VERSION 5.8 ;
BUSBITCHARS "[]" ;
DIVIDERCHAR "/" ;
UNITS
    DATABASE MICRONS 1000 ;
END UNITS

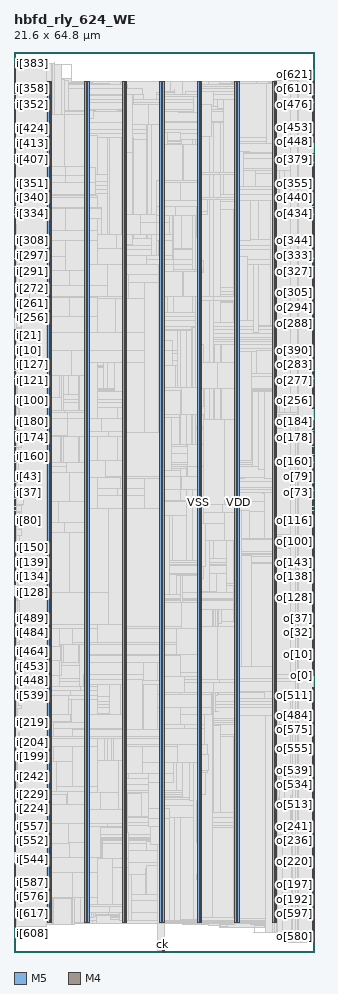
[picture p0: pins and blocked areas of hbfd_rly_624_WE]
MACRO hbfd_rly_624_WE
  FOREIGN hbfd_rly_624_WE 0 0 ;
  CLASS BLOCK ;
  SIZE 21.6 BY 64.8 ;
  PIN ck
    DIRECTION INPUT ;
    USE SIGNAL ;
    PORT
      LAYER M5 ;
        RECT  10.704 0 10.728 0.084 ;
    END
  END ck
  PIN i[0]
    DIRECTION INPUT ;
    USE SIGNAL ;
    PORT
      LAYER M4 ;
        RECT  0 41.808 0.084 41.832 ;
    END
  END i[0]
  PIN i[100]
    DIRECTION INPUT ;
    USE SIGNAL ;
    PORT
      LAYER M4 ;
        RECT  0 39.12 0.084 39.144 ;
    END
  END i[100]
  PIN i[101]
    DIRECTION INPUT ;
    USE SIGNAL ;
    PORT
      LAYER M4 ;
        RECT  0 39.216 0.084 39.24 ;
    END
  END i[101]
  PIN i[102]
    DIRECTION INPUT ;
    USE SIGNAL ;
    PORT
      LAYER M4 ;
        RECT  0 39.312 0.084 39.336 ;
    END
  END i[102]
  PIN i[103]
    DIRECTION INPUT ;
    USE SIGNAL ;
    PORT
      LAYER M4 ;
        RECT  0 39.408 0.084 39.432 ;
    END
  END i[103]
  PIN i[104]
    DIRECTION INPUT ;
    USE SIGNAL ;
    PORT
      LAYER M4 ;
        RECT  0 39.504 0.084 39.528 ;
    END
  END i[104]
  PIN i[105]
    DIRECTION INPUT ;
    USE SIGNAL ;
    PORT
      LAYER M4 ;
        RECT  0 39.6 0.084 39.624 ;
    END
  END i[105]
  PIN i[106]
    DIRECTION INPUT ;
    USE SIGNAL ;
    PORT
      LAYER M4 ;
        RECT  0 39.696 0.084 39.72 ;
    END
  END i[106]
  PIN i[107]
    DIRECTION INPUT ;
    USE SIGNAL ;
    PORT
      LAYER M4 ;
        RECT  0 39.792 0.084 39.816 ;
    END
  END i[107]
  PIN i[108]
    DIRECTION INPUT ;
    USE SIGNAL ;
    PORT
      LAYER M4 ;
        RECT  0 39.888 0.084 39.912 ;
    END
  END i[108]
  PIN i[109]
    DIRECTION INPUT ;
    USE SIGNAL ;
    PORT
      LAYER M4 ;
        RECT  0 39.984 0.084 40.008 ;
    END
  END i[109]
  PIN i[10]
    DIRECTION INPUT ;
    USE SIGNAL ;
    PORT
      LAYER M4 ;
        RECT  0 42.768 0.084 42.792 ;
    END
  END i[10]
  PIN i[110]
    DIRECTION INPUT ;
    USE SIGNAL ;
    PORT
      LAYER M4 ;
        RECT  0 40.08 0.084 40.104 ;
    END
  END i[110]
  PIN i[111]
    DIRECTION INPUT ;
    USE SIGNAL ;
    PORT
      LAYER M4 ;
        RECT  0 40.176 0.084 40.2 ;
    END
  END i[111]
  PIN i[112]
    DIRECTION INPUT ;
    USE SIGNAL ;
    PORT
      LAYER M4 ;
        RECT  0 40.272 0.084 40.296 ;
    END
  END i[112]
  PIN i[113]
    DIRECTION INPUT ;
    USE SIGNAL ;
    PORT
      LAYER M4 ;
        RECT  0 40.368 0.084 40.392 ;
    END
  END i[113]
  PIN i[114]
    DIRECTION INPUT ;
    USE SIGNAL ;
    PORT
      LAYER M4 ;
        RECT  0 40.464 0.084 40.488 ;
    END
  END i[114]
  PIN i[115]
    DIRECTION INPUT ;
    USE SIGNAL ;
    PORT
      LAYER M4 ;
        RECT  0 40.56 0.084 40.584 ;
    END
  END i[115]
  PIN i[116]
    DIRECTION INPUT ;
    USE SIGNAL ;
    PORT
      LAYER M4 ;
        RECT  0 40.656 0.084 40.68 ;
    END
  END i[116]
  PIN i[117]
    DIRECTION INPUT ;
    USE SIGNAL ;
    PORT
      LAYER M4 ;
        RECT  0 40.752 0.084 40.776 ;
    END
  END i[117]
  PIN i[118]
    DIRECTION INPUT ;
    USE SIGNAL ;
    PORT
      LAYER M4 ;
        RECT  0 40.848 0.084 40.872 ;
    END
  END i[118]
  PIN i[119]
    DIRECTION INPUT ;
    USE SIGNAL ;
    PORT
      LAYER M4 ;
        RECT  0 40.944 0.084 40.968 ;
    END
  END i[119]
  PIN i[11]
    DIRECTION INPUT ;
    USE SIGNAL ;
    PORT
      LAYER M4 ;
        RECT  0 42.864 0.084 42.888 ;
    END
  END i[11]
  PIN i[120]
    DIRECTION INPUT ;
    USE SIGNAL ;
    PORT
      LAYER M4 ;
        RECT  0 41.04 0.084 41.064 ;
    END
  END i[120]
  PIN i[121]
    DIRECTION INPUT ;
    USE SIGNAL ;
    PORT
      LAYER M4 ;
        RECT  0 41.136 0.084 41.16 ;
    END
  END i[121]
  PIN i[122]
    DIRECTION INPUT ;
    USE SIGNAL ;
    PORT
      LAYER M4 ;
        RECT  0 41.232 0.084 41.256 ;
    END
  END i[122]
  PIN i[123]
    DIRECTION INPUT ;
    USE SIGNAL ;
    PORT
      LAYER M4 ;
        RECT  0 41.328 0.084 41.352 ;
    END
  END i[123]
  PIN i[124]
    DIRECTION INPUT ;
    USE SIGNAL ;
    PORT
      LAYER M4 ;
        RECT  0 41.424 0.084 41.448 ;
    END
  END i[124]
  PIN i[125]
    DIRECTION INPUT ;
    USE SIGNAL ;
    PORT
      LAYER M4 ;
        RECT  0 41.52 0.084 41.544 ;
    END
  END i[125]
  PIN i[126]
    DIRECTION INPUT ;
    USE SIGNAL ;
    PORT
      LAYER M4 ;
        RECT  0 41.616 0.084 41.64 ;
    END
  END i[126]
  PIN i[127]
    DIRECTION INPUT ;
    USE SIGNAL ;
    PORT
      LAYER M4 ;
        RECT  0 41.712 0.084 41.736 ;
    END
  END i[127]
  PIN i[128]
    DIRECTION INPUT ;
    USE SIGNAL ;
    PORT
      LAYER M4 ;
        RECT  0 26.448 0.084 26.472 ;
    END
  END i[128]
  PIN i[129]
    DIRECTION INPUT ;
    USE SIGNAL ;
    PORT
      LAYER M4 ;
        RECT  0 26.544 0.084 26.568 ;
    END
  END i[129]
  PIN i[12]
    DIRECTION INPUT ;
    USE SIGNAL ;
    PORT
      LAYER M4 ;
        RECT  0 42.96 0.084 42.984 ;
    END
  END i[12]
  PIN i[130]
    DIRECTION INPUT ;
    USE SIGNAL ;
    PORT
      LAYER M4 ;
        RECT  0 26.64 0.084 26.664 ;
    END
  END i[130]
  PIN i[131]
    DIRECTION INPUT ;
    USE SIGNAL ;
    PORT
      LAYER M4 ;
        RECT  0 26.736 0.084 26.76 ;
    END
  END i[131]
  PIN i[132]
    DIRECTION INPUT ;
    USE SIGNAL ;
    PORT
      LAYER M4 ;
        RECT  0 26.832 0.084 26.856 ;
    END
  END i[132]
  PIN i[133]
    DIRECTION INPUT ;
    USE SIGNAL ;
    PORT
      LAYER M4 ;
        RECT  0 26.928 0.084 26.952 ;
    END
  END i[133]
  PIN i[134]
    DIRECTION INPUT ;
    USE SIGNAL ;
    PORT
      LAYER M4 ;
        RECT  0 27.024 0.084 27.048 ;
    END
  END i[134]
  PIN i[135]
    DIRECTION INPUT ;
    USE SIGNAL ;
    PORT
      LAYER M4 ;
        RECT  0 27.12 0.084 27.144 ;
    END
  END i[135]
  PIN i[136]
    DIRECTION INPUT ;
    USE SIGNAL ;
    PORT
      LAYER M4 ;
        RECT  0 27.216 0.084 27.24 ;
    END
  END i[136]
  PIN i[137]
    DIRECTION INPUT ;
    USE SIGNAL ;
    PORT
      LAYER M4 ;
        RECT  0 27.312 0.084 27.336 ;
    END
  END i[137]
  PIN i[138]
    DIRECTION INPUT ;
    USE SIGNAL ;
    PORT
      LAYER M4 ;
        RECT  0 27.408 0.084 27.432 ;
    END
  END i[138]
  PIN i[139]
    DIRECTION INPUT ;
    USE SIGNAL ;
    PORT
      LAYER M4 ;
        RECT  0 27.504 0.084 27.528 ;
    END
  END i[139]
  PIN i[13]
    DIRECTION INPUT ;
    USE SIGNAL ;
    PORT
      LAYER M4 ;
        RECT  0 43.056 0.084 43.08 ;
    END
  END i[13]
  PIN i[140]
    DIRECTION INPUT ;
    USE SIGNAL ;
    PORT
      LAYER M4 ;
        RECT  0 27.6 0.084 27.624 ;
    END
  END i[140]
  PIN i[141]
    DIRECTION INPUT ;
    USE SIGNAL ;
    PORT
      LAYER M4 ;
        RECT  0 27.696 0.084 27.72 ;
    END
  END i[141]
  PIN i[142]
    DIRECTION INPUT ;
    USE SIGNAL ;
    PORT
      LAYER M4 ;
        RECT  0 27.792 0.084 27.816 ;
    END
  END i[142]
  PIN i[143]
    DIRECTION INPUT ;
    USE SIGNAL ;
    PORT
      LAYER M4 ;
        RECT  0 27.888 0.084 27.912 ;
    END
  END i[143]
  PIN i[144]
    DIRECTION INPUT ;
    USE SIGNAL ;
    PORT
      LAYER M4 ;
        RECT  0 27.984 0.084 28.008 ;
    END
  END i[144]
  PIN i[145]
    DIRECTION INPUT ;
    USE SIGNAL ;
    PORT
      LAYER M4 ;
        RECT  0 28.08 0.084 28.104 ;
    END
  END i[145]
  PIN i[146]
    DIRECTION INPUT ;
    USE SIGNAL ;
    PORT
      LAYER M4 ;
        RECT  0 28.176 0.084 28.2 ;
    END
  END i[146]
  PIN i[147]
    DIRECTION INPUT ;
    USE SIGNAL ;
    PORT
      LAYER M4 ;
        RECT  0 28.272 0.084 28.296 ;
    END
  END i[147]
  PIN i[148]
    DIRECTION INPUT ;
    USE SIGNAL ;
    PORT
      LAYER M4 ;
        RECT  0 28.368 0.084 28.392 ;
    END
  END i[148]
  PIN i[149]
    DIRECTION INPUT ;
    USE SIGNAL ;
    PORT
      LAYER M4 ;
        RECT  0 28.464 0.084 28.488 ;
    END
  END i[149]
  PIN i[14]
    DIRECTION INPUT ;
    USE SIGNAL ;
    PORT
      LAYER M4 ;
        RECT  0 43.152 0.084 43.176 ;
    END
  END i[14]
  PIN i[150]
    DIRECTION INPUT ;
    USE SIGNAL ;
    PORT
      LAYER M4 ;
        RECT  0 28.56 0.084 28.584 ;
    END
  END i[150]
  PIN i[151]
    DIRECTION INPUT ;
    USE SIGNAL ;
    PORT
      LAYER M4 ;
        RECT  0 28.656 0.084 28.68 ;
    END
  END i[151]
  PIN i[152]
    DIRECTION INPUT ;
    USE SIGNAL ;
    PORT
      LAYER M4 ;
        RECT  0 28.752 0.084 28.776 ;
    END
  END i[152]
  PIN i[153]
    DIRECTION INPUT ;
    USE SIGNAL ;
    PORT
      LAYER M4 ;
        RECT  0 28.848 0.084 28.872 ;
    END
  END i[153]
  PIN i[154]
    DIRECTION INPUT ;
    USE SIGNAL ;
    PORT
      LAYER M4 ;
        RECT  0 28.944 0.084 28.968 ;
    END
  END i[154]
  PIN i[155]
    DIRECTION INPUT ;
    USE SIGNAL ;
    PORT
      LAYER M4 ;
        RECT  0 29.04 0.084 29.064 ;
    END
  END i[155]
  PIN i[156]
    DIRECTION INPUT ;
    USE SIGNAL ;
    PORT
      LAYER M4 ;
        RECT  0 29.136 0.084 29.16 ;
    END
  END i[156]
  PIN i[157]
    DIRECTION INPUT ;
    USE SIGNAL ;
    PORT
      LAYER M4 ;
        RECT  0 29.232 0.084 29.256 ;
    END
  END i[157]
  PIN i[158]
    DIRECTION INPUT ;
    USE SIGNAL ;
    PORT
      LAYER M4 ;
        RECT  0 29.328 0.084 29.352 ;
    END
  END i[158]
  PIN i[159]
    DIRECTION INPUT ;
    USE SIGNAL ;
    PORT
      LAYER M4 ;
        RECT  0 29.424 0.084 29.448 ;
    END
  END i[159]
  PIN i[15]
    DIRECTION INPUT ;
    USE SIGNAL ;
    PORT
      LAYER M4 ;
        RECT  0 43.248 0.084 43.272 ;
    END
  END i[15]
  PIN i[160]
    DIRECTION INPUT ;
    USE SIGNAL ;
    PORT
      LAYER M4 ;
        RECT  0 35.664 0.084 35.688 ;
    END
  END i[160]
  PIN i[161]
    DIRECTION INPUT ;
    USE SIGNAL ;
    PORT
      LAYER M4 ;
        RECT  0 35.76 0.084 35.784 ;
    END
  END i[161]
  PIN i[162]
    DIRECTION INPUT ;
    USE SIGNAL ;
    PORT
      LAYER M4 ;
        RECT  0 35.856 0.084 35.88 ;
    END
  END i[162]
  PIN i[163]
    DIRECTION INPUT ;
    USE SIGNAL ;
    PORT
      LAYER M4 ;
        RECT  0 35.952 0.084 35.976 ;
    END
  END i[163]
  PIN i[164]
    DIRECTION INPUT ;
    USE SIGNAL ;
    PORT
      LAYER M4 ;
        RECT  0 36.048 0.084 36.072 ;
    END
  END i[164]
  PIN i[165]
    DIRECTION INPUT ;
    USE SIGNAL ;
    PORT
      LAYER M4 ;
        RECT  0 36.144 0.084 36.168 ;
    END
  END i[165]
  PIN i[166]
    DIRECTION INPUT ;
    USE SIGNAL ;
    PORT
      LAYER M4 ;
        RECT  0 36.24 0.084 36.264 ;
    END
  END i[166]
  PIN i[167]
    DIRECTION INPUT ;
    USE SIGNAL ;
    PORT
      LAYER M4 ;
        RECT  0 36.336 0.084 36.36 ;
    END
  END i[167]
  PIN i[168]
    DIRECTION INPUT ;
    USE SIGNAL ;
    PORT
      LAYER M4 ;
        RECT  0 36.432 0.084 36.456 ;
    END
  END i[168]
  PIN i[169]
    DIRECTION INPUT ;
    USE SIGNAL ;
    PORT
      LAYER M4 ;
        RECT  0 36.528 0.084 36.552 ;
    END
  END i[169]
  PIN i[16]
    DIRECTION INPUT ;
    USE SIGNAL ;
    PORT
      LAYER M4 ;
        RECT  0 43.344 0.084 43.368 ;
    END
  END i[16]
  PIN i[170]
    DIRECTION INPUT ;
    USE SIGNAL ;
    PORT
      LAYER M4 ;
        RECT  0 36.624 0.084 36.648 ;
    END
  END i[170]
  PIN i[171]
    DIRECTION INPUT ;
    USE SIGNAL ;
    PORT
      LAYER M4 ;
        RECT  0 36.72 0.084 36.744 ;
    END
  END i[171]
  PIN i[172]
    DIRECTION INPUT ;
    USE SIGNAL ;
    PORT
      LAYER M4 ;
        RECT  0 36.816 0.084 36.84 ;
    END
  END i[172]
  PIN i[173]
    DIRECTION INPUT ;
    USE SIGNAL ;
    PORT
      LAYER M4 ;
        RECT  0 36.912 0.084 36.936 ;
    END
  END i[173]
  PIN i[174]
    DIRECTION INPUT ;
    USE SIGNAL ;
    PORT
      LAYER M4 ;
        RECT  0 37.008 0.084 37.032 ;
    END
  END i[174]
  PIN i[175]
    DIRECTION INPUT ;
    USE SIGNAL ;
    PORT
      LAYER M4 ;
        RECT  0 37.104 0.084 37.128 ;
    END
  END i[175]
  PIN i[176]
    DIRECTION INPUT ;
    USE SIGNAL ;
    PORT
      LAYER M4 ;
        RECT  0 37.2 0.084 37.224 ;
    END
  END i[176]
  PIN i[177]
    DIRECTION INPUT ;
    USE SIGNAL ;
    PORT
      LAYER M4 ;
        RECT  0 37.296 0.084 37.32 ;
    END
  END i[177]
  PIN i[178]
    DIRECTION INPUT ;
    USE SIGNAL ;
    PORT
      LAYER M4 ;
        RECT  0 37.392 0.084 37.416 ;
    END
  END i[178]
  PIN i[179]
    DIRECTION INPUT ;
    USE SIGNAL ;
    PORT
      LAYER M4 ;
        RECT  0 37.488 0.084 37.512 ;
    END
  END i[179]
  PIN i[17]
    DIRECTION INPUT ;
    USE SIGNAL ;
    PORT
      LAYER M4 ;
        RECT  0 43.44 0.084 43.464 ;
    END
  END i[17]
  PIN i[180]
    DIRECTION INPUT ;
    USE SIGNAL ;
    PORT
      LAYER M4 ;
        RECT  0 37.584 0.084 37.608 ;
    END
  END i[180]
  PIN i[181]
    DIRECTION INPUT ;
    USE SIGNAL ;
    PORT
      LAYER M4 ;
        RECT  0 37.68 0.084 37.704 ;
    END
  END i[181]
  PIN i[182]
    DIRECTION INPUT ;
    USE SIGNAL ;
    PORT
      LAYER M4 ;
        RECT  0 37.776 0.084 37.8 ;
    END
  END i[182]
  PIN i[183]
    DIRECTION INPUT ;
    USE SIGNAL ;
    PORT
      LAYER M4 ;
        RECT  0 37.872 0.084 37.896 ;
    END
  END i[183]
  PIN i[184]
    DIRECTION INPUT ;
    USE SIGNAL ;
    PORT
      LAYER M4 ;
        RECT  0 37.968 0.084 37.992 ;
    END
  END i[184]
  PIN i[185]
    DIRECTION INPUT ;
    USE SIGNAL ;
    PORT
      LAYER M4 ;
        RECT  0 38.064 0.084 38.088 ;
    END
  END i[185]
  PIN i[186]
    DIRECTION INPUT ;
    USE SIGNAL ;
    PORT
      LAYER M4 ;
        RECT  0 38.16 0.084 38.184 ;
    END
  END i[186]
  PIN i[187]
    DIRECTION INPUT ;
    USE SIGNAL ;
    PORT
      LAYER M4 ;
        RECT  0 38.256 0.084 38.28 ;
    END
  END i[187]
  PIN i[188]
    DIRECTION INPUT ;
    USE SIGNAL ;
    PORT
      LAYER M4 ;
        RECT  0 38.352 0.084 38.376 ;
    END
  END i[188]
  PIN i[189]
    DIRECTION INPUT ;
    USE SIGNAL ;
    PORT
      LAYER M4 ;
        RECT  0 38.448 0.084 38.472 ;
    END
  END i[189]
  PIN i[18]
    DIRECTION INPUT ;
    USE SIGNAL ;
    PORT
      LAYER M4 ;
        RECT  0 43.536 0.084 43.56 ;
    END
  END i[18]
  PIN i[190]
    DIRECTION INPUT ;
    USE SIGNAL ;
    PORT
      LAYER M4 ;
        RECT  0 38.544 0.084 38.568 ;
    END
  END i[190]
  PIN i[191]
    DIRECTION INPUT ;
    USE SIGNAL ;
    PORT
      LAYER M4 ;
        RECT  0 38.64 0.084 38.664 ;
    END
  END i[191]
  PIN i[192]
    DIRECTION INPUT ;
    USE SIGNAL ;
    PORT
      LAYER M4 ;
        RECT  0 13.392 0.084 13.416 ;
    END
  END i[192]
  PIN i[193]
    DIRECTION INPUT ;
    USE SIGNAL ;
    PORT
      LAYER M4 ;
        RECT  0 13.488 0.084 13.512 ;
    END
  END i[193]
  PIN i[194]
    DIRECTION INPUT ;
    USE SIGNAL ;
    PORT
      LAYER M4 ;
        RECT  0 13.584 0.084 13.608 ;
    END
  END i[194]
  PIN i[195]
    DIRECTION INPUT ;
    USE SIGNAL ;
    PORT
      LAYER M4 ;
        RECT  0 13.68 0.084 13.704 ;
    END
  END i[195]
  PIN i[196]
    DIRECTION INPUT ;
    USE SIGNAL ;
    PORT
      LAYER M4 ;
        RECT  0 13.776 0.084 13.8 ;
    END
  END i[196]
  PIN i[197]
    DIRECTION INPUT ;
    USE SIGNAL ;
    PORT
      LAYER M4 ;
        RECT  0 13.872 0.084 13.896 ;
    END
  END i[197]
  PIN i[198]
    DIRECTION INPUT ;
    USE SIGNAL ;
    PORT
      LAYER M4 ;
        RECT  0 13.968 0.084 13.992 ;
    END
  END i[198]
  PIN i[199]
    DIRECTION INPUT ;
    USE SIGNAL ;
    PORT
      LAYER M4 ;
        RECT  0 14.064 0.084 14.088 ;
    END
  END i[199]
  PIN i[19]
    DIRECTION INPUT ;
    USE SIGNAL ;
    PORT
      LAYER M4 ;
        RECT  0 43.632 0.084 43.656 ;
    END
  END i[19]
  PIN i[1]
    DIRECTION INPUT ;
    USE SIGNAL ;
    PORT
      LAYER M4 ;
        RECT  0 41.904 0.084 41.928 ;
    END
  END i[1]
  PIN i[200]
    DIRECTION INPUT ;
    USE SIGNAL ;
    PORT
      LAYER M4 ;
        RECT  0 14.16 0.084 14.184 ;
    END
  END i[200]
  PIN i[201]
    DIRECTION INPUT ;
    USE SIGNAL ;
    PORT
      LAYER M4 ;
        RECT  0 14.256 0.084 14.28 ;
    END
  END i[201]
  PIN i[202]
    DIRECTION INPUT ;
    USE SIGNAL ;
    PORT
      LAYER M4 ;
        RECT  0 14.352 0.084 14.376 ;
    END
  END i[202]
  PIN i[203]
    DIRECTION INPUT ;
    USE SIGNAL ;
    PORT
      LAYER M4 ;
        RECT  0 14.448 0.084 14.472 ;
    END
  END i[203]
  PIN i[204]
    DIRECTION INPUT ;
    USE SIGNAL ;
    PORT
      LAYER M4 ;
        RECT  0 14.544 0.084 14.568 ;
    END
  END i[204]
  PIN i[205]
    DIRECTION INPUT ;
    USE SIGNAL ;
    PORT
      LAYER M4 ;
        RECT  0 14.64 0.084 14.664 ;
    END
  END i[205]
  PIN i[206]
    DIRECTION INPUT ;
    USE SIGNAL ;
    PORT
      LAYER M4 ;
        RECT  0 14.736 0.084 14.76 ;
    END
  END i[206]
  PIN i[207]
    DIRECTION INPUT ;
    USE SIGNAL ;
    PORT
      LAYER M4 ;
        RECT  0 14.832 0.084 14.856 ;
    END
  END i[207]
  PIN i[208]
    DIRECTION INPUT ;
    USE SIGNAL ;
    PORT
      LAYER M4 ;
        RECT  0 14.928 0.084 14.952 ;
    END
  END i[208]
  PIN i[209]
    DIRECTION INPUT ;
    USE SIGNAL ;
    PORT
      LAYER M4 ;
        RECT  0 15.024 0.084 15.048 ;
    END
  END i[209]
  PIN i[20]
    DIRECTION INPUT ;
    USE SIGNAL ;
    PORT
      LAYER M4 ;
        RECT  0 43.728 0.084 43.752 ;
    END
  END i[20]
  PIN i[210]
    DIRECTION INPUT ;
    USE SIGNAL ;
    PORT
      LAYER M4 ;
        RECT  0 15.12 0.084 15.144 ;
    END
  END i[210]
  PIN i[211]
    DIRECTION INPUT ;
    USE SIGNAL ;
    PORT
      LAYER M4 ;
        RECT  0 15.216 0.084 15.24 ;
    END
  END i[211]
  PIN i[212]
    DIRECTION INPUT ;
    USE SIGNAL ;
    PORT
      LAYER M4 ;
        RECT  0 15.312 0.084 15.336 ;
    END
  END i[212]
  PIN i[213]
    DIRECTION INPUT ;
    USE SIGNAL ;
    PORT
      LAYER M4 ;
        RECT  0 15.408 0.084 15.432 ;
    END
  END i[213]
  PIN i[214]
    DIRECTION INPUT ;
    USE SIGNAL ;
    PORT
      LAYER M4 ;
        RECT  0 15.504 0.084 15.528 ;
    END
  END i[214]
  PIN i[215]
    DIRECTION INPUT ;
    USE SIGNAL ;
    PORT
      LAYER M4 ;
        RECT  0 15.6 0.084 15.624 ;
    END
  END i[215]
  PIN i[216]
    DIRECTION INPUT ;
    USE SIGNAL ;
    PORT
      LAYER M4 ;
        RECT  0 15.696 0.084 15.72 ;
    END
  END i[216]
  PIN i[217]
    DIRECTION INPUT ;
    USE SIGNAL ;
    PORT
      LAYER M4 ;
        RECT  0 15.792 0.084 15.816 ;
    END
  END i[217]
  PIN i[218]
    DIRECTION INPUT ;
    USE SIGNAL ;
    PORT
      LAYER M4 ;
        RECT  0 15.888 0.084 15.912 ;
    END
  END i[218]
  PIN i[219]
    DIRECTION INPUT ;
    USE SIGNAL ;
    PORT
      LAYER M4 ;
        RECT  0 15.984 0.084 16.008 ;
    END
  END i[219]
  PIN i[21]
    DIRECTION INPUT ;
    USE SIGNAL ;
    PORT
      LAYER M4 ;
        RECT  0 43.824 0.084 43.848 ;
    END
  END i[21]
  PIN i[220]
    DIRECTION INPUT ;
    USE SIGNAL ;
    PORT
      LAYER M4 ;
        RECT  0 16.08 0.084 16.104 ;
    END
  END i[220]
  PIN i[221]
    DIRECTION INPUT ;
    USE SIGNAL ;
    PORT
      LAYER M4 ;
        RECT  0 16.176 0.084 16.2 ;
    END
  END i[221]
  PIN i[222]
    DIRECTION INPUT ;
    USE SIGNAL ;
    PORT
      LAYER M4 ;
        RECT  0 16.272 0.084 16.296 ;
    END
  END i[222]
  PIN i[223]
    DIRECTION INPUT ;
    USE SIGNAL ;
    PORT
      LAYER M4 ;
        RECT  0 16.368 0.084 16.392 ;
    END
  END i[223]
  PIN i[224]
    DIRECTION INPUT ;
    USE SIGNAL ;
    PORT
      LAYER M4 ;
        RECT  0 10.32 0.084 10.344 ;
    END
  END i[224]
  PIN i[225]
    DIRECTION INPUT ;
    USE SIGNAL ;
    PORT
      LAYER M4 ;
        RECT  0 10.416 0.084 10.44 ;
    END
  END i[225]
  PIN i[226]
    DIRECTION INPUT ;
    USE SIGNAL ;
    PORT
      LAYER M4 ;
        RECT  0 10.512 0.084 10.536 ;
    END
  END i[226]
  PIN i[227]
    DIRECTION INPUT ;
    USE SIGNAL ;
    PORT
      LAYER M4 ;
        RECT  0 10.608 0.084 10.632 ;
    END
  END i[227]
  PIN i[228]
    DIRECTION INPUT ;
    USE SIGNAL ;
    PORT
      LAYER M4 ;
        RECT  0 10.704 0.084 10.728 ;
    END
  END i[228]
  PIN i[229]
    DIRECTION INPUT ;
    USE SIGNAL ;
    PORT
      LAYER M4 ;
        RECT  0 10.8 0.084 10.824 ;
    END
  END i[229]
  PIN i[22]
    DIRECTION INPUT ;
    USE SIGNAL ;
    PORT
      LAYER M4 ;
        RECT  0 43.92 0.084 43.944 ;
    END
  END i[22]
  PIN i[230]
    DIRECTION INPUT ;
    USE SIGNAL ;
    PORT
      LAYER M4 ;
        RECT  0 10.896 0.084 10.92 ;
    END
  END i[230]
  PIN i[231]
    DIRECTION INPUT ;
    USE SIGNAL ;
    PORT
      LAYER M4 ;
        RECT  0 10.992 0.084 11.016 ;
    END
  END i[231]
  PIN i[232]
    DIRECTION INPUT ;
    USE SIGNAL ;
    PORT
      LAYER M4 ;
        RECT  0 11.088 0.084 11.112 ;
    END
  END i[232]
  PIN i[233]
    DIRECTION INPUT ;
    USE SIGNAL ;
    PORT
      LAYER M4 ;
        RECT  0 11.184 0.084 11.208 ;
    END
  END i[233]
  PIN i[234]
    DIRECTION INPUT ;
    USE SIGNAL ;
    PORT
      LAYER M4 ;
        RECT  0 11.28 0.084 11.304 ;
    END
  END i[234]
  PIN i[235]
    DIRECTION INPUT ;
    USE SIGNAL ;
    PORT
      LAYER M4 ;
        RECT  0 11.376 0.084 11.4 ;
    END
  END i[235]
  PIN i[236]
    DIRECTION INPUT ;
    USE SIGNAL ;
    PORT
      LAYER M4 ;
        RECT  0 11.472 0.084 11.496 ;
    END
  END i[236]
  PIN i[237]
    DIRECTION INPUT ;
    USE SIGNAL ;
    PORT
      LAYER M4 ;
        RECT  0 11.568 0.084 11.592 ;
    END
  END i[237]
  PIN i[238]
    DIRECTION INPUT ;
    USE SIGNAL ;
    PORT
      LAYER M4 ;
        RECT  0 11.664 0.084 11.688 ;
    END
  END i[238]
  PIN i[239]
    DIRECTION INPUT ;
    USE SIGNAL ;
    PORT
      LAYER M4 ;
        RECT  0 11.76 0.084 11.784 ;
    END
  END i[239]
  PIN i[23]
    DIRECTION INPUT ;
    USE SIGNAL ;
    PORT
      LAYER M4 ;
        RECT  0 44.016 0.084 44.04 ;
    END
  END i[23]
  PIN i[240]
    DIRECTION INPUT ;
    USE SIGNAL ;
    PORT
      LAYER M4 ;
        RECT  0 11.856 0.084 11.88 ;
    END
  END i[240]
  PIN i[241]
    DIRECTION INPUT ;
    USE SIGNAL ;
    PORT
      LAYER M4 ;
        RECT  0 11.952 0.084 11.976 ;
    END
  END i[241]
  PIN i[242]
    DIRECTION INPUT ;
    USE SIGNAL ;
    PORT
      LAYER M4 ;
        RECT  0 12.048 0.084 12.072 ;
    END
  END i[242]
  PIN i[243]
    DIRECTION INPUT ;
    USE SIGNAL ;
    PORT
      LAYER M4 ;
        RECT  0 12.144 0.084 12.168 ;
    END
  END i[243]
  PIN i[244]
    DIRECTION INPUT ;
    USE SIGNAL ;
    PORT
      LAYER M4 ;
        RECT  0 12.24 0.084 12.264 ;
    END
  END i[244]
  PIN i[245]
    DIRECTION INPUT ;
    USE SIGNAL ;
    PORT
      LAYER M4 ;
        RECT  0 12.336 0.084 12.36 ;
    END
  END i[245]
  PIN i[246]
    DIRECTION INPUT ;
    USE SIGNAL ;
    PORT
      LAYER M4 ;
        RECT  0 12.432 0.084 12.456 ;
    END
  END i[246]
  PIN i[247]
    DIRECTION INPUT ;
    USE SIGNAL ;
    PORT
      LAYER M4 ;
        RECT  0 12.528 0.084 12.552 ;
    END
  END i[247]
  PIN i[248]
    DIRECTION INPUT ;
    USE SIGNAL ;
    PORT
      LAYER M4 ;
        RECT  0 12.624 0.084 12.648 ;
    END
  END i[248]
  PIN i[249]
    DIRECTION INPUT ;
    USE SIGNAL ;
    PORT
      LAYER M4 ;
        RECT  0 12.72 0.084 12.744 ;
    END
  END i[249]
  PIN i[24]
    DIRECTION INPUT ;
    USE SIGNAL ;
    PORT
      LAYER M4 ;
        RECT  0 44.112 0.084 44.136 ;
    END
  END i[24]
  PIN i[250]
    DIRECTION INPUT ;
    USE SIGNAL ;
    PORT
      LAYER M4 ;
        RECT  0 12.816 0.084 12.84 ;
    END
  END i[250]
  PIN i[251]
    DIRECTION INPUT ;
    USE SIGNAL ;
    PORT
      LAYER M4 ;
        RECT  0 12.912 0.084 12.936 ;
    END
  END i[251]
  PIN i[252]
    DIRECTION INPUT ;
    USE SIGNAL ;
    PORT
      LAYER M4 ;
        RECT  0 13.008 0.084 13.032 ;
    END
  END i[252]
  PIN i[253]
    DIRECTION INPUT ;
    USE SIGNAL ;
    PORT
      LAYER M4 ;
        RECT  0 13.104 0.084 13.128 ;
    END
  END i[253]
  PIN i[254]
    DIRECTION INPUT ;
    USE SIGNAL ;
    PORT
      LAYER M4 ;
        RECT  0 13.2 0.084 13.224 ;
    END
  END i[254]
  PIN i[255]
    DIRECTION INPUT ;
    USE SIGNAL ;
    PORT
      LAYER M4 ;
        RECT  0 13.296 0.084 13.32 ;
    END
  END i[255]
  PIN i[256]
    DIRECTION INPUT ;
    USE SIGNAL ;
    PORT
      LAYER M4 ;
        RECT  0 45.648 0.084 45.672 ;
    END
  END i[256]
  PIN i[257]
    DIRECTION INPUT ;
    USE SIGNAL ;
    PORT
      LAYER M4 ;
        RECT  0 45.744 0.084 45.768 ;
    END
  END i[257]
  PIN i[258]
    DIRECTION INPUT ;
    USE SIGNAL ;
    PORT
      LAYER M4 ;
        RECT  0 45.84 0.084 45.864 ;
    END
  END i[258]
  PIN i[259]
    DIRECTION INPUT ;
    USE SIGNAL ;
    PORT
      LAYER M4 ;
        RECT  0 45.936 0.084 45.96 ;
    END
  END i[259]
  PIN i[25]
    DIRECTION INPUT ;
    USE SIGNAL ;
    PORT
      LAYER M4 ;
        RECT  0 44.208 0.084 44.232 ;
    END
  END i[25]
  PIN i[260]
    DIRECTION INPUT ;
    USE SIGNAL ;
    PORT
      LAYER M4 ;
        RECT  0 46.032 0.084 46.056 ;
    END
  END i[260]
  PIN i[261]
    DIRECTION INPUT ;
    USE SIGNAL ;
    PORT
      LAYER M4 ;
        RECT  0 46.128 0.084 46.152 ;
    END
  END i[261]
  PIN i[262]
    DIRECTION INPUT ;
    USE SIGNAL ;
    PORT
      LAYER M4 ;
        RECT  0 46.224 0.084 46.248 ;
    END
  END i[262]
  PIN i[263]
    DIRECTION INPUT ;
    USE SIGNAL ;
    PORT
      LAYER M4 ;
        RECT  0 46.32 0.084 46.344 ;
    END
  END i[263]
  PIN i[264]
    DIRECTION INPUT ;
    USE SIGNAL ;
    PORT
      LAYER M4 ;
        RECT  0 46.416 0.084 46.44 ;
    END
  END i[264]
  PIN i[265]
    DIRECTION INPUT ;
    USE SIGNAL ;
    PORT
      LAYER M4 ;
        RECT  0 46.512 0.084 46.536 ;
    END
  END i[265]
  PIN i[266]
    DIRECTION INPUT ;
    USE SIGNAL ;
    PORT
      LAYER M4 ;
        RECT  0 46.608 0.084 46.632 ;
    END
  END i[266]
  PIN i[267]
    DIRECTION INPUT ;
    USE SIGNAL ;
    PORT
      LAYER M4 ;
        RECT  0 46.704 0.084 46.728 ;
    END
  END i[267]
  PIN i[268]
    DIRECTION INPUT ;
    USE SIGNAL ;
    PORT
      LAYER M4 ;
        RECT  0 46.8 0.084 46.824 ;
    END
  END i[268]
  PIN i[269]
    DIRECTION INPUT ;
    USE SIGNAL ;
    PORT
      LAYER M4 ;
        RECT  0 46.896 0.084 46.92 ;
    END
  END i[269]
  PIN i[26]
    DIRECTION INPUT ;
    USE SIGNAL ;
    PORT
      LAYER M4 ;
        RECT  0 44.304 0.084 44.328 ;
    END
  END i[26]
  PIN i[270]
    DIRECTION INPUT ;
    USE SIGNAL ;
    PORT
      LAYER M4 ;
        RECT  0 46.992 0.084 47.016 ;
    END
  END i[270]
  PIN i[271]
    DIRECTION INPUT ;
    USE SIGNAL ;
    PORT
      LAYER M4 ;
        RECT  0 47.088 0.084 47.112 ;
    END
  END i[271]
  PIN i[272]
    DIRECTION INPUT ;
    USE SIGNAL ;
    PORT
      LAYER M4 ;
        RECT  0 47.184 0.084 47.208 ;
    END
  END i[272]
  PIN i[273]
    DIRECTION INPUT ;
    USE SIGNAL ;
    PORT
      LAYER M4 ;
        RECT  0 47.28 0.084 47.304 ;
    END
  END i[273]
  PIN i[274]
    DIRECTION INPUT ;
    USE SIGNAL ;
    PORT
      LAYER M4 ;
        RECT  0 47.376 0.084 47.4 ;
    END
  END i[274]
  PIN i[275]
    DIRECTION INPUT ;
    USE SIGNAL ;
    PORT
      LAYER M4 ;
        RECT  0 47.472 0.084 47.496 ;
    END
  END i[275]
  PIN i[276]
    DIRECTION INPUT ;
    USE SIGNAL ;
    PORT
      LAYER M4 ;
        RECT  0 47.568 0.084 47.592 ;
    END
  END i[276]
  PIN i[277]
    DIRECTION INPUT ;
    USE SIGNAL ;
    PORT
      LAYER M4 ;
        RECT  0 47.664 0.084 47.688 ;
    END
  END i[277]
  PIN i[278]
    DIRECTION INPUT ;
    USE SIGNAL ;
    PORT
      LAYER M4 ;
        RECT  0 47.76 0.084 47.784 ;
    END
  END i[278]
  PIN i[279]
    DIRECTION INPUT ;
    USE SIGNAL ;
    PORT
      LAYER M4 ;
        RECT  0 47.856 0.084 47.88 ;
    END
  END i[279]
  PIN i[27]
    DIRECTION INPUT ;
    USE SIGNAL ;
    PORT
      LAYER M4 ;
        RECT  0 44.4 0.084 44.424 ;
    END
  END i[27]
  PIN i[280]
    DIRECTION INPUT ;
    USE SIGNAL ;
    PORT
      LAYER M4 ;
        RECT  0 47.952 0.084 47.976 ;
    END
  END i[280]
  PIN i[281]
    DIRECTION INPUT ;
    USE SIGNAL ;
    PORT
      LAYER M4 ;
        RECT  0 48.048 0.084 48.072 ;
    END
  END i[281]
  PIN i[282]
    DIRECTION INPUT ;
    USE SIGNAL ;
    PORT
      LAYER M4 ;
        RECT  0 48.144 0.084 48.168 ;
    END
  END i[282]
  PIN i[283]
    DIRECTION INPUT ;
    USE SIGNAL ;
    PORT
      LAYER M4 ;
        RECT  0 48.24 0.084 48.264 ;
    END
  END i[283]
  PIN i[284]
    DIRECTION INPUT ;
    USE SIGNAL ;
    PORT
      LAYER M4 ;
        RECT  0 48.336 0.084 48.36 ;
    END
  END i[284]
  PIN i[285]
    DIRECTION INPUT ;
    USE SIGNAL ;
    PORT
      LAYER M4 ;
        RECT  0 48.432 0.084 48.456 ;
    END
  END i[285]
  PIN i[286]
    DIRECTION INPUT ;
    USE SIGNAL ;
    PORT
      LAYER M4 ;
        RECT  0 48.528 0.084 48.552 ;
    END
  END i[286]
  PIN i[287]
    DIRECTION INPUT ;
    USE SIGNAL ;
    PORT
      LAYER M4 ;
        RECT  0 48.624 0.084 48.648 ;
    END
  END i[287]
  PIN i[288]
    DIRECTION INPUT ;
    USE SIGNAL ;
    PORT
      LAYER M4 ;
        RECT  0 48.72 0.084 48.744 ;
    END
  END i[288]
  PIN i[289]
    DIRECTION INPUT ;
    USE SIGNAL ;
    PORT
      LAYER M4 ;
        RECT  0 48.816 0.084 48.84 ;
    END
  END i[289]
  PIN i[28]
    DIRECTION INPUT ;
    USE SIGNAL ;
    PORT
      LAYER M4 ;
        RECT  0 44.496 0.084 44.52 ;
    END
  END i[28]
  PIN i[290]
    DIRECTION INPUT ;
    USE SIGNAL ;
    PORT
      LAYER M4 ;
        RECT  0 48.912 0.084 48.936 ;
    END
  END i[290]
  PIN i[291]
    DIRECTION INPUT ;
    USE SIGNAL ;
    PORT
      LAYER M4 ;
        RECT  0 49.008 0.084 49.032 ;
    END
  END i[291]
  PIN i[292]
    DIRECTION INPUT ;
    USE SIGNAL ;
    PORT
      LAYER M4 ;
        RECT  0 49.104 0.084 49.128 ;
    END
  END i[292]
  PIN i[293]
    DIRECTION INPUT ;
    USE SIGNAL ;
    PORT
      LAYER M4 ;
        RECT  0 49.2 0.084 49.224 ;
    END
  END i[293]
  PIN i[294]
    DIRECTION INPUT ;
    USE SIGNAL ;
    PORT
      LAYER M4 ;
        RECT  0 49.296 0.084 49.32 ;
    END
  END i[294]
  PIN i[295]
    DIRECTION INPUT ;
    USE SIGNAL ;
    PORT
      LAYER M4 ;
        RECT  0 49.392 0.084 49.416 ;
    END
  END i[295]
  PIN i[296]
    DIRECTION INPUT ;
    USE SIGNAL ;
    PORT
      LAYER M4 ;
        RECT  0 49.488 0.084 49.512 ;
    END
  END i[296]
  PIN i[297]
    DIRECTION INPUT ;
    USE SIGNAL ;
    PORT
      LAYER M4 ;
        RECT  0 49.584 0.084 49.608 ;
    END
  END i[297]
  PIN i[298]
    DIRECTION INPUT ;
    USE SIGNAL ;
    PORT
      LAYER M4 ;
        RECT  0 49.68 0.084 49.704 ;
    END
  END i[298]
  PIN i[299]
    DIRECTION INPUT ;
    USE SIGNAL ;
    PORT
      LAYER M4 ;
        RECT  0 49.776 0.084 49.8 ;
    END
  END i[299]
  PIN i[29]
    DIRECTION INPUT ;
    USE SIGNAL ;
    PORT
      LAYER M4 ;
        RECT  0 44.592 0.084 44.616 ;
    END
  END i[29]
  PIN i[2]
    DIRECTION INPUT ;
    USE SIGNAL ;
    PORT
      LAYER M4 ;
        RECT  0 42 0.084 42.024 ;
    END
  END i[2]
  PIN i[300]
    DIRECTION INPUT ;
    USE SIGNAL ;
    PORT
      LAYER M4 ;
        RECT  0 49.872 0.084 49.896 ;
    END
  END i[300]
  PIN i[301]
    DIRECTION INPUT ;
    USE SIGNAL ;
    PORT
      LAYER M4 ;
        RECT  0 49.968 0.084 49.992 ;
    END
  END i[301]
  PIN i[302]
    DIRECTION INPUT ;
    USE SIGNAL ;
    PORT
      LAYER M4 ;
        RECT  0 50.064 0.084 50.088 ;
    END
  END i[302]
  PIN i[303]
    DIRECTION INPUT ;
    USE SIGNAL ;
    PORT
      LAYER M4 ;
        RECT  0 50.16 0.084 50.184 ;
    END
  END i[303]
  PIN i[304]
    DIRECTION INPUT ;
    USE SIGNAL ;
    PORT
      LAYER M4 ;
        RECT  0 50.256 0.084 50.28 ;
    END
  END i[304]
  PIN i[305]
    DIRECTION INPUT ;
    USE SIGNAL ;
    PORT
      LAYER M4 ;
        RECT  0 50.352 0.084 50.376 ;
    END
  END i[305]
  PIN i[306]
    DIRECTION INPUT ;
    USE SIGNAL ;
    PORT
      LAYER M4 ;
        RECT  0 50.448 0.084 50.472 ;
    END
  END i[306]
  PIN i[307]
    DIRECTION INPUT ;
    USE SIGNAL ;
    PORT
      LAYER M4 ;
        RECT  0 50.544 0.084 50.568 ;
    END
  END i[307]
  PIN i[308]
    DIRECTION INPUT ;
    USE SIGNAL ;
    PORT
      LAYER M4 ;
        RECT  0 50.64 0.084 50.664 ;
    END
  END i[308]
  PIN i[309]
    DIRECTION INPUT ;
    USE SIGNAL ;
    PORT
      LAYER M4 ;
        RECT  0 50.736 0.084 50.76 ;
    END
  END i[309]
  PIN i[30]
    DIRECTION INPUT ;
    USE SIGNAL ;
    PORT
      LAYER M4 ;
        RECT  0 44.688 0.084 44.712 ;
    END
  END i[30]
  PIN i[310]
    DIRECTION INPUT ;
    USE SIGNAL ;
    PORT
      LAYER M4 ;
        RECT  0 50.832 0.084 50.856 ;
    END
  END i[310]
  PIN i[311]
    DIRECTION INPUT ;
    USE SIGNAL ;
    PORT
      LAYER M4 ;
        RECT  0 50.928 0.084 50.952 ;
    END
  END i[311]
  PIN i[312]
    DIRECTION INPUT ;
    USE SIGNAL ;
    PORT
      LAYER M4 ;
        RECT  0 51.024 0.084 51.048 ;
    END
  END i[312]
  PIN i[313]
    DIRECTION INPUT ;
    USE SIGNAL ;
    PORT
      LAYER M4 ;
        RECT  0 51.12 0.084 51.144 ;
    END
  END i[313]
  PIN i[314]
    DIRECTION INPUT ;
    USE SIGNAL ;
    PORT
      LAYER M4 ;
        RECT  0 51.216 0.084 51.24 ;
    END
  END i[314]
  PIN i[315]
    DIRECTION INPUT ;
    USE SIGNAL ;
    PORT
      LAYER M4 ;
        RECT  0 51.312 0.084 51.336 ;
    END
  END i[315]
  PIN i[316]
    DIRECTION INPUT ;
    USE SIGNAL ;
    PORT
      LAYER M4 ;
        RECT  0 51.408 0.084 51.432 ;
    END
  END i[316]
  PIN i[317]
    DIRECTION INPUT ;
    USE SIGNAL ;
    PORT
      LAYER M4 ;
        RECT  0 51.504 0.084 51.528 ;
    END
  END i[317]
  PIN i[318]
    DIRECTION INPUT ;
    USE SIGNAL ;
    PORT
      LAYER M4 ;
        RECT  0 51.6 0.084 51.624 ;
    END
  END i[318]
  PIN i[319]
    DIRECTION INPUT ;
    USE SIGNAL ;
    PORT
      LAYER M4 ;
        RECT  0 51.696 0.084 51.72 ;
    END
  END i[319]
  PIN i[31]
    DIRECTION INPUT ;
    USE SIGNAL ;
    PORT
      LAYER M4 ;
        RECT  0 44.784 0.084 44.808 ;
    END
  END i[31]
  PIN i[320]
    DIRECTION INPUT ;
    USE SIGNAL ;
    PORT
      LAYER M4 ;
        RECT  0 51.792 0.084 51.816 ;
    END
  END i[320]
  PIN i[321]
    DIRECTION INPUT ;
    USE SIGNAL ;
    PORT
      LAYER M4 ;
        RECT  0 51.888 0.084 51.912 ;
    END
  END i[321]
  PIN i[322]
    DIRECTION INPUT ;
    USE SIGNAL ;
    PORT
      LAYER M4 ;
        RECT  0 51.984 0.084 52.008 ;
    END
  END i[322]
  PIN i[323]
    DIRECTION INPUT ;
    USE SIGNAL ;
    PORT
      LAYER M4 ;
        RECT  0 52.08 0.084 52.104 ;
    END
  END i[323]
  PIN i[324]
    DIRECTION INPUT ;
    USE SIGNAL ;
    PORT
      LAYER M4 ;
        RECT  0 52.176 0.084 52.2 ;
    END
  END i[324]
  PIN i[325]
    DIRECTION INPUT ;
    USE SIGNAL ;
    PORT
      LAYER M4 ;
        RECT  0 52.272 0.084 52.296 ;
    END
  END i[325]
  PIN i[326]
    DIRECTION INPUT ;
    USE SIGNAL ;
    PORT
      LAYER M4 ;
        RECT  0 52.368 0.084 52.392 ;
    END
  END i[326]
  PIN i[327]
    DIRECTION INPUT ;
    USE SIGNAL ;
    PORT
      LAYER M4 ;
        RECT  0 52.464 0.084 52.488 ;
    END
  END i[327]
  PIN i[328]
    DIRECTION INPUT ;
    USE SIGNAL ;
    PORT
      LAYER M4 ;
        RECT  0 52.56 0.084 52.584 ;
    END
  END i[328]
  PIN i[329]
    DIRECTION INPUT ;
    USE SIGNAL ;
    PORT
      LAYER M4 ;
        RECT  0 52.656 0.084 52.68 ;
    END
  END i[329]
  PIN i[32]
    DIRECTION INPUT ;
    USE SIGNAL ;
    PORT
      LAYER M4 ;
        RECT  0 32.592 0.084 32.616 ;
    END
  END i[32]
  PIN i[330]
    DIRECTION INPUT ;
    USE SIGNAL ;
    PORT
      LAYER M4 ;
        RECT  0 52.752 0.084 52.776 ;
    END
  END i[330]
  PIN i[331]
    DIRECTION INPUT ;
    USE SIGNAL ;
    PORT
      LAYER M4 ;
        RECT  0 52.848 0.084 52.872 ;
    END
  END i[331]
  PIN i[332]
    DIRECTION INPUT ;
    USE SIGNAL ;
    PORT
      LAYER M4 ;
        RECT  0 52.944 0.084 52.968 ;
    END
  END i[332]
  PIN i[333]
    DIRECTION INPUT ;
    USE SIGNAL ;
    PORT
      LAYER M4 ;
        RECT  0 53.04 0.084 53.064 ;
    END
  END i[333]
  PIN i[334]
    DIRECTION INPUT ;
    USE SIGNAL ;
    PORT
      LAYER M4 ;
        RECT  0 53.136 0.084 53.16 ;
    END
  END i[334]
  PIN i[335]
    DIRECTION INPUT ;
    USE SIGNAL ;
    PORT
      LAYER M4 ;
        RECT  0 53.232 0.084 53.256 ;
    END
  END i[335]
  PIN i[336]
    DIRECTION INPUT ;
    USE SIGNAL ;
    PORT
      LAYER M4 ;
        RECT  0 53.328 0.084 53.352 ;
    END
  END i[336]
  PIN i[337]
    DIRECTION INPUT ;
    USE SIGNAL ;
    PORT
      LAYER M4 ;
        RECT  0 53.424 0.084 53.448 ;
    END
  END i[337]
  PIN i[338]
    DIRECTION INPUT ;
    USE SIGNAL ;
    PORT
      LAYER M4 ;
        RECT  0 53.52 0.084 53.544 ;
    END
  END i[338]
  PIN i[339]
    DIRECTION INPUT ;
    USE SIGNAL ;
    PORT
      LAYER M4 ;
        RECT  0 53.616 0.084 53.64 ;
    END
  END i[339]
  PIN i[33]
    DIRECTION INPUT ;
    USE SIGNAL ;
    PORT
      LAYER M4 ;
        RECT  0 32.688 0.084 32.712 ;
    END
  END i[33]
  PIN i[340]
    DIRECTION INPUT ;
    USE SIGNAL ;
    PORT
      LAYER M4 ;
        RECT  0 53.712 0.084 53.736 ;
    END
  END i[340]
  PIN i[341]
    DIRECTION INPUT ;
    USE SIGNAL ;
    PORT
      LAYER M4 ;
        RECT  0 53.808 0.084 53.832 ;
    END
  END i[341]
  PIN i[342]
    DIRECTION INPUT ;
    USE SIGNAL ;
    PORT
      LAYER M4 ;
        RECT  0 53.904 0.084 53.928 ;
    END
  END i[342]
  PIN i[343]
    DIRECTION INPUT ;
    USE SIGNAL ;
    PORT
      LAYER M4 ;
        RECT  0 54 0.084 54.024 ;
    END
  END i[343]
  PIN i[344]
    DIRECTION INPUT ;
    USE SIGNAL ;
    PORT
      LAYER M4 ;
        RECT  0 54.096 0.084 54.12 ;
    END
  END i[344]
  PIN i[345]
    DIRECTION INPUT ;
    USE SIGNAL ;
    PORT
      LAYER M4 ;
        RECT  0 54.192 0.084 54.216 ;
    END
  END i[345]
  PIN i[346]
    DIRECTION INPUT ;
    USE SIGNAL ;
    PORT
      LAYER M4 ;
        RECT  0 54.288 0.084 54.312 ;
    END
  END i[346]
  PIN i[347]
    DIRECTION INPUT ;
    USE SIGNAL ;
    PORT
      LAYER M4 ;
        RECT  0 54.384 0.084 54.408 ;
    END
  END i[347]
  PIN i[348]
    DIRECTION INPUT ;
    USE SIGNAL ;
    PORT
      LAYER M4 ;
        RECT  0 54.48 0.084 54.504 ;
    END
  END i[348]
  PIN i[349]
    DIRECTION INPUT ;
    USE SIGNAL ;
    PORT
      LAYER M4 ;
        RECT  0 54.576 0.084 54.6 ;
    END
  END i[349]
  PIN i[34]
    DIRECTION INPUT ;
    USE SIGNAL ;
    PORT
      LAYER M4 ;
        RECT  0 32.784 0.084 32.808 ;
    END
  END i[34]
  PIN i[350]
    DIRECTION INPUT ;
    USE SIGNAL ;
    PORT
      LAYER M4 ;
        RECT  0 54.672 0.084 54.696 ;
    END
  END i[350]
  PIN i[351]
    DIRECTION INPUT ;
    USE SIGNAL ;
    PORT
      LAYER M4 ;
        RECT  0 54.768 0.084 54.792 ;
    END
  END i[351]
  PIN i[352]
    DIRECTION INPUT ;
    USE SIGNAL ;
    PORT
      LAYER M4 ;
        RECT  0 61.008 0.084 61.032 ;
    END
  END i[352]
  PIN i[353]
    DIRECTION INPUT ;
    USE SIGNAL ;
    PORT
      LAYER M4 ;
        RECT  0 61.104 0.084 61.128 ;
    END
  END i[353]
  PIN i[354]
    DIRECTION INPUT ;
    USE SIGNAL ;
    PORT
      LAYER M4 ;
        RECT  0 61.2 0.084 61.224 ;
    END
  END i[354]
  PIN i[355]
    DIRECTION INPUT ;
    USE SIGNAL ;
    PORT
      LAYER M4 ;
        RECT  0 61.296 0.084 61.32 ;
    END
  END i[355]
  PIN i[356]
    DIRECTION INPUT ;
    USE SIGNAL ;
    PORT
      LAYER M4 ;
        RECT  0 61.392 0.084 61.416 ;
    END
  END i[356]
  PIN i[357]
    DIRECTION INPUT ;
    USE SIGNAL ;
    PORT
      LAYER M4 ;
        RECT  0 61.488 0.084 61.512 ;
    END
  END i[357]
  PIN i[358]
    DIRECTION INPUT ;
    USE SIGNAL ;
    PORT
      LAYER M4 ;
        RECT  0 61.584 0.084 61.608 ;
    END
  END i[358]
  PIN i[359]
    DIRECTION INPUT ;
    USE SIGNAL ;
    PORT
      LAYER M4 ;
        RECT  0 61.68 0.084 61.704 ;
    END
  END i[359]
  PIN i[35]
    DIRECTION INPUT ;
    USE SIGNAL ;
    PORT
      LAYER M4 ;
        RECT  0 32.88 0.084 32.904 ;
    END
  END i[35]
  PIN i[360]
    DIRECTION INPUT ;
    USE SIGNAL ;
    PORT
      LAYER M4 ;
        RECT  0 61.776 0.084 61.8 ;
    END
  END i[360]
  PIN i[361]
    DIRECTION INPUT ;
    USE SIGNAL ;
    PORT
      LAYER M4 ;
        RECT  0 61.872 0.084 61.896 ;
    END
  END i[361]
  PIN i[362]
    DIRECTION INPUT ;
    USE SIGNAL ;
    PORT
      LAYER M4 ;
        RECT  0 61.968 0.084 61.992 ;
    END
  END i[362]
  PIN i[363]
    DIRECTION INPUT ;
    USE SIGNAL ;
    PORT
      LAYER M4 ;
        RECT  0 62.064 0.084 62.088 ;
    END
  END i[363]
  PIN i[364]
    DIRECTION INPUT ;
    USE SIGNAL ;
    PORT
      LAYER M4 ;
        RECT  0 62.16 0.084 62.184 ;
    END
  END i[364]
  PIN i[365]
    DIRECTION INPUT ;
    USE SIGNAL ;
    PORT
      LAYER M4 ;
        RECT  0 62.256 0.084 62.28 ;
    END
  END i[365]
  PIN i[366]
    DIRECTION INPUT ;
    USE SIGNAL ;
    PORT
      LAYER M4 ;
        RECT  0 62.352 0.084 62.376 ;
    END
  END i[366]
  PIN i[367]
    DIRECTION INPUT ;
    USE SIGNAL ;
    PORT
      LAYER M4 ;
        RECT  0 62.448 0.084 62.472 ;
    END
  END i[367]
  PIN i[368]
    DIRECTION INPUT ;
    USE SIGNAL ;
    PORT
      LAYER M4 ;
        RECT  0 62.544 0.084 62.568 ;
    END
  END i[368]
  PIN i[369]
    DIRECTION INPUT ;
    USE SIGNAL ;
    PORT
      LAYER M4 ;
        RECT  0 62.64 0.084 62.664 ;
    END
  END i[369]
  PIN i[36]
    DIRECTION INPUT ;
    USE SIGNAL ;
    PORT
      LAYER M4 ;
        RECT  0 32.976 0.084 33 ;
    END
  END i[36]
  PIN i[370]
    DIRECTION INPUT ;
    USE SIGNAL ;
    PORT
      LAYER M4 ;
        RECT  0 62.736 0.084 62.76 ;
    END
  END i[370]
  PIN i[371]
    DIRECTION INPUT ;
    USE SIGNAL ;
    PORT
      LAYER M4 ;
        RECT  0 62.832 0.084 62.856 ;
    END
  END i[371]
  PIN i[372]
    DIRECTION INPUT ;
    USE SIGNAL ;
    PORT
      LAYER M4 ;
        RECT  0 62.928 0.084 62.952 ;
    END
  END i[372]
  PIN i[373]
    DIRECTION INPUT ;
    USE SIGNAL ;
    PORT
      LAYER M4 ;
        RECT  0 63.024 0.084 63.048 ;
    END
  END i[373]
  PIN i[374]
    DIRECTION INPUT ;
    USE SIGNAL ;
    PORT
      LAYER M4 ;
        RECT  0 63.12 0.084 63.144 ;
    END
  END i[374]
  PIN i[375]
    DIRECTION INPUT ;
    USE SIGNAL ;
    PORT
      LAYER M4 ;
        RECT  0 63.216 0.084 63.24 ;
    END
  END i[375]
  PIN i[376]
    DIRECTION INPUT ;
    USE SIGNAL ;
    PORT
      LAYER M4 ;
        RECT  0 63.312 0.084 63.336 ;
    END
  END i[376]
  PIN i[377]
    DIRECTION INPUT ;
    USE SIGNAL ;
    PORT
      LAYER M4 ;
        RECT  0 63.408 0.084 63.432 ;
    END
  END i[377]
  PIN i[378]
    DIRECTION INPUT ;
    USE SIGNAL ;
    PORT
      LAYER M4 ;
        RECT  0 63.504 0.084 63.528 ;
    END
  END i[378]
  PIN i[379]
    DIRECTION INPUT ;
    USE SIGNAL ;
    PORT
      LAYER M4 ;
        RECT  0 63.6 0.084 63.624 ;
    END
  END i[379]
  PIN i[37]
    DIRECTION INPUT ;
    USE SIGNAL ;
    PORT
      LAYER M4 ;
        RECT  0 33.072 0.084 33.096 ;
    END
  END i[37]
  PIN i[380]
    DIRECTION INPUT ;
    USE SIGNAL ;
    PORT
      LAYER M4 ;
        RECT  0 63.696 0.084 63.72 ;
    END
  END i[380]
  PIN i[381]
    DIRECTION INPUT ;
    USE SIGNAL ;
    PORT
      LAYER M4 ;
        RECT  0 63.792 0.084 63.816 ;
    END
  END i[381]
  PIN i[382]
    DIRECTION INPUT ;
    USE SIGNAL ;
    PORT
      LAYER M4 ;
        RECT  0 63.888 0.084 63.912 ;
    END
  END i[382]
  PIN i[383]
    DIRECTION INPUT ;
    USE SIGNAL ;
    PORT
      LAYER M4 ;
        RECT  0 63.984 0.084 64.008 ;
    END
  END i[383]
  PIN i[384]
    DIRECTION INPUT ;
    USE SIGNAL ;
    PORT
      LAYER M4 ;
        RECT  0 54.864 0.084 54.888 ;
    END
  END i[384]
  PIN i[385]
    DIRECTION INPUT ;
    USE SIGNAL ;
    PORT
      LAYER M4 ;
        RECT  0 54.96 0.084 54.984 ;
    END
  END i[385]
  PIN i[386]
    DIRECTION INPUT ;
    USE SIGNAL ;
    PORT
      LAYER M4 ;
        RECT  0 55.056 0.084 55.08 ;
    END
  END i[386]
  PIN i[387]
    DIRECTION INPUT ;
    USE SIGNAL ;
    PORT
      LAYER M4 ;
        RECT  0 55.152 0.084 55.176 ;
    END
  END i[387]
  PIN i[388]
    DIRECTION INPUT ;
    USE SIGNAL ;
    PORT
      LAYER M4 ;
        RECT  0 55.248 0.084 55.272 ;
    END
  END i[388]
  PIN i[389]
    DIRECTION INPUT ;
    USE SIGNAL ;
    PORT
      LAYER M4 ;
        RECT  0 55.344 0.084 55.368 ;
    END
  END i[389]
  PIN i[38]
    DIRECTION INPUT ;
    USE SIGNAL ;
    PORT
      LAYER M4 ;
        RECT  0 33.168 0.084 33.192 ;
    END
  END i[38]
  PIN i[390]
    DIRECTION INPUT ;
    USE SIGNAL ;
    PORT
      LAYER M4 ;
        RECT  0 55.44 0.084 55.464 ;
    END
  END i[390]
  PIN i[391]
    DIRECTION INPUT ;
    USE SIGNAL ;
    PORT
      LAYER M4 ;
        RECT  0 55.536 0.084 55.56 ;
    END
  END i[391]
  PIN i[392]
    DIRECTION INPUT ;
    USE SIGNAL ;
    PORT
      LAYER M4 ;
        RECT  0 55.632 0.084 55.656 ;
    END
  END i[392]
  PIN i[393]
    DIRECTION INPUT ;
    USE SIGNAL ;
    PORT
      LAYER M4 ;
        RECT  0 55.728 0.084 55.752 ;
    END
  END i[393]
  PIN i[394]
    DIRECTION INPUT ;
    USE SIGNAL ;
    PORT
      LAYER M4 ;
        RECT  0 55.824 0.084 55.848 ;
    END
  END i[394]
  PIN i[395]
    DIRECTION INPUT ;
    USE SIGNAL ;
    PORT
      LAYER M4 ;
        RECT  0 55.92 0.084 55.944 ;
    END
  END i[395]
  PIN i[396]
    DIRECTION INPUT ;
    USE SIGNAL ;
    PORT
      LAYER M4 ;
        RECT  0 56.016 0.084 56.04 ;
    END
  END i[396]
  PIN i[397]
    DIRECTION INPUT ;
    USE SIGNAL ;
    PORT
      LAYER M4 ;
        RECT  0 56.112 0.084 56.136 ;
    END
  END i[397]
  PIN i[398]
    DIRECTION INPUT ;
    USE SIGNAL ;
    PORT
      LAYER M4 ;
        RECT  0 56.208 0.084 56.232 ;
    END
  END i[398]
  PIN i[399]
    DIRECTION INPUT ;
    USE SIGNAL ;
    PORT
      LAYER M4 ;
        RECT  0 56.304 0.084 56.328 ;
    END
  END i[399]
  PIN i[39]
    DIRECTION INPUT ;
    USE SIGNAL ;
    PORT
      LAYER M4 ;
        RECT  0 33.264 0.084 33.288 ;
    END
  END i[39]
  PIN i[3]
    DIRECTION INPUT ;
    USE SIGNAL ;
    PORT
      LAYER M4 ;
        RECT  0 42.096 0.084 42.12 ;
    END
  END i[3]
  PIN i[400]
    DIRECTION INPUT ;
    USE SIGNAL ;
    PORT
      LAYER M4 ;
        RECT  0 56.4 0.084 56.424 ;
    END
  END i[400]
  PIN i[401]
    DIRECTION INPUT ;
    USE SIGNAL ;
    PORT
      LAYER M4 ;
        RECT  0 56.496 0.084 56.52 ;
    END
  END i[401]
  PIN i[402]
    DIRECTION INPUT ;
    USE SIGNAL ;
    PORT
      LAYER M4 ;
        RECT  0 56.592 0.084 56.616 ;
    END
  END i[402]
  PIN i[403]
    DIRECTION INPUT ;
    USE SIGNAL ;
    PORT
      LAYER M4 ;
        RECT  0 56.688 0.084 56.712 ;
    END
  END i[403]
  PIN i[404]
    DIRECTION INPUT ;
    USE SIGNAL ;
    PORT
      LAYER M4 ;
        RECT  0 56.784 0.084 56.808 ;
    END
  END i[404]
  PIN i[405]
    DIRECTION INPUT ;
    USE SIGNAL ;
    PORT
      LAYER M4 ;
        RECT  0 56.88 0.084 56.904 ;
    END
  END i[405]
  PIN i[406]
    DIRECTION INPUT ;
    USE SIGNAL ;
    PORT
      LAYER M4 ;
        RECT  0 56.976 0.084 57 ;
    END
  END i[406]
  PIN i[407]
    DIRECTION INPUT ;
    USE SIGNAL ;
    PORT
      LAYER M4 ;
        RECT  0 57.072 0.084 57.096 ;
    END
  END i[407]
  PIN i[408]
    DIRECTION INPUT ;
    USE SIGNAL ;
    PORT
      LAYER M4 ;
        RECT  0 57.168 0.084 57.192 ;
    END
  END i[408]
  PIN i[409]
    DIRECTION INPUT ;
    USE SIGNAL ;
    PORT
      LAYER M4 ;
        RECT  0 57.264 0.084 57.288 ;
    END
  END i[409]
  PIN i[40]
    DIRECTION INPUT ;
    USE SIGNAL ;
    PORT
      LAYER M4 ;
        RECT  0 33.36 0.084 33.384 ;
    END
  END i[40]
  PIN i[410]
    DIRECTION INPUT ;
    USE SIGNAL ;
    PORT
      LAYER M4 ;
        RECT  0 57.36 0.084 57.384 ;
    END
  END i[410]
  PIN i[411]
    DIRECTION INPUT ;
    USE SIGNAL ;
    PORT
      LAYER M4 ;
        RECT  0 57.456 0.084 57.48 ;
    END
  END i[411]
  PIN i[412]
    DIRECTION INPUT ;
    USE SIGNAL ;
    PORT
      LAYER M4 ;
        RECT  0 57.552 0.084 57.576 ;
    END
  END i[412]
  PIN i[413]
    DIRECTION INPUT ;
    USE SIGNAL ;
    PORT
      LAYER M4 ;
        RECT  0 57.648 0.084 57.672 ;
    END
  END i[413]
  PIN i[414]
    DIRECTION INPUT ;
    USE SIGNAL ;
    PORT
      LAYER M4 ;
        RECT  0 57.744 0.084 57.768 ;
    END
  END i[414]
  PIN i[415]
    DIRECTION INPUT ;
    USE SIGNAL ;
    PORT
      LAYER M4 ;
        RECT  0 57.84 0.084 57.864 ;
    END
  END i[415]
  PIN i[416]
    DIRECTION INPUT ;
    USE SIGNAL ;
    PORT
      LAYER M4 ;
        RECT  0 57.936 0.084 57.96 ;
    END
  END i[416]
  PIN i[417]
    DIRECTION INPUT ;
    USE SIGNAL ;
    PORT
      LAYER M4 ;
        RECT  0 58.032 0.084 58.056 ;
    END
  END i[417]
  PIN i[418]
    DIRECTION INPUT ;
    USE SIGNAL ;
    PORT
      LAYER M4 ;
        RECT  0 58.128 0.084 58.152 ;
    END
  END i[418]
  PIN i[419]
    DIRECTION INPUT ;
    USE SIGNAL ;
    PORT
      LAYER M4 ;
        RECT  0 58.224 0.084 58.248 ;
    END
  END i[419]
  PIN i[41]
    DIRECTION INPUT ;
    USE SIGNAL ;
    PORT
      LAYER M4 ;
        RECT  0 33.456 0.084 33.48 ;
    END
  END i[41]
  PIN i[420]
    DIRECTION INPUT ;
    USE SIGNAL ;
    PORT
      LAYER M4 ;
        RECT  0 58.32 0.084 58.344 ;
    END
  END i[420]
  PIN i[421]
    DIRECTION INPUT ;
    USE SIGNAL ;
    PORT
      LAYER M4 ;
        RECT  0 58.416 0.084 58.44 ;
    END
  END i[421]
  PIN i[422]
    DIRECTION INPUT ;
    USE SIGNAL ;
    PORT
      LAYER M4 ;
        RECT  0 58.512 0.084 58.536 ;
    END
  END i[422]
  PIN i[423]
    DIRECTION INPUT ;
    USE SIGNAL ;
    PORT
      LAYER M4 ;
        RECT  0 58.608 0.084 58.632 ;
    END
  END i[423]
  PIN i[424]
    DIRECTION INPUT ;
    USE SIGNAL ;
    PORT
      LAYER M4 ;
        RECT  0 58.704 0.084 58.728 ;
    END
  END i[424]
  PIN i[425]
    DIRECTION INPUT ;
    USE SIGNAL ;
    PORT
      LAYER M4 ;
        RECT  0 58.8 0.084 58.824 ;
    END
  END i[425]
  PIN i[426]
    DIRECTION INPUT ;
    USE SIGNAL ;
    PORT
      LAYER M4 ;
        RECT  0 58.896 0.084 58.92 ;
    END
  END i[426]
  PIN i[427]
    DIRECTION INPUT ;
    USE SIGNAL ;
    PORT
      LAYER M4 ;
        RECT  0 58.992 0.084 59.016 ;
    END
  END i[427]
  PIN i[428]
    DIRECTION INPUT ;
    USE SIGNAL ;
    PORT
      LAYER M4 ;
        RECT  0 59.088 0.084 59.112 ;
    END
  END i[428]
  PIN i[429]
    DIRECTION INPUT ;
    USE SIGNAL ;
    PORT
      LAYER M4 ;
        RECT  0 59.184 0.084 59.208 ;
    END
  END i[429]
  PIN i[42]
    DIRECTION INPUT ;
    USE SIGNAL ;
    PORT
      LAYER M4 ;
        RECT  0 33.552 0.084 33.576 ;
    END
  END i[42]
  PIN i[430]
    DIRECTION INPUT ;
    USE SIGNAL ;
    PORT
      LAYER M4 ;
        RECT  0 59.28 0.084 59.304 ;
    END
  END i[430]
  PIN i[431]
    DIRECTION INPUT ;
    USE SIGNAL ;
    PORT
      LAYER M4 ;
        RECT  0 59.376 0.084 59.4 ;
    END
  END i[431]
  PIN i[432]
    DIRECTION INPUT ;
    USE SIGNAL ;
    PORT
      LAYER M4 ;
        RECT  0 59.472 0.084 59.496 ;
    END
  END i[432]
  PIN i[433]
    DIRECTION INPUT ;
    USE SIGNAL ;
    PORT
      LAYER M4 ;
        RECT  0 59.568 0.084 59.592 ;
    END
  END i[433]
  PIN i[434]
    DIRECTION INPUT ;
    USE SIGNAL ;
    PORT
      LAYER M4 ;
        RECT  0 59.664 0.084 59.688 ;
    END
  END i[434]
  PIN i[435]
    DIRECTION INPUT ;
    USE SIGNAL ;
    PORT
      LAYER M4 ;
        RECT  0 59.76 0.084 59.784 ;
    END
  END i[435]
  PIN i[436]
    DIRECTION INPUT ;
    USE SIGNAL ;
    PORT
      LAYER M4 ;
        RECT  0 59.856 0.084 59.88 ;
    END
  END i[436]
  PIN i[437]
    DIRECTION INPUT ;
    USE SIGNAL ;
    PORT
      LAYER M4 ;
        RECT  0 59.952 0.084 59.976 ;
    END
  END i[437]
  PIN i[438]
    DIRECTION INPUT ;
    USE SIGNAL ;
    PORT
      LAYER M4 ;
        RECT  0 60.048 0.084 60.072 ;
    END
  END i[438]
  PIN i[439]
    DIRECTION INPUT ;
    USE SIGNAL ;
    PORT
      LAYER M4 ;
        RECT  0 60.144 0.084 60.168 ;
    END
  END i[439]
  PIN i[43]
    DIRECTION INPUT ;
    USE SIGNAL ;
    PORT
      LAYER M4 ;
        RECT  0 33.648 0.084 33.672 ;
    END
  END i[43]
  PIN i[440]
    DIRECTION INPUT ;
    USE SIGNAL ;
    PORT
      LAYER M4 ;
        RECT  0 60.24 0.084 60.264 ;
    END
  END i[440]
  PIN i[441]
    DIRECTION INPUT ;
    USE SIGNAL ;
    PORT
      LAYER M4 ;
        RECT  0 60.336 0.084 60.36 ;
    END
  END i[441]
  PIN i[442]
    DIRECTION INPUT ;
    USE SIGNAL ;
    PORT
      LAYER M4 ;
        RECT  0 60.432 0.084 60.456 ;
    END
  END i[442]
  PIN i[443]
    DIRECTION INPUT ;
    USE SIGNAL ;
    PORT
      LAYER M4 ;
        RECT  0 60.528 0.084 60.552 ;
    END
  END i[443]
  PIN i[444]
    DIRECTION INPUT ;
    USE SIGNAL ;
    PORT
      LAYER M4 ;
        RECT  0 60.624 0.084 60.648 ;
    END
  END i[444]
  PIN i[445]
    DIRECTION INPUT ;
    USE SIGNAL ;
    PORT
      LAYER M4 ;
        RECT  0 60.72 0.084 60.744 ;
    END
  END i[445]
  PIN i[446]
    DIRECTION INPUT ;
    USE SIGNAL ;
    PORT
      LAYER M4 ;
        RECT  0 60.816 0.084 60.84 ;
    END
  END i[446]
  PIN i[447]
    DIRECTION INPUT ;
    USE SIGNAL ;
    PORT
      LAYER M4 ;
        RECT  0 60.912 0.084 60.936 ;
    END
  END i[447]
  PIN i[448]
    DIRECTION INPUT ;
    USE SIGNAL ;
    PORT
      LAYER M4 ;
        RECT  0 19.536 0.084 19.56 ;
    END
  END i[448]
  PIN i[449]
    DIRECTION INPUT ;
    USE SIGNAL ;
    PORT
      LAYER M4 ;
        RECT  0 19.632 0.084 19.656 ;
    END
  END i[449]
  PIN i[44]
    DIRECTION INPUT ;
    USE SIGNAL ;
    PORT
      LAYER M4 ;
        RECT  0 33.744 0.084 33.768 ;
    END
  END i[44]
  PIN i[450]
    DIRECTION INPUT ;
    USE SIGNAL ;
    PORT
      LAYER M4 ;
        RECT  0 19.728 0.084 19.752 ;
    END
  END i[450]
  PIN i[451]
    DIRECTION INPUT ;
    USE SIGNAL ;
    PORT
      LAYER M4 ;
        RECT  0 19.824 0.084 19.848 ;
    END
  END i[451]
  PIN i[452]
    DIRECTION INPUT ;
    USE SIGNAL ;
    PORT
      LAYER M4 ;
        RECT  0 19.92 0.084 19.944 ;
    END
  END i[452]
  PIN i[453]
    DIRECTION INPUT ;
    USE SIGNAL ;
    PORT
      LAYER M4 ;
        RECT  0 20.016 0.084 20.04 ;
    END
  END i[453]
  PIN i[454]
    DIRECTION INPUT ;
    USE SIGNAL ;
    PORT
      LAYER M4 ;
        RECT  0 20.112 0.084 20.136 ;
    END
  END i[454]
  PIN i[455]
    DIRECTION INPUT ;
    USE SIGNAL ;
    PORT
      LAYER M4 ;
        RECT  0 20.208 0.084 20.232 ;
    END
  END i[455]
  PIN i[456]
    DIRECTION INPUT ;
    USE SIGNAL ;
    PORT
      LAYER M4 ;
        RECT  0 20.304 0.084 20.328 ;
    END
  END i[456]
  PIN i[457]
    DIRECTION INPUT ;
    USE SIGNAL ;
    PORT
      LAYER M4 ;
        RECT  0 20.4 0.084 20.424 ;
    END
  END i[457]
  PIN i[458]
    DIRECTION INPUT ;
    USE SIGNAL ;
    PORT
      LAYER M4 ;
        RECT  0 20.496 0.084 20.52 ;
    END
  END i[458]
  PIN i[459]
    DIRECTION INPUT ;
    USE SIGNAL ;
    PORT
      LAYER M4 ;
        RECT  0 20.592 0.084 20.616 ;
    END
  END i[459]
  PIN i[45]
    DIRECTION INPUT ;
    USE SIGNAL ;
    PORT
      LAYER M4 ;
        RECT  0 33.84 0.084 33.864 ;
    END
  END i[45]
  PIN i[460]
    DIRECTION INPUT ;
    USE SIGNAL ;
    PORT
      LAYER M4 ;
        RECT  0 20.688 0.084 20.712 ;
    END
  END i[460]
  PIN i[461]
    DIRECTION INPUT ;
    USE SIGNAL ;
    PORT
      LAYER M4 ;
        RECT  0 20.784 0.084 20.808 ;
    END
  END i[461]
  PIN i[462]
    DIRECTION INPUT ;
    USE SIGNAL ;
    PORT
      LAYER M4 ;
        RECT  0 20.88 0.084 20.904 ;
    END
  END i[462]
  PIN i[463]
    DIRECTION INPUT ;
    USE SIGNAL ;
    PORT
      LAYER M4 ;
        RECT  0 20.976 0.084 21 ;
    END
  END i[463]
  PIN i[464]
    DIRECTION INPUT ;
    USE SIGNAL ;
    PORT
      LAYER M4 ;
        RECT  0 21.072 0.084 21.096 ;
    END
  END i[464]
  PIN i[465]
    DIRECTION INPUT ;
    USE SIGNAL ;
    PORT
      LAYER M4 ;
        RECT  0 21.168 0.084 21.192 ;
    END
  END i[465]
  PIN i[466]
    DIRECTION INPUT ;
    USE SIGNAL ;
    PORT
      LAYER M4 ;
        RECT  0 21.264 0.084 21.288 ;
    END
  END i[466]
  PIN i[467]
    DIRECTION INPUT ;
    USE SIGNAL ;
    PORT
      LAYER M4 ;
        RECT  0 21.36 0.084 21.384 ;
    END
  END i[467]
  PIN i[468]
    DIRECTION INPUT ;
    USE SIGNAL ;
    PORT
      LAYER M4 ;
        RECT  0 21.456 0.084 21.48 ;
    END
  END i[468]
  PIN i[469]
    DIRECTION INPUT ;
    USE SIGNAL ;
    PORT
      LAYER M4 ;
        RECT  0 21.552 0.084 21.576 ;
    END
  END i[469]
  PIN i[46]
    DIRECTION INPUT ;
    USE SIGNAL ;
    PORT
      LAYER M4 ;
        RECT  0 33.936 0.084 33.96 ;
    END
  END i[46]
  PIN i[470]
    DIRECTION INPUT ;
    USE SIGNAL ;
    PORT
      LAYER M4 ;
        RECT  0 21.648 0.084 21.672 ;
    END
  END i[470]
  PIN i[471]
    DIRECTION INPUT ;
    USE SIGNAL ;
    PORT
      LAYER M4 ;
        RECT  0 21.744 0.084 21.768 ;
    END
  END i[471]
  PIN i[472]
    DIRECTION INPUT ;
    USE SIGNAL ;
    PORT
      LAYER M4 ;
        RECT  0 21.84 0.084 21.864 ;
    END
  END i[472]
  PIN i[473]
    DIRECTION INPUT ;
    USE SIGNAL ;
    PORT
      LAYER M4 ;
        RECT  0 21.936 0.084 21.96 ;
    END
  END i[473]
  PIN i[474]
    DIRECTION INPUT ;
    USE SIGNAL ;
    PORT
      LAYER M4 ;
        RECT  0 22.032 0.084 22.056 ;
    END
  END i[474]
  PIN i[475]
    DIRECTION INPUT ;
    USE SIGNAL ;
    PORT
      LAYER M4 ;
        RECT  0 22.128 0.084 22.152 ;
    END
  END i[475]
  PIN i[476]
    DIRECTION INPUT ;
    USE SIGNAL ;
    PORT
      LAYER M4 ;
        RECT  0 22.224 0.084 22.248 ;
    END
  END i[476]
  PIN i[477]
    DIRECTION INPUT ;
    USE SIGNAL ;
    PORT
      LAYER M4 ;
        RECT  0 22.32 0.084 22.344 ;
    END
  END i[477]
  PIN i[478]
    DIRECTION INPUT ;
    USE SIGNAL ;
    PORT
      LAYER M4 ;
        RECT  0 22.416 0.084 22.44 ;
    END
  END i[478]
  PIN i[479]
    DIRECTION INPUT ;
    USE SIGNAL ;
    PORT
      LAYER M4 ;
        RECT  0 22.512 0.084 22.536 ;
    END
  END i[479]
  PIN i[47]
    DIRECTION INPUT ;
    USE SIGNAL ;
    PORT
      LAYER M4 ;
        RECT  0 34.032 0.084 34.056 ;
    END
  END i[47]
  PIN i[480]
    DIRECTION INPUT ;
    USE SIGNAL ;
    PORT
      LAYER M4 ;
        RECT  0 22.608 0.084 22.632 ;
    END
  END i[480]
  PIN i[481]
    DIRECTION INPUT ;
    USE SIGNAL ;
    PORT
      LAYER M4 ;
        RECT  0 22.704 0.084 22.728 ;
    END
  END i[481]
  PIN i[482]
    DIRECTION INPUT ;
    USE SIGNAL ;
    PORT
      LAYER M4 ;
        RECT  0 22.8 0.084 22.824 ;
    END
  END i[482]
  PIN i[483]
    DIRECTION INPUT ;
    USE SIGNAL ;
    PORT
      LAYER M4 ;
        RECT  0 22.896 0.084 22.92 ;
    END
  END i[483]
  PIN i[484]
    DIRECTION INPUT ;
    USE SIGNAL ;
    PORT
      LAYER M4 ;
        RECT  0 22.992 0.084 23.016 ;
    END
  END i[484]
  PIN i[485]
    DIRECTION INPUT ;
    USE SIGNAL ;
    PORT
      LAYER M4 ;
        RECT  0 23.088 0.084 23.112 ;
    END
  END i[485]
  PIN i[486]
    DIRECTION INPUT ;
    USE SIGNAL ;
    PORT
      LAYER M4 ;
        RECT  0 23.184 0.084 23.208 ;
    END
  END i[486]
  PIN i[487]
    DIRECTION INPUT ;
    USE SIGNAL ;
    PORT
      LAYER M4 ;
        RECT  0 23.28 0.084 23.304 ;
    END
  END i[487]
  PIN i[488]
    DIRECTION INPUT ;
    USE SIGNAL ;
    PORT
      LAYER M4 ;
        RECT  0 23.376 0.084 23.4 ;
    END
  END i[488]
  PIN i[489]
    DIRECTION INPUT ;
    USE SIGNAL ;
    PORT
      LAYER M4 ;
        RECT  0 23.472 0.084 23.496 ;
    END
  END i[489]
  PIN i[48]
    DIRECTION INPUT ;
    USE SIGNAL ;
    PORT
      LAYER M4 ;
        RECT  0 34.128 0.084 34.152 ;
    END
  END i[48]
  PIN i[490]
    DIRECTION INPUT ;
    USE SIGNAL ;
    PORT
      LAYER M4 ;
        RECT  0 23.568 0.084 23.592 ;
    END
  END i[490]
  PIN i[491]
    DIRECTION INPUT ;
    USE SIGNAL ;
    PORT
      LAYER M4 ;
        RECT  0 23.664 0.084 23.688 ;
    END
  END i[491]
  PIN i[492]
    DIRECTION INPUT ;
    USE SIGNAL ;
    PORT
      LAYER M4 ;
        RECT  0 23.76 0.084 23.784 ;
    END
  END i[492]
  PIN i[493]
    DIRECTION INPUT ;
    USE SIGNAL ;
    PORT
      LAYER M4 ;
        RECT  0 23.856 0.084 23.88 ;
    END
  END i[493]
  PIN i[494]
    DIRECTION INPUT ;
    USE SIGNAL ;
    PORT
      LAYER M4 ;
        RECT  0 23.952 0.084 23.976 ;
    END
  END i[494]
  PIN i[495]
    DIRECTION INPUT ;
    USE SIGNAL ;
    PORT
      LAYER M4 ;
        RECT  0 24.048 0.084 24.072 ;
    END
  END i[495]
  PIN i[496]
    DIRECTION INPUT ;
    USE SIGNAL ;
    PORT
      LAYER M4 ;
        RECT  0 24.144 0.084 24.168 ;
    END
  END i[496]
  PIN i[497]
    DIRECTION INPUT ;
    USE SIGNAL ;
    PORT
      LAYER M4 ;
        RECT  0 24.24 0.084 24.264 ;
    END
  END i[497]
  PIN i[498]
    DIRECTION INPUT ;
    USE SIGNAL ;
    PORT
      LAYER M4 ;
        RECT  0 24.336 0.084 24.36 ;
    END
  END i[498]
  PIN i[499]
    DIRECTION INPUT ;
    USE SIGNAL ;
    PORT
      LAYER M4 ;
        RECT  0 24.432 0.084 24.456 ;
    END
  END i[499]
  PIN i[49]
    DIRECTION INPUT ;
    USE SIGNAL ;
    PORT
      LAYER M4 ;
        RECT  0 34.224 0.084 34.248 ;
    END
  END i[49]
  PIN i[4]
    DIRECTION INPUT ;
    USE SIGNAL ;
    PORT
      LAYER M4 ;
        RECT  0 42.192 0.084 42.216 ;
    END
  END i[4]
  PIN i[500]
    DIRECTION INPUT ;
    USE SIGNAL ;
    PORT
      LAYER M4 ;
        RECT  0 24.528 0.084 24.552 ;
    END
  END i[500]
  PIN i[501]
    DIRECTION INPUT ;
    USE SIGNAL ;
    PORT
      LAYER M4 ;
        RECT  0 24.624 0.084 24.648 ;
    END
  END i[501]
  PIN i[502]
    DIRECTION INPUT ;
    USE SIGNAL ;
    PORT
      LAYER M4 ;
        RECT  0 24.72 0.084 24.744 ;
    END
  END i[502]
  PIN i[503]
    DIRECTION INPUT ;
    USE SIGNAL ;
    PORT
      LAYER M4 ;
        RECT  0 24.816 0.084 24.84 ;
    END
  END i[503]
  PIN i[504]
    DIRECTION INPUT ;
    USE SIGNAL ;
    PORT
      LAYER M4 ;
        RECT  0 24.912 0.084 24.936 ;
    END
  END i[504]
  PIN i[505]
    DIRECTION INPUT ;
    USE SIGNAL ;
    PORT
      LAYER M4 ;
        RECT  0 25.008 0.084 25.032 ;
    END
  END i[505]
  PIN i[506]
    DIRECTION INPUT ;
    USE SIGNAL ;
    PORT
      LAYER M4 ;
        RECT  0 25.104 0.084 25.128 ;
    END
  END i[506]
  PIN i[507]
    DIRECTION INPUT ;
    USE SIGNAL ;
    PORT
      LAYER M4 ;
        RECT  0 25.2 0.084 25.224 ;
    END
  END i[507]
  PIN i[508]
    DIRECTION INPUT ;
    USE SIGNAL ;
    PORT
      LAYER M4 ;
        RECT  0 25.296 0.084 25.32 ;
    END
  END i[508]
  PIN i[509]
    DIRECTION INPUT ;
    USE SIGNAL ;
    PORT
      LAYER M4 ;
        RECT  0 25.392 0.084 25.416 ;
    END
  END i[509]
  PIN i[50]
    DIRECTION INPUT ;
    USE SIGNAL ;
    PORT
      LAYER M4 ;
        RECT  0 34.32 0.084 34.344 ;
    END
  END i[50]
  PIN i[510]
    DIRECTION INPUT ;
    USE SIGNAL ;
    PORT
      LAYER M4 ;
        RECT  0 25.488 0.084 25.512 ;
    END
  END i[510]
  PIN i[511]
    DIRECTION INPUT ;
    USE SIGNAL ;
    PORT
      LAYER M4 ;
        RECT  0 25.584 0.084 25.608 ;
    END
  END i[511]
  PIN i[512]
    DIRECTION INPUT ;
    USE SIGNAL ;
    PORT
      LAYER M4 ;
        RECT  0 16.464 0.084 16.488 ;
    END
  END i[512]
  PIN i[513]
    DIRECTION INPUT ;
    USE SIGNAL ;
    PORT
      LAYER M4 ;
        RECT  0 16.56 0.084 16.584 ;
    END
  END i[513]
  PIN i[514]
    DIRECTION INPUT ;
    USE SIGNAL ;
    PORT
      LAYER M4 ;
        RECT  0 16.656 0.084 16.68 ;
    END
  END i[514]
  PIN i[515]
    DIRECTION INPUT ;
    USE SIGNAL ;
    PORT
      LAYER M4 ;
        RECT  0 16.752 0.084 16.776 ;
    END
  END i[515]
  PIN i[516]
    DIRECTION INPUT ;
    USE SIGNAL ;
    PORT
      LAYER M4 ;
        RECT  0 16.848 0.084 16.872 ;
    END
  END i[516]
  PIN i[517]
    DIRECTION INPUT ;
    USE SIGNAL ;
    PORT
      LAYER M4 ;
        RECT  0 16.944 0.084 16.968 ;
    END
  END i[517]
  PIN i[518]
    DIRECTION INPUT ;
    USE SIGNAL ;
    PORT
      LAYER M4 ;
        RECT  0 17.04 0.084 17.064 ;
    END
  END i[518]
  PIN i[519]
    DIRECTION INPUT ;
    USE SIGNAL ;
    PORT
      LAYER M4 ;
        RECT  0 17.136 0.084 17.16 ;
    END
  END i[519]
  PIN i[51]
    DIRECTION INPUT ;
    USE SIGNAL ;
    PORT
      LAYER M4 ;
        RECT  0 34.416 0.084 34.44 ;
    END
  END i[51]
  PIN i[520]
    DIRECTION INPUT ;
    USE SIGNAL ;
    PORT
      LAYER M4 ;
        RECT  0 17.232 0.084 17.256 ;
    END
  END i[520]
  PIN i[521]
    DIRECTION INPUT ;
    USE SIGNAL ;
    PORT
      LAYER M4 ;
        RECT  0 17.328 0.084 17.352 ;
    END
  END i[521]
  PIN i[522]
    DIRECTION INPUT ;
    USE SIGNAL ;
    PORT
      LAYER M4 ;
        RECT  0 17.424 0.084 17.448 ;
    END
  END i[522]
  PIN i[523]
    DIRECTION INPUT ;
    USE SIGNAL ;
    PORT
      LAYER M4 ;
        RECT  0 17.52 0.084 17.544 ;
    END
  END i[523]
  PIN i[524]
    DIRECTION INPUT ;
    USE SIGNAL ;
    PORT
      LAYER M4 ;
        RECT  0 17.616 0.084 17.64 ;
    END
  END i[524]
  PIN i[525]
    DIRECTION INPUT ;
    USE SIGNAL ;
    PORT
      LAYER M4 ;
        RECT  0 17.712 0.084 17.736 ;
    END
  END i[525]
  PIN i[526]
    DIRECTION INPUT ;
    USE SIGNAL ;
    PORT
      LAYER M4 ;
        RECT  0 17.808 0.084 17.832 ;
    END
  END i[526]
  PIN i[527]
    DIRECTION INPUT ;
    USE SIGNAL ;
    PORT
      LAYER M4 ;
        RECT  0 17.904 0.084 17.928 ;
    END
  END i[527]
  PIN i[528]
    DIRECTION INPUT ;
    USE SIGNAL ;
    PORT
      LAYER M4 ;
        RECT  0 18 0.084 18.024 ;
    END
  END i[528]
  PIN i[529]
    DIRECTION INPUT ;
    USE SIGNAL ;
    PORT
      LAYER M4 ;
        RECT  0 18.096 0.084 18.12 ;
    END
  END i[529]
  PIN i[52]
    DIRECTION INPUT ;
    USE SIGNAL ;
    PORT
      LAYER M4 ;
        RECT  0 34.512 0.084 34.536 ;
    END
  END i[52]
  PIN i[530]
    DIRECTION INPUT ;
    USE SIGNAL ;
    PORT
      LAYER M4 ;
        RECT  0 18.192 0.084 18.216 ;
    END
  END i[530]
  PIN i[531]
    DIRECTION INPUT ;
    USE SIGNAL ;
    PORT
      LAYER M4 ;
        RECT  0 18.288 0.084 18.312 ;
    END
  END i[531]
  PIN i[532]
    DIRECTION INPUT ;
    USE SIGNAL ;
    PORT
      LAYER M4 ;
        RECT  0 18.384 0.084 18.408 ;
    END
  END i[532]
  PIN i[533]
    DIRECTION INPUT ;
    USE SIGNAL ;
    PORT
      LAYER M4 ;
        RECT  0 18.48 0.084 18.504 ;
    END
  END i[533]
  PIN i[534]
    DIRECTION INPUT ;
    USE SIGNAL ;
    PORT
      LAYER M4 ;
        RECT  0 18.576 0.084 18.6 ;
    END
  END i[534]
  PIN i[535]
    DIRECTION INPUT ;
    USE SIGNAL ;
    PORT
      LAYER M4 ;
        RECT  0 18.672 0.084 18.696 ;
    END
  END i[535]
  PIN i[536]
    DIRECTION INPUT ;
    USE SIGNAL ;
    PORT
      LAYER M4 ;
        RECT  0 18.768 0.084 18.792 ;
    END
  END i[536]
  PIN i[537]
    DIRECTION INPUT ;
    USE SIGNAL ;
    PORT
      LAYER M4 ;
        RECT  0 18.864 0.084 18.888 ;
    END
  END i[537]
  PIN i[538]
    DIRECTION INPUT ;
    USE SIGNAL ;
    PORT
      LAYER M4 ;
        RECT  0 18.96 0.084 18.984 ;
    END
  END i[538]
  PIN i[539]
    DIRECTION INPUT ;
    USE SIGNAL ;
    PORT
      LAYER M4 ;
        RECT  0 19.056 0.084 19.08 ;
    END
  END i[539]
  PIN i[53]
    DIRECTION INPUT ;
    USE SIGNAL ;
    PORT
      LAYER M4 ;
        RECT  0 34.608 0.084 34.632 ;
    END
  END i[53]
  PIN i[540]
    DIRECTION INPUT ;
    USE SIGNAL ;
    PORT
      LAYER M4 ;
        RECT  0 19.152 0.084 19.176 ;
    END
  END i[540]
  PIN i[541]
    DIRECTION INPUT ;
    USE SIGNAL ;
    PORT
      LAYER M4 ;
        RECT  0 19.248 0.084 19.272 ;
    END
  END i[541]
  PIN i[542]
    DIRECTION INPUT ;
    USE SIGNAL ;
    PORT
      LAYER M4 ;
        RECT  0 19.344 0.084 19.368 ;
    END
  END i[542]
  PIN i[543]
    DIRECTION INPUT ;
    USE SIGNAL ;
    PORT
      LAYER M4 ;
        RECT  0 19.44 0.084 19.464 ;
    END
  END i[543]
  PIN i[544]
    DIRECTION INPUT ;
    USE SIGNAL ;
    PORT
      LAYER M4 ;
        RECT  0 7.248 0.084 7.272 ;
    END
  END i[544]
  PIN i[545]
    DIRECTION INPUT ;
    USE SIGNAL ;
    PORT
      LAYER M4 ;
        RECT  0 7.344 0.084 7.368 ;
    END
  END i[545]
  PIN i[546]
    DIRECTION INPUT ;
    USE SIGNAL ;
    PORT
      LAYER M4 ;
        RECT  0 7.44 0.084 7.464 ;
    END
  END i[546]
  PIN i[547]
    DIRECTION INPUT ;
    USE SIGNAL ;
    PORT
      LAYER M4 ;
        RECT  0 7.536 0.084 7.56 ;
    END
  END i[547]
  PIN i[548]
    DIRECTION INPUT ;
    USE SIGNAL ;
    PORT
      LAYER M4 ;
        RECT  0 7.632 0.084 7.656 ;
    END
  END i[548]
  PIN i[549]
    DIRECTION INPUT ;
    USE SIGNAL ;
    PORT
      LAYER M4 ;
        RECT  0 7.728 0.084 7.752 ;
    END
  END i[549]
  PIN i[54]
    DIRECTION INPUT ;
    USE SIGNAL ;
    PORT
      LAYER M4 ;
        RECT  0 34.704 0.084 34.728 ;
    END
  END i[54]
  PIN i[550]
    DIRECTION INPUT ;
    USE SIGNAL ;
    PORT
      LAYER M4 ;
        RECT  0 7.824 0.084 7.848 ;
    END
  END i[550]
  PIN i[551]
    DIRECTION INPUT ;
    USE SIGNAL ;
    PORT
      LAYER M4 ;
        RECT  0 7.92 0.084 7.944 ;
    END
  END i[551]
  PIN i[552]
    DIRECTION INPUT ;
    USE SIGNAL ;
    PORT
      LAYER M4 ;
        RECT  0 8.016 0.084 8.04 ;
    END
  END i[552]
  PIN i[553]
    DIRECTION INPUT ;
    USE SIGNAL ;
    PORT
      LAYER M4 ;
        RECT  0 8.112 0.084 8.136 ;
    END
  END i[553]
  PIN i[554]
    DIRECTION INPUT ;
    USE SIGNAL ;
    PORT
      LAYER M4 ;
        RECT  0 8.208 0.084 8.232 ;
    END
  END i[554]
  PIN i[555]
    DIRECTION INPUT ;
    USE SIGNAL ;
    PORT
      LAYER M4 ;
        RECT  0 8.304 0.084 8.328 ;
    END
  END i[555]
  PIN i[556]
    DIRECTION INPUT ;
    USE SIGNAL ;
    PORT
      LAYER M4 ;
        RECT  0 8.4 0.084 8.424 ;
    END
  END i[556]
  PIN i[557]
    DIRECTION INPUT ;
    USE SIGNAL ;
    PORT
      LAYER M4 ;
        RECT  0 8.496 0.084 8.52 ;
    END
  END i[557]
  PIN i[558]
    DIRECTION INPUT ;
    USE SIGNAL ;
    PORT
      LAYER M4 ;
        RECT  0 8.592 0.084 8.616 ;
    END
  END i[558]
  PIN i[559]
    DIRECTION INPUT ;
    USE SIGNAL ;
    PORT
      LAYER M4 ;
        RECT  0 8.688 0.084 8.712 ;
    END
  END i[559]
  PIN i[55]
    DIRECTION INPUT ;
    USE SIGNAL ;
    PORT
      LAYER M4 ;
        RECT  0 34.8 0.084 34.824 ;
    END
  END i[55]
  PIN i[560]
    DIRECTION INPUT ;
    USE SIGNAL ;
    PORT
      LAYER M4 ;
        RECT  0 8.784 0.084 8.808 ;
    END
  END i[560]
  PIN i[561]
    DIRECTION INPUT ;
    USE SIGNAL ;
    PORT
      LAYER M4 ;
        RECT  0 8.88 0.084 8.904 ;
    END
  END i[561]
  PIN i[562]
    DIRECTION INPUT ;
    USE SIGNAL ;
    PORT
      LAYER M4 ;
        RECT  0 8.976 0.084 9 ;
    END
  END i[562]
  PIN i[563]
    DIRECTION INPUT ;
    USE SIGNAL ;
    PORT
      LAYER M4 ;
        RECT  0 9.072 0.084 9.096 ;
    END
  END i[563]
  PIN i[564]
    DIRECTION INPUT ;
    USE SIGNAL ;
    PORT
      LAYER M4 ;
        RECT  0 9.168 0.084 9.192 ;
    END
  END i[564]
  PIN i[565]
    DIRECTION INPUT ;
    USE SIGNAL ;
    PORT
      LAYER M4 ;
        RECT  0 9.264 0.084 9.288 ;
    END
  END i[565]
  PIN i[566]
    DIRECTION INPUT ;
    USE SIGNAL ;
    PORT
      LAYER M4 ;
        RECT  0 9.36 0.084 9.384 ;
    END
  END i[566]
  PIN i[567]
    DIRECTION INPUT ;
    USE SIGNAL ;
    PORT
      LAYER M4 ;
        RECT  0 9.456 0.084 9.48 ;
    END
  END i[567]
  PIN i[568]
    DIRECTION INPUT ;
    USE SIGNAL ;
    PORT
      LAYER M4 ;
        RECT  0 9.552 0.084 9.576 ;
    END
  END i[568]
  PIN i[569]
    DIRECTION INPUT ;
    USE SIGNAL ;
    PORT
      LAYER M4 ;
        RECT  0 9.648 0.084 9.672 ;
    END
  END i[569]
  PIN i[56]
    DIRECTION INPUT ;
    USE SIGNAL ;
    PORT
      LAYER M4 ;
        RECT  0 34.896 0.084 34.92 ;
    END
  END i[56]
  PIN i[570]
    DIRECTION INPUT ;
    USE SIGNAL ;
    PORT
      LAYER M4 ;
        RECT  0 9.744 0.084 9.768 ;
    END
  END i[570]
  PIN i[571]
    DIRECTION INPUT ;
    USE SIGNAL ;
    PORT
      LAYER M4 ;
        RECT  0 9.84 0.084 9.864 ;
    END
  END i[571]
  PIN i[572]
    DIRECTION INPUT ;
    USE SIGNAL ;
    PORT
      LAYER M4 ;
        RECT  0 9.936 0.084 9.96 ;
    END
  END i[572]
  PIN i[573]
    DIRECTION INPUT ;
    USE SIGNAL ;
    PORT
      LAYER M4 ;
        RECT  0 10.032 0.084 10.056 ;
    END
  END i[573]
  PIN i[574]
    DIRECTION INPUT ;
    USE SIGNAL ;
    PORT
      LAYER M4 ;
        RECT  0 10.128 0.084 10.152 ;
    END
  END i[574]
  PIN i[575]
    DIRECTION INPUT ;
    USE SIGNAL ;
    PORT
      LAYER M4 ;
        RECT  0 10.224 0.084 10.248 ;
    END
  END i[575]
  PIN i[576]
    DIRECTION INPUT ;
    USE SIGNAL ;
    PORT
      LAYER M4 ;
        RECT  0 3.408 0.084 3.432 ;
    END
  END i[576]
  PIN i[577]
    DIRECTION INPUT ;
    USE SIGNAL ;
    PORT
      LAYER M4 ;
        RECT  0 3.504 0.084 3.528 ;
    END
  END i[577]
  PIN i[578]
    DIRECTION INPUT ;
    USE SIGNAL ;
    PORT
      LAYER M4 ;
        RECT  0 3.6 0.084 3.624 ;
    END
  END i[578]
  PIN i[579]
    DIRECTION INPUT ;
    USE SIGNAL ;
    PORT
      LAYER M4 ;
        RECT  0 3.696 0.084 3.72 ;
    END
  END i[579]
  PIN i[57]
    DIRECTION INPUT ;
    USE SIGNAL ;
    PORT
      LAYER M4 ;
        RECT  0 34.992 0.084 35.016 ;
    END
  END i[57]
  PIN i[580]
    DIRECTION INPUT ;
    USE SIGNAL ;
    PORT
      LAYER M4 ;
        RECT  0 3.792 0.084 3.816 ;
    END
  END i[580]
  PIN i[581]
    DIRECTION INPUT ;
    USE SIGNAL ;
    PORT
      LAYER M4 ;
        RECT  0 3.888 0.084 3.912 ;
    END
  END i[581]
  PIN i[582]
    DIRECTION INPUT ;
    USE SIGNAL ;
    PORT
      LAYER M4 ;
        RECT  0 3.984 0.084 4.008 ;
    END
  END i[582]
  PIN i[583]
    DIRECTION INPUT ;
    USE SIGNAL ;
    PORT
      LAYER M4 ;
        RECT  0 4.08 0.084 4.104 ;
    END
  END i[583]
  PIN i[584]
    DIRECTION INPUT ;
    USE SIGNAL ;
    PORT
      LAYER M4 ;
        RECT  0 4.176 0.084 4.2 ;
    END
  END i[584]
  PIN i[585]
    DIRECTION INPUT ;
    USE SIGNAL ;
    PORT
      LAYER M4 ;
        RECT  0 4.272 0.084 4.296 ;
    END
  END i[585]
  PIN i[586]
    DIRECTION INPUT ;
    USE SIGNAL ;
    PORT
      LAYER M4 ;
        RECT  0 4.368 0.084 4.392 ;
    END
  END i[586]
  PIN i[587]
    DIRECTION INPUT ;
    USE SIGNAL ;
    PORT
      LAYER M4 ;
        RECT  0 4.464 0.084 4.488 ;
    END
  END i[587]
  PIN i[588]
    DIRECTION INPUT ;
    USE SIGNAL ;
    PORT
      LAYER M4 ;
        RECT  0 4.56 0.084 4.584 ;
    END
  END i[588]
  PIN i[589]
    DIRECTION INPUT ;
    USE SIGNAL ;
    PORT
      LAYER M4 ;
        RECT  0 4.656 0.084 4.68 ;
    END
  END i[589]
  PIN i[58]
    DIRECTION INPUT ;
    USE SIGNAL ;
    PORT
      LAYER M4 ;
        RECT  0 35.088 0.084 35.112 ;
    END
  END i[58]
  PIN i[590]
    DIRECTION INPUT ;
    USE SIGNAL ;
    PORT
      LAYER M4 ;
        RECT  0 4.752 0.084 4.776 ;
    END
  END i[590]
  PIN i[591]
    DIRECTION INPUT ;
    USE SIGNAL ;
    PORT
      LAYER M4 ;
        RECT  0 4.848 0.084 4.872 ;
    END
  END i[591]
  PIN i[592]
    DIRECTION INPUT ;
    USE SIGNAL ;
    PORT
      LAYER M4 ;
        RECT  0 4.944 0.084 4.968 ;
    END
  END i[592]
  PIN i[593]
    DIRECTION INPUT ;
    USE SIGNAL ;
    PORT
      LAYER M4 ;
        RECT  0 5.04 0.084 5.064 ;
    END
  END i[593]
  PIN i[594]
    DIRECTION INPUT ;
    USE SIGNAL ;
    PORT
      LAYER M4 ;
        RECT  0 5.136 0.084 5.16 ;
    END
  END i[594]
  PIN i[595]
    DIRECTION INPUT ;
    USE SIGNAL ;
    PORT
      LAYER M4 ;
        RECT  0 5.232 0.084 5.256 ;
    END
  END i[595]
  PIN i[596]
    DIRECTION INPUT ;
    USE SIGNAL ;
    PORT
      LAYER M4 ;
        RECT  0 5.328 0.084 5.352 ;
    END
  END i[596]
  PIN i[597]
    DIRECTION INPUT ;
    USE SIGNAL ;
    PORT
      LAYER M4 ;
        RECT  0 5.424 0.084 5.448 ;
    END
  END i[597]
  PIN i[598]
    DIRECTION INPUT ;
    USE SIGNAL ;
    PORT
      LAYER M4 ;
        RECT  0 5.52 0.084 5.544 ;
    END
  END i[598]
  PIN i[599]
    DIRECTION INPUT ;
    USE SIGNAL ;
    PORT
      LAYER M4 ;
        RECT  0 5.616 0.084 5.64 ;
    END
  END i[599]
  PIN i[59]
    DIRECTION INPUT ;
    USE SIGNAL ;
    PORT
      LAYER M4 ;
        RECT  0 35.184 0.084 35.208 ;
    END
  END i[59]
  PIN i[5]
    DIRECTION INPUT ;
    USE SIGNAL ;
    PORT
      LAYER M4 ;
        RECT  0 42.288 0.084 42.312 ;
    END
  END i[5]
  PIN i[600]
    DIRECTION INPUT ;
    USE SIGNAL ;
    PORT
      LAYER M4 ;
        RECT  0 5.712 0.084 5.736 ;
    END
  END i[600]
  PIN i[601]
    DIRECTION INPUT ;
    USE SIGNAL ;
    PORT
      LAYER M4 ;
        RECT  0 5.808 0.084 5.832 ;
    END
  END i[601]
  PIN i[602]
    DIRECTION INPUT ;
    USE SIGNAL ;
    PORT
      LAYER M4 ;
        RECT  0 5.904 0.084 5.928 ;
    END
  END i[602]
  PIN i[603]
    DIRECTION INPUT ;
    USE SIGNAL ;
    PORT
      LAYER M4 ;
        RECT  0 6 0.084 6.024 ;
    END
  END i[603]
  PIN i[604]
    DIRECTION INPUT ;
    USE SIGNAL ;
    PORT
      LAYER M4 ;
        RECT  0 6.096 0.084 6.12 ;
    END
  END i[604]
  PIN i[605]
    DIRECTION INPUT ;
    USE SIGNAL ;
    PORT
      LAYER M4 ;
        RECT  0 6.192 0.084 6.216 ;
    END
  END i[605]
  PIN i[606]
    DIRECTION INPUT ;
    USE SIGNAL ;
    PORT
      LAYER M4 ;
        RECT  0 6.288 0.084 6.312 ;
    END
  END i[606]
  PIN i[607]
    DIRECTION INPUT ;
    USE SIGNAL ;
    PORT
      LAYER M4 ;
        RECT  0 6.384 0.084 6.408 ;
    END
  END i[607]
  PIN i[608]
    DIRECTION INPUT ;
    USE SIGNAL ;
    PORT
      LAYER M4 ;
        RECT  0 1.872 0.084 1.896 ;
    END
  END i[608]
  PIN i[609]
    DIRECTION INPUT ;
    USE SIGNAL ;
    PORT
      LAYER M4 ;
        RECT  0 1.968 0.084 1.992 ;
    END
  END i[609]
  PIN i[60]
    DIRECTION INPUT ;
    USE SIGNAL ;
    PORT
      LAYER M4 ;
        RECT  0 35.28 0.084 35.304 ;
    END
  END i[60]
  PIN i[610]
    DIRECTION INPUT ;
    USE SIGNAL ;
    PORT
      LAYER M4 ;
        RECT  0 2.064 0.084 2.088 ;
    END
  END i[610]
  PIN i[611]
    DIRECTION INPUT ;
    USE SIGNAL ;
    PORT
      LAYER M4 ;
        RECT  0 2.16 0.084 2.184 ;
    END
  END i[611]
  PIN i[612]
    DIRECTION INPUT ;
    USE SIGNAL ;
    PORT
      LAYER M4 ;
        RECT  0 2.256 0.084 2.28 ;
    END
  END i[612]
  PIN i[613]
    DIRECTION INPUT ;
    USE SIGNAL ;
    PORT
      LAYER M4 ;
        RECT  0 2.352 0.084 2.376 ;
    END
  END i[613]
  PIN i[614]
    DIRECTION INPUT ;
    USE SIGNAL ;
    PORT
      LAYER M4 ;
        RECT  0 2.448 0.084 2.472 ;
    END
  END i[614]
  PIN i[615]
    DIRECTION INPUT ;
    USE SIGNAL ;
    PORT
      LAYER M4 ;
        RECT  0 2.544 0.084 2.568 ;
    END
  END i[615]
  PIN i[616]
    DIRECTION INPUT ;
    USE SIGNAL ;
    PORT
      LAYER M4 ;
        RECT  0 2.64 0.084 2.664 ;
    END
  END i[616]
  PIN i[617]
    DIRECTION INPUT ;
    USE SIGNAL ;
    PORT
      LAYER M4 ;
        RECT  0 2.736 0.084 2.76 ;
    END
  END i[617]
  PIN i[618]
    DIRECTION INPUT ;
    USE SIGNAL ;
    PORT
      LAYER M4 ;
        RECT  0 2.832 0.084 2.856 ;
    END
  END i[618]
  PIN i[619]
    DIRECTION INPUT ;
    USE SIGNAL ;
    PORT
      LAYER M4 ;
        RECT  0 2.928 0.084 2.952 ;
    END
  END i[619]
  PIN i[61]
    DIRECTION INPUT ;
    USE SIGNAL ;
    PORT
      LAYER M4 ;
        RECT  0 35.376 0.084 35.4 ;
    END
  END i[61]
  PIN i[620]
    DIRECTION INPUT ;
    USE SIGNAL ;
    PORT
      LAYER M4 ;
        RECT  0 3.024 0.084 3.048 ;
    END
  END i[620]
  PIN i[621]
    DIRECTION INPUT ;
    USE SIGNAL ;
    PORT
      LAYER M4 ;
        RECT  0 3.12 0.084 3.144 ;
    END
  END i[621]
  PIN i[622]
    DIRECTION INPUT ;
    USE SIGNAL ;
    PORT
      LAYER M4 ;
        RECT  0 3.216 0.084 3.24 ;
    END
  END i[622]
  PIN i[623]
    DIRECTION INPUT ;
    USE SIGNAL ;
    PORT
      LAYER M4 ;
        RECT  0 3.312 0.084 3.336 ;
    END
  END i[623]
  PIN i[62]
    DIRECTION INPUT ;
    USE SIGNAL ;
    PORT
      LAYER M4 ;
        RECT  0 35.472 0.084 35.496 ;
    END
  END i[62]
  PIN i[63]
    DIRECTION INPUT ;
    USE SIGNAL ;
    PORT
      LAYER M4 ;
        RECT  0 35.568 0.084 35.592 ;
    END
  END i[63]
  PIN i[64]
    DIRECTION INPUT ;
    USE SIGNAL ;
    PORT
      LAYER M4 ;
        RECT  0 29.52 0.084 29.544 ;
    END
  END i[64]
  PIN i[65]
    DIRECTION INPUT ;
    USE SIGNAL ;
    PORT
      LAYER M4 ;
        RECT  0 29.616 0.084 29.64 ;
    END
  END i[65]
  PIN i[66]
    DIRECTION INPUT ;
    USE SIGNAL ;
    PORT
      LAYER M4 ;
        RECT  0 29.712 0.084 29.736 ;
    END
  END i[66]
  PIN i[67]
    DIRECTION INPUT ;
    USE SIGNAL ;
    PORT
      LAYER M4 ;
        RECT  0 29.808 0.084 29.832 ;
    END
  END i[67]
  PIN i[68]
    DIRECTION INPUT ;
    USE SIGNAL ;
    PORT
      LAYER M4 ;
        RECT  0 29.904 0.084 29.928 ;
    END
  END i[68]
  PIN i[69]
    DIRECTION INPUT ;
    USE SIGNAL ;
    PORT
      LAYER M4 ;
        RECT  0 30 0.084 30.024 ;
    END
  END i[69]
  PIN i[6]
    DIRECTION INPUT ;
    USE SIGNAL ;
    PORT
      LAYER M4 ;
        RECT  0 42.384 0.084 42.408 ;
    END
  END i[6]
  PIN i[70]
    DIRECTION INPUT ;
    USE SIGNAL ;
    PORT
      LAYER M4 ;
        RECT  0 30.096 0.084 30.12 ;
    END
  END i[70]
  PIN i[71]
    DIRECTION INPUT ;
    USE SIGNAL ;
    PORT
      LAYER M4 ;
        RECT  0 30.192 0.084 30.216 ;
    END
  END i[71]
  PIN i[72]
    DIRECTION INPUT ;
    USE SIGNAL ;
    PORT
      LAYER M4 ;
        RECT  0 30.288 0.084 30.312 ;
    END
  END i[72]
  PIN i[73]
    DIRECTION INPUT ;
    USE SIGNAL ;
    PORT
      LAYER M4 ;
        RECT  0 30.384 0.084 30.408 ;
    END
  END i[73]
  PIN i[74]
    DIRECTION INPUT ;
    USE SIGNAL ;
    PORT
      LAYER M4 ;
        RECT  0 30.48 0.084 30.504 ;
    END
  END i[74]
  PIN i[75]
    DIRECTION INPUT ;
    USE SIGNAL ;
    PORT
      LAYER M4 ;
        RECT  0 30.576 0.084 30.6 ;
    END
  END i[75]
  PIN i[76]
    DIRECTION INPUT ;
    USE SIGNAL ;
    PORT
      LAYER M4 ;
        RECT  0 30.672 0.084 30.696 ;
    END
  END i[76]
  PIN i[77]
    DIRECTION INPUT ;
    USE SIGNAL ;
    PORT
      LAYER M4 ;
        RECT  0 30.768 0.084 30.792 ;
    END
  END i[77]
  PIN i[78]
    DIRECTION INPUT ;
    USE SIGNAL ;
    PORT
      LAYER M4 ;
        RECT  0 30.864 0.084 30.888 ;
    END
  END i[78]
  PIN i[79]
    DIRECTION INPUT ;
    USE SIGNAL ;
    PORT
      LAYER M4 ;
        RECT  0 30.96 0.084 30.984 ;
    END
  END i[79]
  PIN i[7]
    DIRECTION INPUT ;
    USE SIGNAL ;
    PORT
      LAYER M4 ;
        RECT  0 42.48 0.084 42.504 ;
    END
  END i[7]
  PIN i[80]
    DIRECTION INPUT ;
    USE SIGNAL ;
    PORT
      LAYER M4 ;
        RECT  0 31.056 0.084 31.08 ;
    END
  END i[80]
  PIN i[81]
    DIRECTION INPUT ;
    USE SIGNAL ;
    PORT
      LAYER M4 ;
        RECT  0 31.152 0.084 31.176 ;
    END
  END i[81]
  PIN i[82]
    DIRECTION INPUT ;
    USE SIGNAL ;
    PORT
      LAYER M4 ;
        RECT  0 31.248 0.084 31.272 ;
    END
  END i[82]
  PIN i[83]
    DIRECTION INPUT ;
    USE SIGNAL ;
    PORT
      LAYER M4 ;
        RECT  0 31.344 0.084 31.368 ;
    END
  END i[83]
  PIN i[84]
    DIRECTION INPUT ;
    USE SIGNAL ;
    PORT
      LAYER M4 ;
        RECT  0 31.44 0.084 31.464 ;
    END
  END i[84]
  PIN i[85]
    DIRECTION INPUT ;
    USE SIGNAL ;
    PORT
      LAYER M4 ;
        RECT  0 31.536 0.084 31.56 ;
    END
  END i[85]
  PIN i[86]
    DIRECTION INPUT ;
    USE SIGNAL ;
    PORT
      LAYER M4 ;
        RECT  0 31.632 0.084 31.656 ;
    END
  END i[86]
  PIN i[87]
    DIRECTION INPUT ;
    USE SIGNAL ;
    PORT
      LAYER M4 ;
        RECT  0 31.728 0.084 31.752 ;
    END
  END i[87]
  PIN i[88]
    DIRECTION INPUT ;
    USE SIGNAL ;
    PORT
      LAYER M4 ;
        RECT  0 31.824 0.084 31.848 ;
    END
  END i[88]
  PIN i[89]
    DIRECTION INPUT ;
    USE SIGNAL ;
    PORT
      LAYER M4 ;
        RECT  0 31.92 0.084 31.944 ;
    END
  END i[89]
  PIN i[8]
    DIRECTION INPUT ;
    USE SIGNAL ;
    PORT
      LAYER M4 ;
        RECT  0 42.576 0.084 42.6 ;
    END
  END i[8]
  PIN i[90]
    DIRECTION INPUT ;
    USE SIGNAL ;
    PORT
      LAYER M4 ;
        RECT  0 32.016 0.084 32.04 ;
    END
  END i[90]
  PIN i[91]
    DIRECTION INPUT ;
    USE SIGNAL ;
    PORT
      LAYER M4 ;
        RECT  0 32.112 0.084 32.136 ;
    END
  END i[91]
  PIN i[92]
    DIRECTION INPUT ;
    USE SIGNAL ;
    PORT
      LAYER M4 ;
        RECT  0 32.208 0.084 32.232 ;
    END
  END i[92]
  PIN i[93]
    DIRECTION INPUT ;
    USE SIGNAL ;
    PORT
      LAYER M4 ;
        RECT  0 32.304 0.084 32.328 ;
    END
  END i[93]
  PIN i[94]
    DIRECTION INPUT ;
    USE SIGNAL ;
    PORT
      LAYER M4 ;
        RECT  0 32.4 0.084 32.424 ;
    END
  END i[94]
  PIN i[95]
    DIRECTION INPUT ;
    USE SIGNAL ;
    PORT
      LAYER M4 ;
        RECT  0 32.496 0.084 32.52 ;
    END
  END i[95]
  PIN i[96]
    DIRECTION INPUT ;
    USE SIGNAL ;
    PORT
      LAYER M4 ;
        RECT  0 38.736 0.084 38.76 ;
    END
  END i[96]
  PIN i[97]
    DIRECTION INPUT ;
    USE SIGNAL ;
    PORT
      LAYER M4 ;
        RECT  0 38.832 0.084 38.856 ;
    END
  END i[97]
  PIN i[98]
    DIRECTION INPUT ;
    USE SIGNAL ;
    PORT
      LAYER M4 ;
        RECT  0 38.928 0.084 38.952 ;
    END
  END i[98]
  PIN i[99]
    DIRECTION INPUT ;
    USE SIGNAL ;
    PORT
      LAYER M4 ;
        RECT  0 39.024 0.084 39.048 ;
    END
  END i[99]
  PIN i[9]
    DIRECTION INPUT ;
    USE SIGNAL ;
    PORT
      LAYER M4 ;
        RECT  0 42.672 0.084 42.696 ;
    END
  END i[9]
  PIN o[0]
    DIRECTION OUTPUT ;
    USE SIGNAL ;
    PORT
      LAYER M4 ;
        RECT  21.516 19.92 21.6 19.944 ;
    END
  END o[0]
  PIN o[100]
    DIRECTION OUTPUT ;
    USE SIGNAL ;
    PORT
      LAYER M4 ;
        RECT  21.516 29.52 21.6 29.544 ;
    END
  END o[100]
  PIN o[101]
    DIRECTION OUTPUT ;
    USE SIGNAL ;
    PORT
      LAYER M4 ;
        RECT  21.516 29.616 21.6 29.64 ;
    END
  END o[101]
  PIN o[102]
    DIRECTION OUTPUT ;
    USE SIGNAL ;
    PORT
      LAYER M4 ;
        RECT  21.516 29.712 21.6 29.736 ;
    END
  END o[102]
  PIN o[103]
    DIRECTION OUTPUT ;
    USE SIGNAL ;
    PORT
      LAYER M4 ;
        RECT  21.516 29.808 21.6 29.832 ;
    END
  END o[103]
  PIN o[104]
    DIRECTION OUTPUT ;
    USE SIGNAL ;
    PORT
      LAYER M4 ;
        RECT  21.516 29.904 21.6 29.928 ;
    END
  END o[104]
  PIN o[105]
    DIRECTION OUTPUT ;
    USE SIGNAL ;
    PORT
      LAYER M4 ;
        RECT  21.516 30 21.6 30.024 ;
    END
  END o[105]
  PIN o[106]
    DIRECTION OUTPUT ;
    USE SIGNAL ;
    PORT
      LAYER M4 ;
        RECT  21.516 30.096 21.6 30.12 ;
    END
  END o[106]
  PIN o[107]
    DIRECTION OUTPUT ;
    USE SIGNAL ;
    PORT
      LAYER M4 ;
        RECT  21.516 30.192 21.6 30.216 ;
    END
  END o[107]
  PIN o[108]
    DIRECTION OUTPUT ;
    USE SIGNAL ;
    PORT
      LAYER M4 ;
        RECT  21.516 30.288 21.6 30.312 ;
    END
  END o[108]
  PIN o[109]
    DIRECTION OUTPUT ;
    USE SIGNAL ;
    PORT
      LAYER M4 ;
        RECT  21.516 30.384 21.6 30.408 ;
    END
  END o[109]
  PIN o[10]
    DIRECTION OUTPUT ;
    USE SIGNAL ;
    PORT
      LAYER M4 ;
        RECT  21.516 20.88 21.6 20.904 ;
    END
  END o[10]
  PIN o[110]
    DIRECTION OUTPUT ;
    USE SIGNAL ;
    PORT
      LAYER M4 ;
        RECT  21.516 30.48 21.6 30.504 ;
    END
  END o[110]
  PIN o[111]
    DIRECTION OUTPUT ;
    USE SIGNAL ;
    PORT
      LAYER M4 ;
        RECT  21.516 30.576 21.6 30.6 ;
    END
  END o[111]
  PIN o[112]
    DIRECTION OUTPUT ;
    USE SIGNAL ;
    PORT
      LAYER M4 ;
        RECT  21.516 30.672 21.6 30.696 ;
    END
  END o[112]
  PIN o[113]
    DIRECTION OUTPUT ;
    USE SIGNAL ;
    PORT
      LAYER M4 ;
        RECT  21.516 30.768 21.6 30.792 ;
    END
  END o[113]
  PIN o[114]
    DIRECTION OUTPUT ;
    USE SIGNAL ;
    PORT
      LAYER M4 ;
        RECT  21.516 30.864 21.6 30.888 ;
    END
  END o[114]
  PIN o[115]
    DIRECTION OUTPUT ;
    USE SIGNAL ;
    PORT
      LAYER M4 ;
        RECT  21.516 30.96 21.6 30.984 ;
    END
  END o[115]
  PIN o[116]
    DIRECTION OUTPUT ;
    USE SIGNAL ;
    PORT
      LAYER M4 ;
        RECT  21.516 31.056 21.6 31.08 ;
    END
  END o[116]
  PIN o[117]
    DIRECTION OUTPUT ;
    USE SIGNAL ;
    PORT
      LAYER M4 ;
        RECT  21.516 31.152 21.6 31.176 ;
    END
  END o[117]
  PIN o[118]
    DIRECTION OUTPUT ;
    USE SIGNAL ;
    PORT
      LAYER M4 ;
        RECT  21.516 31.248 21.6 31.272 ;
    END
  END o[118]
  PIN o[119]
    DIRECTION OUTPUT ;
    USE SIGNAL ;
    PORT
      LAYER M4 ;
        RECT  21.516 31.344 21.6 31.368 ;
    END
  END o[119]
  PIN o[11]
    DIRECTION OUTPUT ;
    USE SIGNAL ;
    PORT
      LAYER M4 ;
        RECT  21.516 20.976 21.6 21 ;
    END
  END o[11]
  PIN o[120]
    DIRECTION OUTPUT ;
    USE SIGNAL ;
    PORT
      LAYER M4 ;
        RECT  21.516 31.44 21.6 31.464 ;
    END
  END o[120]
  PIN o[121]
    DIRECTION OUTPUT ;
    USE SIGNAL ;
    PORT
      LAYER M4 ;
        RECT  21.516 31.536 21.6 31.56 ;
    END
  END o[121]
  PIN o[122]
    DIRECTION OUTPUT ;
    USE SIGNAL ;
    PORT
      LAYER M4 ;
        RECT  21.516 31.632 21.6 31.656 ;
    END
  END o[122]
  PIN o[123]
    DIRECTION OUTPUT ;
    USE SIGNAL ;
    PORT
      LAYER M4 ;
        RECT  21.516 31.728 21.6 31.752 ;
    END
  END o[123]
  PIN o[124]
    DIRECTION OUTPUT ;
    USE SIGNAL ;
    PORT
      LAYER M4 ;
        RECT  21.516 31.824 21.6 31.848 ;
    END
  END o[124]
  PIN o[125]
    DIRECTION OUTPUT ;
    USE SIGNAL ;
    PORT
      LAYER M4 ;
        RECT  21.516 31.92 21.6 31.944 ;
    END
  END o[125]
  PIN o[126]
    DIRECTION OUTPUT ;
    USE SIGNAL ;
    PORT
      LAYER M4 ;
        RECT  21.516 32.016 21.6 32.04 ;
    END
  END o[126]
  PIN o[127]
    DIRECTION OUTPUT ;
    USE SIGNAL ;
    PORT
      LAYER M4 ;
        RECT  21.516 32.112 21.6 32.136 ;
    END
  END o[127]
  PIN o[128]
    DIRECTION OUTPUT ;
    USE SIGNAL ;
    PORT
      LAYER M4 ;
        RECT  21.516 26.064 21.6 26.088 ;
    END
  END o[128]
  PIN o[129]
    DIRECTION OUTPUT ;
    USE SIGNAL ;
    PORT
      LAYER M4 ;
        RECT  21.516 26.16 21.6 26.184 ;
    END
  END o[129]
  PIN o[12]
    DIRECTION OUTPUT ;
    USE SIGNAL ;
    PORT
      LAYER M4 ;
        RECT  21.516 21.072 21.6 21.096 ;
    END
  END o[12]
  PIN o[130]
    DIRECTION OUTPUT ;
    USE SIGNAL ;
    PORT
      LAYER M4 ;
        RECT  21.516 26.256 21.6 26.28 ;
    END
  END o[130]
  PIN o[131]
    DIRECTION OUTPUT ;
    USE SIGNAL ;
    PORT
      LAYER M4 ;
        RECT  21.516 26.352 21.6 26.376 ;
    END
  END o[131]
  PIN o[132]
    DIRECTION OUTPUT ;
    USE SIGNAL ;
    PORT
      LAYER M4 ;
        RECT  21.516 26.448 21.6 26.472 ;
    END
  END o[132]
  PIN o[133]
    DIRECTION OUTPUT ;
    USE SIGNAL ;
    PORT
      LAYER M4 ;
        RECT  21.516 26.544 21.6 26.568 ;
    END
  END o[133]
  PIN o[134]
    DIRECTION OUTPUT ;
    USE SIGNAL ;
    PORT
      LAYER M4 ;
        RECT  21.516 26.64 21.6 26.664 ;
    END
  END o[134]
  PIN o[135]
    DIRECTION OUTPUT ;
    USE SIGNAL ;
    PORT
      LAYER M4 ;
        RECT  21.516 26.736 21.6 26.76 ;
    END
  END o[135]
  PIN o[136]
    DIRECTION OUTPUT ;
    USE SIGNAL ;
    PORT
      LAYER M4 ;
        RECT  21.516 26.832 21.6 26.856 ;
    END
  END o[136]
  PIN o[137]
    DIRECTION OUTPUT ;
    USE SIGNAL ;
    PORT
      LAYER M4 ;
        RECT  21.516 26.928 21.6 26.952 ;
    END
  END o[137]
  PIN o[138]
    DIRECTION OUTPUT ;
    USE SIGNAL ;
    PORT
      LAYER M4 ;
        RECT  21.516 27.024 21.6 27.048 ;
    END
  END o[138]
  PIN o[139]
    DIRECTION OUTPUT ;
    USE SIGNAL ;
    PORT
      LAYER M4 ;
        RECT  21.516 27.12 21.6 27.144 ;
    END
  END o[139]
  PIN o[13]
    DIRECTION OUTPUT ;
    USE SIGNAL ;
    PORT
      LAYER M4 ;
        RECT  21.516 21.168 21.6 21.192 ;
    END
  END o[13]
  PIN o[140]
    DIRECTION OUTPUT ;
    USE SIGNAL ;
    PORT
      LAYER M4 ;
        RECT  21.516 27.216 21.6 27.24 ;
    END
  END o[140]
  PIN o[141]
    DIRECTION OUTPUT ;
    USE SIGNAL ;
    PORT
      LAYER M4 ;
        RECT  21.516 27.312 21.6 27.336 ;
    END
  END o[141]
  PIN o[142]
    DIRECTION OUTPUT ;
    USE SIGNAL ;
    PORT
      LAYER M4 ;
        RECT  21.516 27.408 21.6 27.432 ;
    END
  END o[142]
  PIN o[143]
    DIRECTION OUTPUT ;
    USE SIGNAL ;
    PORT
      LAYER M4 ;
        RECT  21.516 27.504 21.6 27.528 ;
    END
  END o[143]
  PIN o[144]
    DIRECTION OUTPUT ;
    USE SIGNAL ;
    PORT
      LAYER M4 ;
        RECT  21.516 27.6 21.6 27.624 ;
    END
  END o[144]
  PIN o[145]
    DIRECTION OUTPUT ;
    USE SIGNAL ;
    PORT
      LAYER M4 ;
        RECT  21.516 27.696 21.6 27.72 ;
    END
  END o[145]
  PIN o[146]
    DIRECTION OUTPUT ;
    USE SIGNAL ;
    PORT
      LAYER M4 ;
        RECT  21.516 27.792 21.6 27.816 ;
    END
  END o[146]
  PIN o[147]
    DIRECTION OUTPUT ;
    USE SIGNAL ;
    PORT
      LAYER M4 ;
        RECT  21.516 27.888 21.6 27.912 ;
    END
  END o[147]
  PIN o[148]
    DIRECTION OUTPUT ;
    USE SIGNAL ;
    PORT
      LAYER M4 ;
        RECT  21.516 27.984 21.6 28.008 ;
    END
  END o[148]
  PIN o[149]
    DIRECTION OUTPUT ;
    USE SIGNAL ;
    PORT
      LAYER M4 ;
        RECT  21.516 28.08 21.6 28.104 ;
    END
  END o[149]
  PIN o[14]
    DIRECTION OUTPUT ;
    USE SIGNAL ;
    PORT
      LAYER M4 ;
        RECT  21.516 21.264 21.6 21.288 ;
    END
  END o[14]
  PIN o[150]
    DIRECTION OUTPUT ;
    USE SIGNAL ;
    PORT
      LAYER M4 ;
        RECT  21.516 28.176 21.6 28.2 ;
    END
  END o[150]
  PIN o[151]
    DIRECTION OUTPUT ;
    USE SIGNAL ;
    PORT
      LAYER M4 ;
        RECT  21.516 28.272 21.6 28.296 ;
    END
  END o[151]
  PIN o[152]
    DIRECTION OUTPUT ;
    USE SIGNAL ;
    PORT
      LAYER M4 ;
        RECT  21.516 28.368 21.6 28.392 ;
    END
  END o[152]
  PIN o[153]
    DIRECTION OUTPUT ;
    USE SIGNAL ;
    PORT
      LAYER M4 ;
        RECT  21.516 28.464 21.6 28.488 ;
    END
  END o[153]
  PIN o[154]
    DIRECTION OUTPUT ;
    USE SIGNAL ;
    PORT
      LAYER M4 ;
        RECT  21.516 28.56 21.6 28.584 ;
    END
  END o[154]
  PIN o[155]
    DIRECTION OUTPUT ;
    USE SIGNAL ;
    PORT
      LAYER M4 ;
        RECT  21.516 28.656 21.6 28.68 ;
    END
  END o[155]
  PIN o[156]
    DIRECTION OUTPUT ;
    USE SIGNAL ;
    PORT
      LAYER M4 ;
        RECT  21.516 28.752 21.6 28.776 ;
    END
  END o[156]
  PIN o[157]
    DIRECTION OUTPUT ;
    USE SIGNAL ;
    PORT
      LAYER M4 ;
        RECT  21.516 28.848 21.6 28.872 ;
    END
  END o[157]
  PIN o[158]
    DIRECTION OUTPUT ;
    USE SIGNAL ;
    PORT
      LAYER M4 ;
        RECT  21.516 28.944 21.6 28.968 ;
    END
  END o[158]
  PIN o[159]
    DIRECTION OUTPUT ;
    USE SIGNAL ;
    PORT
      LAYER M4 ;
        RECT  21.516 29.04 21.6 29.064 ;
    END
  END o[159]
  PIN o[15]
    DIRECTION OUTPUT ;
    USE SIGNAL ;
    PORT
      LAYER M4 ;
        RECT  21.516 21.36 21.6 21.384 ;
    END
  END o[15]
  PIN o[160]
    DIRECTION OUTPUT ;
    USE SIGNAL ;
    PORT
      LAYER M4 ;
        RECT  21.516 35.28 21.6 35.304 ;
    END
  END o[160]
  PIN o[161]
    DIRECTION OUTPUT ;
    USE SIGNAL ;
    PORT
      LAYER M4 ;
        RECT  21.516 35.376 21.6 35.4 ;
    END
  END o[161]
  PIN o[162]
    DIRECTION OUTPUT ;
    USE SIGNAL ;
    PORT
      LAYER M4 ;
        RECT  21.516 35.472 21.6 35.496 ;
    END
  END o[162]
  PIN o[163]
    DIRECTION OUTPUT ;
    USE SIGNAL ;
    PORT
      LAYER M4 ;
        RECT  21.516 35.568 21.6 35.592 ;
    END
  END o[163]
  PIN o[164]
    DIRECTION OUTPUT ;
    USE SIGNAL ;
    PORT
      LAYER M4 ;
        RECT  21.516 35.664 21.6 35.688 ;
    END
  END o[164]
  PIN o[165]
    DIRECTION OUTPUT ;
    USE SIGNAL ;
    PORT
      LAYER M4 ;
        RECT  21.516 35.76 21.6 35.784 ;
    END
  END o[165]
  PIN o[166]
    DIRECTION OUTPUT ;
    USE SIGNAL ;
    PORT
      LAYER M4 ;
        RECT  21.516 35.856 21.6 35.88 ;
    END
  END o[166]
  PIN o[167]
    DIRECTION OUTPUT ;
    USE SIGNAL ;
    PORT
      LAYER M4 ;
        RECT  21.516 35.952 21.6 35.976 ;
    END
  END o[167]
  PIN o[168]
    DIRECTION OUTPUT ;
    USE SIGNAL ;
    PORT
      LAYER M4 ;
        RECT  21.516 36.048 21.6 36.072 ;
    END
  END o[168]
  PIN o[169]
    DIRECTION OUTPUT ;
    USE SIGNAL ;
    PORT
      LAYER M4 ;
        RECT  21.516 36.144 21.6 36.168 ;
    END
  END o[169]
  PIN o[16]
    DIRECTION OUTPUT ;
    USE SIGNAL ;
    PORT
      LAYER M4 ;
        RECT  21.516 21.456 21.6 21.48 ;
    END
  END o[16]
  PIN o[170]
    DIRECTION OUTPUT ;
    USE SIGNAL ;
    PORT
      LAYER M4 ;
        RECT  21.516 36.24 21.6 36.264 ;
    END
  END o[170]
  PIN o[171]
    DIRECTION OUTPUT ;
    USE SIGNAL ;
    PORT
      LAYER M4 ;
        RECT  21.516 36.336 21.6 36.36 ;
    END
  END o[171]
  PIN o[172]
    DIRECTION OUTPUT ;
    USE SIGNAL ;
    PORT
      LAYER M4 ;
        RECT  21.516 36.432 21.6 36.456 ;
    END
  END o[172]
  PIN o[173]
    DIRECTION OUTPUT ;
    USE SIGNAL ;
    PORT
      LAYER M4 ;
        RECT  21.516 36.528 21.6 36.552 ;
    END
  END o[173]
  PIN o[174]
    DIRECTION OUTPUT ;
    USE SIGNAL ;
    PORT
      LAYER M4 ;
        RECT  21.516 36.624 21.6 36.648 ;
    END
  END o[174]
  PIN o[175]
    DIRECTION OUTPUT ;
    USE SIGNAL ;
    PORT
      LAYER M4 ;
        RECT  21.516 36.72 21.6 36.744 ;
    END
  END o[175]
  PIN o[176]
    DIRECTION OUTPUT ;
    USE SIGNAL ;
    PORT
      LAYER M4 ;
        RECT  21.516 36.816 21.6 36.84 ;
    END
  END o[176]
  PIN o[177]
    DIRECTION OUTPUT ;
    USE SIGNAL ;
    PORT
      LAYER M4 ;
        RECT  21.516 36.912 21.6 36.936 ;
    END
  END o[177]
  PIN o[178]
    DIRECTION OUTPUT ;
    USE SIGNAL ;
    PORT
      LAYER M4 ;
        RECT  21.516 37.008 21.6 37.032 ;
    END
  END o[178]
  PIN o[179]
    DIRECTION OUTPUT ;
    USE SIGNAL ;
    PORT
      LAYER M4 ;
        RECT  21.516 37.104 21.6 37.128 ;
    END
  END o[179]
  PIN o[17]
    DIRECTION OUTPUT ;
    USE SIGNAL ;
    PORT
      LAYER M4 ;
        RECT  21.516 21.552 21.6 21.576 ;
    END
  END o[17]
  PIN o[180]
    DIRECTION OUTPUT ;
    USE SIGNAL ;
    PORT
      LAYER M4 ;
        RECT  21.516 37.2 21.6 37.224 ;
    END
  END o[180]
  PIN o[181]
    DIRECTION OUTPUT ;
    USE SIGNAL ;
    PORT
      LAYER M4 ;
        RECT  21.516 37.296 21.6 37.32 ;
    END
  END o[181]
  PIN o[182]
    DIRECTION OUTPUT ;
    USE SIGNAL ;
    PORT
      LAYER M4 ;
        RECT  21.516 37.392 21.6 37.416 ;
    END
  END o[182]
  PIN o[183]
    DIRECTION OUTPUT ;
    USE SIGNAL ;
    PORT
      LAYER M4 ;
        RECT  21.516 37.488 21.6 37.512 ;
    END
  END o[183]
  PIN o[184]
    DIRECTION OUTPUT ;
    USE SIGNAL ;
    PORT
      LAYER M4 ;
        RECT  21.516 37.584 21.6 37.608 ;
    END
  END o[184]
  PIN o[185]
    DIRECTION OUTPUT ;
    USE SIGNAL ;
    PORT
      LAYER M4 ;
        RECT  21.516 37.68 21.6 37.704 ;
    END
  END o[185]
  PIN o[186]
    DIRECTION OUTPUT ;
    USE SIGNAL ;
    PORT
      LAYER M4 ;
        RECT  21.516 37.776 21.6 37.8 ;
    END
  END o[186]
  PIN o[187]
    DIRECTION OUTPUT ;
    USE SIGNAL ;
    PORT
      LAYER M4 ;
        RECT  21.516 37.872 21.6 37.896 ;
    END
  END o[187]
  PIN o[188]
    DIRECTION OUTPUT ;
    USE SIGNAL ;
    PORT
      LAYER M4 ;
        RECT  21.516 37.968 21.6 37.992 ;
    END
  END o[188]
  PIN o[189]
    DIRECTION OUTPUT ;
    USE SIGNAL ;
    PORT
      LAYER M4 ;
        RECT  21.516 38.064 21.6 38.088 ;
    END
  END o[189]
  PIN o[18]
    DIRECTION OUTPUT ;
    USE SIGNAL ;
    PORT
      LAYER M4 ;
        RECT  21.516 21.648 21.6 21.672 ;
    END
  END o[18]
  PIN o[190]
    DIRECTION OUTPUT ;
    USE SIGNAL ;
    PORT
      LAYER M4 ;
        RECT  21.516 38.16 21.6 38.184 ;
    END
  END o[190]
  PIN o[191]
    DIRECTION OUTPUT ;
    USE SIGNAL ;
    PORT
      LAYER M4 ;
        RECT  21.516 38.256 21.6 38.28 ;
    END
  END o[191]
  PIN o[192]
    DIRECTION OUTPUT ;
    USE SIGNAL ;
    PORT
      LAYER M4 ;
        RECT  21.516 3.792 21.6 3.816 ;
    END
  END o[192]
  PIN o[193]
    DIRECTION OUTPUT ;
    USE SIGNAL ;
    PORT
      LAYER M4 ;
        RECT  21.516 3.888 21.6 3.912 ;
    END
  END o[193]
  PIN o[194]
    DIRECTION OUTPUT ;
    USE SIGNAL ;
    PORT
      LAYER M4 ;
        RECT  21.516 3.984 21.6 4.008 ;
    END
  END o[194]
  PIN o[195]
    DIRECTION OUTPUT ;
    USE SIGNAL ;
    PORT
      LAYER M4 ;
        RECT  21.516 4.08 21.6 4.104 ;
    END
  END o[195]
  PIN o[196]
    DIRECTION OUTPUT ;
    USE SIGNAL ;
    PORT
      LAYER M4 ;
        RECT  21.516 4.176 21.6 4.2 ;
    END
  END o[196]
  PIN o[197]
    DIRECTION OUTPUT ;
    USE SIGNAL ;
    PORT
      LAYER M4 ;
        RECT  21.516 4.272 21.6 4.296 ;
    END
  END o[197]
  PIN o[198]
    DIRECTION OUTPUT ;
    USE SIGNAL ;
    PORT
      LAYER M4 ;
        RECT  21.516 4.368 21.6 4.392 ;
    END
  END o[198]
  PIN o[199]
    DIRECTION OUTPUT ;
    USE SIGNAL ;
    PORT
      LAYER M4 ;
        RECT  21.516 4.464 21.6 4.488 ;
    END
  END o[199]
  PIN o[19]
    DIRECTION OUTPUT ;
    USE SIGNAL ;
    PORT
      LAYER M4 ;
        RECT  21.516 21.744 21.6 21.768 ;
    END
  END o[19]
  PIN o[1]
    DIRECTION OUTPUT ;
    USE SIGNAL ;
    PORT
      LAYER M4 ;
        RECT  21.516 20.016 21.6 20.04 ;
    END
  END o[1]
  PIN o[200]
    DIRECTION OUTPUT ;
    USE SIGNAL ;
    PORT
      LAYER M4 ;
        RECT  21.516 4.56 21.6 4.584 ;
    END
  END o[200]
  PIN o[201]
    DIRECTION OUTPUT ;
    USE SIGNAL ;
    PORT
      LAYER M4 ;
        RECT  21.516 4.656 21.6 4.68 ;
    END
  END o[201]
  PIN o[202]
    DIRECTION OUTPUT ;
    USE SIGNAL ;
    PORT
      LAYER M4 ;
        RECT  21.516 4.752 21.6 4.776 ;
    END
  END o[202]
  PIN o[203]
    DIRECTION OUTPUT ;
    USE SIGNAL ;
    PORT
      LAYER M4 ;
        RECT  21.516 4.848 21.6 4.872 ;
    END
  END o[203]
  PIN o[204]
    DIRECTION OUTPUT ;
    USE SIGNAL ;
    PORT
      LAYER M4 ;
        RECT  21.516 4.944 21.6 4.968 ;
    END
  END o[204]
  PIN o[205]
    DIRECTION OUTPUT ;
    USE SIGNAL ;
    PORT
      LAYER M4 ;
        RECT  21.516 5.04 21.6 5.064 ;
    END
  END o[205]
  PIN o[206]
    DIRECTION OUTPUT ;
    USE SIGNAL ;
    PORT
      LAYER M4 ;
        RECT  21.516 5.136 21.6 5.16 ;
    END
  END o[206]
  PIN o[207]
    DIRECTION OUTPUT ;
    USE SIGNAL ;
    PORT
      LAYER M4 ;
        RECT  21.516 5.232 21.6 5.256 ;
    END
  END o[207]
  PIN o[208]
    DIRECTION OUTPUT ;
    USE SIGNAL ;
    PORT
      LAYER M4 ;
        RECT  21.516 5.328 21.6 5.352 ;
    END
  END o[208]
  PIN o[209]
    DIRECTION OUTPUT ;
    USE SIGNAL ;
    PORT
      LAYER M4 ;
        RECT  21.516 5.424 21.6 5.448 ;
    END
  END o[209]
  PIN o[20]
    DIRECTION OUTPUT ;
    USE SIGNAL ;
    PORT
      LAYER M4 ;
        RECT  21.516 21.84 21.6 21.864 ;
    END
  END o[20]
  PIN o[210]
    DIRECTION OUTPUT ;
    USE SIGNAL ;
    PORT
      LAYER M4 ;
        RECT  21.516 5.52 21.6 5.544 ;
    END
  END o[210]
  PIN o[211]
    DIRECTION OUTPUT ;
    USE SIGNAL ;
    PORT
      LAYER M4 ;
        RECT  21.516 5.616 21.6 5.64 ;
    END
  END o[211]
  PIN o[212]
    DIRECTION OUTPUT ;
    USE SIGNAL ;
    PORT
      LAYER M4 ;
        RECT  21.516 5.712 21.6 5.736 ;
    END
  END o[212]
  PIN o[213]
    DIRECTION OUTPUT ;
    USE SIGNAL ;
    PORT
      LAYER M4 ;
        RECT  21.516 5.808 21.6 5.832 ;
    END
  END o[213]
  PIN o[214]
    DIRECTION OUTPUT ;
    USE SIGNAL ;
    PORT
      LAYER M4 ;
        RECT  21.516 5.904 21.6 5.928 ;
    END
  END o[214]
  PIN o[215]
    DIRECTION OUTPUT ;
    USE SIGNAL ;
    PORT
      LAYER M4 ;
        RECT  21.516 6 21.6 6.024 ;
    END
  END o[215]
  PIN o[216]
    DIRECTION OUTPUT ;
    USE SIGNAL ;
    PORT
      LAYER M4 ;
        RECT  21.516 6.096 21.6 6.12 ;
    END
  END o[216]
  PIN o[217]
    DIRECTION OUTPUT ;
    USE SIGNAL ;
    PORT
      LAYER M4 ;
        RECT  21.516 6.192 21.6 6.216 ;
    END
  END o[217]
  PIN o[218]
    DIRECTION OUTPUT ;
    USE SIGNAL ;
    PORT
      LAYER M4 ;
        RECT  21.516 6.288 21.6 6.312 ;
    END
  END o[218]
  PIN o[219]
    DIRECTION OUTPUT ;
    USE SIGNAL ;
    PORT
      LAYER M4 ;
        RECT  21.516 6.384 21.6 6.408 ;
    END
  END o[219]
  PIN o[21]
    DIRECTION OUTPUT ;
    USE SIGNAL ;
    PORT
      LAYER M4 ;
        RECT  21.516 21.936 21.6 21.96 ;
    END
  END o[21]
  PIN o[220]
    DIRECTION OUTPUT ;
    USE SIGNAL ;
    PORT
      LAYER M4 ;
        RECT  21.516 6.48 21.6 6.504 ;
    END
  END o[220]
  PIN o[221]
    DIRECTION OUTPUT ;
    USE SIGNAL ;
    PORT
      LAYER M4 ;
        RECT  21.516 6.576 21.6 6.6 ;
    END
  END o[221]
  PIN o[222]
    DIRECTION OUTPUT ;
    USE SIGNAL ;
    PORT
      LAYER M4 ;
        RECT  21.516 6.672 21.6 6.696 ;
    END
  END o[222]
  PIN o[223]
    DIRECTION OUTPUT ;
    USE SIGNAL ;
    PORT
      LAYER M4 ;
        RECT  21.516 6.768 21.6 6.792 ;
    END
  END o[223]
  PIN o[224]
    DIRECTION OUTPUT ;
    USE SIGNAL ;
    PORT
      LAYER M4 ;
        RECT  21.516 6.864 21.6 6.888 ;
    END
  END o[224]
  PIN o[225]
    DIRECTION OUTPUT ;
    USE SIGNAL ;
    PORT
      LAYER M4 ;
        RECT  21.516 6.96 21.6 6.984 ;
    END
  END o[225]
  PIN o[226]
    DIRECTION OUTPUT ;
    USE SIGNAL ;
    PORT
      LAYER M4 ;
        RECT  21.516 7.056 21.6 7.08 ;
    END
  END o[226]
  PIN o[227]
    DIRECTION OUTPUT ;
    USE SIGNAL ;
    PORT
      LAYER M4 ;
        RECT  21.516 7.152 21.6 7.176 ;
    END
  END o[227]
  PIN o[228]
    DIRECTION OUTPUT ;
    USE SIGNAL ;
    PORT
      LAYER M4 ;
        RECT  21.516 7.248 21.6 7.272 ;
    END
  END o[228]
  PIN o[229]
    DIRECTION OUTPUT ;
    USE SIGNAL ;
    PORT
      LAYER M4 ;
        RECT  21.516 7.344 21.6 7.368 ;
    END
  END o[229]
  PIN o[22]
    DIRECTION OUTPUT ;
    USE SIGNAL ;
    PORT
      LAYER M4 ;
        RECT  21.516 22.032 21.6 22.056 ;
    END
  END o[22]
  PIN o[230]
    DIRECTION OUTPUT ;
    USE SIGNAL ;
    PORT
      LAYER M4 ;
        RECT  21.516 7.44 21.6 7.464 ;
    END
  END o[230]
  PIN o[231]
    DIRECTION OUTPUT ;
    USE SIGNAL ;
    PORT
      LAYER M4 ;
        RECT  21.516 7.536 21.6 7.56 ;
    END
  END o[231]
  PIN o[232]
    DIRECTION OUTPUT ;
    USE SIGNAL ;
    PORT
      LAYER M4 ;
        RECT  21.516 7.632 21.6 7.656 ;
    END
  END o[232]
  PIN o[233]
    DIRECTION OUTPUT ;
    USE SIGNAL ;
    PORT
      LAYER M4 ;
        RECT  21.516 7.728 21.6 7.752 ;
    END
  END o[233]
  PIN o[234]
    DIRECTION OUTPUT ;
    USE SIGNAL ;
    PORT
      LAYER M4 ;
        RECT  21.516 7.824 21.6 7.848 ;
    END
  END o[234]
  PIN o[235]
    DIRECTION OUTPUT ;
    USE SIGNAL ;
    PORT
      LAYER M4 ;
        RECT  21.516 7.92 21.6 7.944 ;
    END
  END o[235]
  PIN o[236]
    DIRECTION OUTPUT ;
    USE SIGNAL ;
    PORT
      LAYER M4 ;
        RECT  21.516 8.016 21.6 8.04 ;
    END
  END o[236]
  PIN o[237]
    DIRECTION OUTPUT ;
    USE SIGNAL ;
    PORT
      LAYER M4 ;
        RECT  21.516 8.112 21.6 8.136 ;
    END
  END o[237]
  PIN o[238]
    DIRECTION OUTPUT ;
    USE SIGNAL ;
    PORT
      LAYER M4 ;
        RECT  21.516 8.208 21.6 8.232 ;
    END
  END o[238]
  PIN o[239]
    DIRECTION OUTPUT ;
    USE SIGNAL ;
    PORT
      LAYER M4 ;
        RECT  21.516 8.304 21.6 8.328 ;
    END
  END o[239]
  PIN o[23]
    DIRECTION OUTPUT ;
    USE SIGNAL ;
    PORT
      LAYER M4 ;
        RECT  21.516 22.128 21.6 22.152 ;
    END
  END o[23]
  PIN o[240]
    DIRECTION OUTPUT ;
    USE SIGNAL ;
    PORT
      LAYER M4 ;
        RECT  21.516 8.4 21.6 8.424 ;
    END
  END o[240]
  PIN o[241]
    DIRECTION OUTPUT ;
    USE SIGNAL ;
    PORT
      LAYER M4 ;
        RECT  21.516 8.496 21.6 8.52 ;
    END
  END o[241]
  PIN o[242]
    DIRECTION OUTPUT ;
    USE SIGNAL ;
    PORT
      LAYER M4 ;
        RECT  21.516 8.592 21.6 8.616 ;
    END
  END o[242]
  PIN o[243]
    DIRECTION OUTPUT ;
    USE SIGNAL ;
    PORT
      LAYER M4 ;
        RECT  21.516 8.688 21.6 8.712 ;
    END
  END o[243]
  PIN o[244]
    DIRECTION OUTPUT ;
    USE SIGNAL ;
    PORT
      LAYER M4 ;
        RECT  21.516 8.784 21.6 8.808 ;
    END
  END o[244]
  PIN o[245]
    DIRECTION OUTPUT ;
    USE SIGNAL ;
    PORT
      LAYER M4 ;
        RECT  21.516 8.88 21.6 8.904 ;
    END
  END o[245]
  PIN o[246]
    DIRECTION OUTPUT ;
    USE SIGNAL ;
    PORT
      LAYER M4 ;
        RECT  21.516 8.976 21.6 9 ;
    END
  END o[246]
  PIN o[247]
    DIRECTION OUTPUT ;
    USE SIGNAL ;
    PORT
      LAYER M4 ;
        RECT  21.516 9.072 21.6 9.096 ;
    END
  END o[247]
  PIN o[248]
    DIRECTION OUTPUT ;
    USE SIGNAL ;
    PORT
      LAYER M4 ;
        RECT  21.516 9.168 21.6 9.192 ;
    END
  END o[248]
  PIN o[249]
    DIRECTION OUTPUT ;
    USE SIGNAL ;
    PORT
      LAYER M4 ;
        RECT  21.516 9.264 21.6 9.288 ;
    END
  END o[249]
  PIN o[24]
    DIRECTION OUTPUT ;
    USE SIGNAL ;
    PORT
      LAYER M4 ;
        RECT  21.516 22.224 21.6 22.248 ;
    END
  END o[24]
  PIN o[250]
    DIRECTION OUTPUT ;
    USE SIGNAL ;
    PORT
      LAYER M4 ;
        RECT  21.516 9.36 21.6 9.384 ;
    END
  END o[250]
  PIN o[251]
    DIRECTION OUTPUT ;
    USE SIGNAL ;
    PORT
      LAYER M4 ;
        RECT  21.516 9.456 21.6 9.48 ;
    END
  END o[251]
  PIN o[252]
    DIRECTION OUTPUT ;
    USE SIGNAL ;
    PORT
      LAYER M4 ;
        RECT  21.516 9.552 21.6 9.576 ;
    END
  END o[252]
  PIN o[253]
    DIRECTION OUTPUT ;
    USE SIGNAL ;
    PORT
      LAYER M4 ;
        RECT  21.516 9.648 21.6 9.672 ;
    END
  END o[253]
  PIN o[254]
    DIRECTION OUTPUT ;
    USE SIGNAL ;
    PORT
      LAYER M4 ;
        RECT  21.516 9.744 21.6 9.768 ;
    END
  END o[254]
  PIN o[255]
    DIRECTION OUTPUT ;
    USE SIGNAL ;
    PORT
      LAYER M4 ;
        RECT  21.516 9.84 21.6 9.864 ;
    END
  END o[255]
  PIN o[256]
    DIRECTION OUTPUT ;
    USE SIGNAL ;
    PORT
      LAYER M4 ;
        RECT  21.516 39.12 21.6 39.144 ;
    END
  END o[256]
  PIN o[257]
    DIRECTION OUTPUT ;
    USE SIGNAL ;
    PORT
      LAYER M4 ;
        RECT  21.516 39.216 21.6 39.24 ;
    END
  END o[257]
  PIN o[258]
    DIRECTION OUTPUT ;
    USE SIGNAL ;
    PORT
      LAYER M4 ;
        RECT  21.516 39.312 21.6 39.336 ;
    END
  END o[258]
  PIN o[259]
    DIRECTION OUTPUT ;
    USE SIGNAL ;
    PORT
      LAYER M4 ;
        RECT  21.516 39.408 21.6 39.432 ;
    END
  END o[259]
  PIN o[25]
    DIRECTION OUTPUT ;
    USE SIGNAL ;
    PORT
      LAYER M4 ;
        RECT  21.516 22.32 21.6 22.344 ;
    END
  END o[25]
  PIN o[260]
    DIRECTION OUTPUT ;
    USE SIGNAL ;
    PORT
      LAYER M4 ;
        RECT  21.516 39.504 21.6 39.528 ;
    END
  END o[260]
  PIN o[261]
    DIRECTION OUTPUT ;
    USE SIGNAL ;
    PORT
      LAYER M4 ;
        RECT  21.516 39.6 21.6 39.624 ;
    END
  END o[261]
  PIN o[262]
    DIRECTION OUTPUT ;
    USE SIGNAL ;
    PORT
      LAYER M4 ;
        RECT  21.516 39.696 21.6 39.72 ;
    END
  END o[262]
  PIN o[263]
    DIRECTION OUTPUT ;
    USE SIGNAL ;
    PORT
      LAYER M4 ;
        RECT  21.516 39.792 21.6 39.816 ;
    END
  END o[263]
  PIN o[264]
    DIRECTION OUTPUT ;
    USE SIGNAL ;
    PORT
      LAYER M4 ;
        RECT  21.516 39.888 21.6 39.912 ;
    END
  END o[264]
  PIN o[265]
    DIRECTION OUTPUT ;
    USE SIGNAL ;
    PORT
      LAYER M4 ;
        RECT  21.516 39.984 21.6 40.008 ;
    END
  END o[265]
  PIN o[266]
    DIRECTION OUTPUT ;
    USE SIGNAL ;
    PORT
      LAYER M4 ;
        RECT  21.516 40.08 21.6 40.104 ;
    END
  END o[266]
  PIN o[267]
    DIRECTION OUTPUT ;
    USE SIGNAL ;
    PORT
      LAYER M4 ;
        RECT  21.516 40.176 21.6 40.2 ;
    END
  END o[267]
  PIN o[268]
    DIRECTION OUTPUT ;
    USE SIGNAL ;
    PORT
      LAYER M4 ;
        RECT  21.516 40.272 21.6 40.296 ;
    END
  END o[268]
  PIN o[269]
    DIRECTION OUTPUT ;
    USE SIGNAL ;
    PORT
      LAYER M4 ;
        RECT  21.516 40.368 21.6 40.392 ;
    END
  END o[269]
  PIN o[26]
    DIRECTION OUTPUT ;
    USE SIGNAL ;
    PORT
      LAYER M4 ;
        RECT  21.516 22.416 21.6 22.44 ;
    END
  END o[26]
  PIN o[270]
    DIRECTION OUTPUT ;
    USE SIGNAL ;
    PORT
      LAYER M4 ;
        RECT  21.516 40.464 21.6 40.488 ;
    END
  END o[270]
  PIN o[271]
    DIRECTION OUTPUT ;
    USE SIGNAL ;
    PORT
      LAYER M4 ;
        RECT  21.516 40.56 21.6 40.584 ;
    END
  END o[271]
  PIN o[272]
    DIRECTION OUTPUT ;
    USE SIGNAL ;
    PORT
      LAYER M4 ;
        RECT  21.516 40.656 21.6 40.68 ;
    END
  END o[272]
  PIN o[273]
    DIRECTION OUTPUT ;
    USE SIGNAL ;
    PORT
      LAYER M4 ;
        RECT  21.516 40.752 21.6 40.776 ;
    END
  END o[273]
  PIN o[274]
    DIRECTION OUTPUT ;
    USE SIGNAL ;
    PORT
      LAYER M4 ;
        RECT  21.516 40.848 21.6 40.872 ;
    END
  END o[274]
  PIN o[275]
    DIRECTION OUTPUT ;
    USE SIGNAL ;
    PORT
      LAYER M4 ;
        RECT  21.516 40.944 21.6 40.968 ;
    END
  END o[275]
  PIN o[276]
    DIRECTION OUTPUT ;
    USE SIGNAL ;
    PORT
      LAYER M4 ;
        RECT  21.516 41.04 21.6 41.064 ;
    END
  END o[276]
  PIN o[277]
    DIRECTION OUTPUT ;
    USE SIGNAL ;
    PORT
      LAYER M4 ;
        RECT  21.516 41.136 21.6 41.16 ;
    END
  END o[277]
  PIN o[278]
    DIRECTION OUTPUT ;
    USE SIGNAL ;
    PORT
      LAYER M4 ;
        RECT  21.516 41.232 21.6 41.256 ;
    END
  END o[278]
  PIN o[279]
    DIRECTION OUTPUT ;
    USE SIGNAL ;
    PORT
      LAYER M4 ;
        RECT  21.516 41.328 21.6 41.352 ;
    END
  END o[279]
  PIN o[27]
    DIRECTION OUTPUT ;
    USE SIGNAL ;
    PORT
      LAYER M4 ;
        RECT  21.516 22.512 21.6 22.536 ;
    END
  END o[27]
  PIN o[280]
    DIRECTION OUTPUT ;
    USE SIGNAL ;
    PORT
      LAYER M4 ;
        RECT  21.516 41.424 21.6 41.448 ;
    END
  END o[280]
  PIN o[281]
    DIRECTION OUTPUT ;
    USE SIGNAL ;
    PORT
      LAYER M4 ;
        RECT  21.516 41.52 21.6 41.544 ;
    END
  END o[281]
  PIN o[282]
    DIRECTION OUTPUT ;
    USE SIGNAL ;
    PORT
      LAYER M4 ;
        RECT  21.516 41.616 21.6 41.64 ;
    END
  END o[282]
  PIN o[283]
    DIRECTION OUTPUT ;
    USE SIGNAL ;
    PORT
      LAYER M4 ;
        RECT  21.516 41.712 21.6 41.736 ;
    END
  END o[283]
  PIN o[284]
    DIRECTION OUTPUT ;
    USE SIGNAL ;
    PORT
      LAYER M4 ;
        RECT  21.516 41.808 21.6 41.832 ;
    END
  END o[284]
  PIN o[285]
    DIRECTION OUTPUT ;
    USE SIGNAL ;
    PORT
      LAYER M4 ;
        RECT  21.516 41.904 21.6 41.928 ;
    END
  END o[285]
  PIN o[286]
    DIRECTION OUTPUT ;
    USE SIGNAL ;
    PORT
      LAYER M4 ;
        RECT  21.516 42 21.6 42.024 ;
    END
  END o[286]
  PIN o[287]
    DIRECTION OUTPUT ;
    USE SIGNAL ;
    PORT
      LAYER M4 ;
        RECT  21.516 42.096 21.6 42.12 ;
    END
  END o[287]
  PIN o[288]
    DIRECTION OUTPUT ;
    USE SIGNAL ;
    PORT
      LAYER M4 ;
        RECT  21.516 45.264 21.6 45.288 ;
    END
  END o[288]
  PIN o[289]
    DIRECTION OUTPUT ;
    USE SIGNAL ;
    PORT
      LAYER M4 ;
        RECT  21.516 45.36 21.6 45.384 ;
    END
  END o[289]
  PIN o[28]
    DIRECTION OUTPUT ;
    USE SIGNAL ;
    PORT
      LAYER M4 ;
        RECT  21.516 22.608 21.6 22.632 ;
    END
  END o[28]
  PIN o[290]
    DIRECTION OUTPUT ;
    USE SIGNAL ;
    PORT
      LAYER M4 ;
        RECT  21.516 45.456 21.6 45.48 ;
    END
  END o[290]
  PIN o[291]
    DIRECTION OUTPUT ;
    USE SIGNAL ;
    PORT
      LAYER M4 ;
        RECT  21.516 45.552 21.6 45.576 ;
    END
  END o[291]
  PIN o[292]
    DIRECTION OUTPUT ;
    USE SIGNAL ;
    PORT
      LAYER M4 ;
        RECT  21.516 45.648 21.6 45.672 ;
    END
  END o[292]
  PIN o[293]
    DIRECTION OUTPUT ;
    USE SIGNAL ;
    PORT
      LAYER M4 ;
        RECT  21.516 45.744 21.6 45.768 ;
    END
  END o[293]
  PIN o[294]
    DIRECTION OUTPUT ;
    USE SIGNAL ;
    PORT
      LAYER M4 ;
        RECT  21.516 45.84 21.6 45.864 ;
    END
  END o[294]
  PIN o[295]
    DIRECTION OUTPUT ;
    USE SIGNAL ;
    PORT
      LAYER M4 ;
        RECT  21.516 45.936 21.6 45.96 ;
    END
  END o[295]
  PIN o[296]
    DIRECTION OUTPUT ;
    USE SIGNAL ;
    PORT
      LAYER M4 ;
        RECT  21.516 46.032 21.6 46.056 ;
    END
  END o[296]
  PIN o[297]
    DIRECTION OUTPUT ;
    USE SIGNAL ;
    PORT
      LAYER M4 ;
        RECT  21.516 46.128 21.6 46.152 ;
    END
  END o[297]
  PIN o[298]
    DIRECTION OUTPUT ;
    USE SIGNAL ;
    PORT
      LAYER M4 ;
        RECT  21.516 46.224 21.6 46.248 ;
    END
  END o[298]
  PIN o[299]
    DIRECTION OUTPUT ;
    USE SIGNAL ;
    PORT
      LAYER M4 ;
        RECT  21.516 46.32 21.6 46.344 ;
    END
  END o[299]
  PIN o[29]
    DIRECTION OUTPUT ;
    USE SIGNAL ;
    PORT
      LAYER M4 ;
        RECT  21.516 22.704 21.6 22.728 ;
    END
  END o[29]
  PIN o[2]
    DIRECTION OUTPUT ;
    USE SIGNAL ;
    PORT
      LAYER M4 ;
        RECT  21.516 20.112 21.6 20.136 ;
    END
  END o[2]
  PIN o[300]
    DIRECTION OUTPUT ;
    USE SIGNAL ;
    PORT
      LAYER M4 ;
        RECT  21.516 46.416 21.6 46.44 ;
    END
  END o[300]
  PIN o[301]
    DIRECTION OUTPUT ;
    USE SIGNAL ;
    PORT
      LAYER M4 ;
        RECT  21.516 46.512 21.6 46.536 ;
    END
  END o[301]
  PIN o[302]
    DIRECTION OUTPUT ;
    USE SIGNAL ;
    PORT
      LAYER M4 ;
        RECT  21.516 46.608 21.6 46.632 ;
    END
  END o[302]
  PIN o[303]
    DIRECTION OUTPUT ;
    USE SIGNAL ;
    PORT
      LAYER M4 ;
        RECT  21.516 46.704 21.6 46.728 ;
    END
  END o[303]
  PIN o[304]
    DIRECTION OUTPUT ;
    USE SIGNAL ;
    PORT
      LAYER M4 ;
        RECT  21.516 46.8 21.6 46.824 ;
    END
  END o[304]
  PIN o[305]
    DIRECTION OUTPUT ;
    USE SIGNAL ;
    PORT
      LAYER M4 ;
        RECT  21.516 46.896 21.6 46.92 ;
    END
  END o[305]
  PIN o[306]
    DIRECTION OUTPUT ;
    USE SIGNAL ;
    PORT
      LAYER M4 ;
        RECT  21.516 46.992 21.6 47.016 ;
    END
  END o[306]
  PIN o[307]
    DIRECTION OUTPUT ;
    USE SIGNAL ;
    PORT
      LAYER M4 ;
        RECT  21.516 47.088 21.6 47.112 ;
    END
  END o[307]
  PIN o[308]
    DIRECTION OUTPUT ;
    USE SIGNAL ;
    PORT
      LAYER M4 ;
        RECT  21.516 47.184 21.6 47.208 ;
    END
  END o[308]
  PIN o[309]
    DIRECTION OUTPUT ;
    USE SIGNAL ;
    PORT
      LAYER M4 ;
        RECT  21.516 47.28 21.6 47.304 ;
    END
  END o[309]
  PIN o[30]
    DIRECTION OUTPUT ;
    USE SIGNAL ;
    PORT
      LAYER M4 ;
        RECT  21.516 22.8 21.6 22.824 ;
    END
  END o[30]
  PIN o[310]
    DIRECTION OUTPUT ;
    USE SIGNAL ;
    PORT
      LAYER M4 ;
        RECT  21.516 47.376 21.6 47.4 ;
    END
  END o[310]
  PIN o[311]
    DIRECTION OUTPUT ;
    USE SIGNAL ;
    PORT
      LAYER M4 ;
        RECT  21.516 47.472 21.6 47.496 ;
    END
  END o[311]
  PIN o[312]
    DIRECTION OUTPUT ;
    USE SIGNAL ;
    PORT
      LAYER M4 ;
        RECT  21.516 47.568 21.6 47.592 ;
    END
  END o[312]
  PIN o[313]
    DIRECTION OUTPUT ;
    USE SIGNAL ;
    PORT
      LAYER M4 ;
        RECT  21.516 47.664 21.6 47.688 ;
    END
  END o[313]
  PIN o[314]
    DIRECTION OUTPUT ;
    USE SIGNAL ;
    PORT
      LAYER M4 ;
        RECT  21.516 47.76 21.6 47.784 ;
    END
  END o[314]
  PIN o[315]
    DIRECTION OUTPUT ;
    USE SIGNAL ;
    PORT
      LAYER M4 ;
        RECT  21.516 47.856 21.6 47.88 ;
    END
  END o[315]
  PIN o[316]
    DIRECTION OUTPUT ;
    USE SIGNAL ;
    PORT
      LAYER M4 ;
        RECT  21.516 47.952 21.6 47.976 ;
    END
  END o[316]
  PIN o[317]
    DIRECTION OUTPUT ;
    USE SIGNAL ;
    PORT
      LAYER M4 ;
        RECT  21.516 48.048 21.6 48.072 ;
    END
  END o[317]
  PIN o[318]
    DIRECTION OUTPUT ;
    USE SIGNAL ;
    PORT
      LAYER M4 ;
        RECT  21.516 48.144 21.6 48.168 ;
    END
  END o[318]
  PIN o[319]
    DIRECTION OUTPUT ;
    USE SIGNAL ;
    PORT
      LAYER M4 ;
        RECT  21.516 48.24 21.6 48.264 ;
    END
  END o[319]
  PIN o[31]
    DIRECTION OUTPUT ;
    USE SIGNAL ;
    PORT
      LAYER M4 ;
        RECT  21.516 22.896 21.6 22.92 ;
    END
  END o[31]
  PIN o[320]
    DIRECTION OUTPUT ;
    USE SIGNAL ;
    PORT
      LAYER M4 ;
        RECT  21.516 48.336 21.6 48.36 ;
    END
  END o[320]
  PIN o[321]
    DIRECTION OUTPUT ;
    USE SIGNAL ;
    PORT
      LAYER M4 ;
        RECT  21.516 48.432 21.6 48.456 ;
    END
  END o[321]
  PIN o[322]
    DIRECTION OUTPUT ;
    USE SIGNAL ;
    PORT
      LAYER M4 ;
        RECT  21.516 48.528 21.6 48.552 ;
    END
  END o[322]
  PIN o[323]
    DIRECTION OUTPUT ;
    USE SIGNAL ;
    PORT
      LAYER M4 ;
        RECT  21.516 48.624 21.6 48.648 ;
    END
  END o[323]
  PIN o[324]
    DIRECTION OUTPUT ;
    USE SIGNAL ;
    PORT
      LAYER M4 ;
        RECT  21.516 48.72 21.6 48.744 ;
    END
  END o[324]
  PIN o[325]
    DIRECTION OUTPUT ;
    USE SIGNAL ;
    PORT
      LAYER M4 ;
        RECT  21.516 48.816 21.6 48.84 ;
    END
  END o[325]
  PIN o[326]
    DIRECTION OUTPUT ;
    USE SIGNAL ;
    PORT
      LAYER M4 ;
        RECT  21.516 48.912 21.6 48.936 ;
    END
  END o[326]
  PIN o[327]
    DIRECTION OUTPUT ;
    USE SIGNAL ;
    PORT
      LAYER M4 ;
        RECT  21.516 49.008 21.6 49.032 ;
    END
  END o[327]
  PIN o[328]
    DIRECTION OUTPUT ;
    USE SIGNAL ;
    PORT
      LAYER M4 ;
        RECT  21.516 49.104 21.6 49.128 ;
    END
  END o[328]
  PIN o[329]
    DIRECTION OUTPUT ;
    USE SIGNAL ;
    PORT
      LAYER M4 ;
        RECT  21.516 49.2 21.6 49.224 ;
    END
  END o[329]
  PIN o[32]
    DIRECTION OUTPUT ;
    USE SIGNAL ;
    PORT
      LAYER M4 ;
        RECT  21.516 22.992 21.6 23.016 ;
    END
  END o[32]
  PIN o[330]
    DIRECTION OUTPUT ;
    USE SIGNAL ;
    PORT
      LAYER M4 ;
        RECT  21.516 49.296 21.6 49.32 ;
    END
  END o[330]
  PIN o[331]
    DIRECTION OUTPUT ;
    USE SIGNAL ;
    PORT
      LAYER M4 ;
        RECT  21.516 49.392 21.6 49.416 ;
    END
  END o[331]
  PIN o[332]
    DIRECTION OUTPUT ;
    USE SIGNAL ;
    PORT
      LAYER M4 ;
        RECT  21.516 49.488 21.6 49.512 ;
    END
  END o[332]
  PIN o[333]
    DIRECTION OUTPUT ;
    USE SIGNAL ;
    PORT
      LAYER M4 ;
        RECT  21.516 49.584 21.6 49.608 ;
    END
  END o[333]
  PIN o[334]
    DIRECTION OUTPUT ;
    USE SIGNAL ;
    PORT
      LAYER M4 ;
        RECT  21.516 49.68 21.6 49.704 ;
    END
  END o[334]
  PIN o[335]
    DIRECTION OUTPUT ;
    USE SIGNAL ;
    PORT
      LAYER M4 ;
        RECT  21.516 49.776 21.6 49.8 ;
    END
  END o[335]
  PIN o[336]
    DIRECTION OUTPUT ;
    USE SIGNAL ;
    PORT
      LAYER M4 ;
        RECT  21.516 49.872 21.6 49.896 ;
    END
  END o[336]
  PIN o[337]
    DIRECTION OUTPUT ;
    USE SIGNAL ;
    PORT
      LAYER M4 ;
        RECT  21.516 49.968 21.6 49.992 ;
    END
  END o[337]
  PIN o[338]
    DIRECTION OUTPUT ;
    USE SIGNAL ;
    PORT
      LAYER M4 ;
        RECT  21.516 50.064 21.6 50.088 ;
    END
  END o[338]
  PIN o[339]
    DIRECTION OUTPUT ;
    USE SIGNAL ;
    PORT
      LAYER M4 ;
        RECT  21.516 50.16 21.6 50.184 ;
    END
  END o[339]
  PIN o[33]
    DIRECTION OUTPUT ;
    USE SIGNAL ;
    PORT
      LAYER M4 ;
        RECT  21.516 23.088 21.6 23.112 ;
    END
  END o[33]
  PIN o[340]
    DIRECTION OUTPUT ;
    USE SIGNAL ;
    PORT
      LAYER M4 ;
        RECT  21.516 50.256 21.6 50.28 ;
    END
  END o[340]
  PIN o[341]
    DIRECTION OUTPUT ;
    USE SIGNAL ;
    PORT
      LAYER M4 ;
        RECT  21.516 50.352 21.6 50.376 ;
    END
  END o[341]
  PIN o[342]
    DIRECTION OUTPUT ;
    USE SIGNAL ;
    PORT
      LAYER M4 ;
        RECT  21.516 50.448 21.6 50.472 ;
    END
  END o[342]
  PIN o[343]
    DIRECTION OUTPUT ;
    USE SIGNAL ;
    PORT
      LAYER M4 ;
        RECT  21.516 50.544 21.6 50.568 ;
    END
  END o[343]
  PIN o[344]
    DIRECTION OUTPUT ;
    USE SIGNAL ;
    PORT
      LAYER M4 ;
        RECT  21.516 50.64 21.6 50.664 ;
    END
  END o[344]
  PIN o[345]
    DIRECTION OUTPUT ;
    USE SIGNAL ;
    PORT
      LAYER M4 ;
        RECT  21.516 50.736 21.6 50.76 ;
    END
  END o[345]
  PIN o[346]
    DIRECTION OUTPUT ;
    USE SIGNAL ;
    PORT
      LAYER M4 ;
        RECT  21.516 50.832 21.6 50.856 ;
    END
  END o[346]
  PIN o[347]
    DIRECTION OUTPUT ;
    USE SIGNAL ;
    PORT
      LAYER M4 ;
        RECT  21.516 50.928 21.6 50.952 ;
    END
  END o[347]
  PIN o[348]
    DIRECTION OUTPUT ;
    USE SIGNAL ;
    PORT
      LAYER M4 ;
        RECT  21.516 51.024 21.6 51.048 ;
    END
  END o[348]
  PIN o[349]
    DIRECTION OUTPUT ;
    USE SIGNAL ;
    PORT
      LAYER M4 ;
        RECT  21.516 51.12 21.6 51.144 ;
    END
  END o[349]
  PIN o[34]
    DIRECTION OUTPUT ;
    USE SIGNAL ;
    PORT
      LAYER M4 ;
        RECT  21.516 23.184 21.6 23.208 ;
    END
  END o[34]
  PIN o[350]
    DIRECTION OUTPUT ;
    USE SIGNAL ;
    PORT
      LAYER M4 ;
        RECT  21.516 51.216 21.6 51.24 ;
    END
  END o[350]
  PIN o[351]
    DIRECTION OUTPUT ;
    USE SIGNAL ;
    PORT
      LAYER M4 ;
        RECT  21.516 51.312 21.6 51.336 ;
    END
  END o[351]
  PIN o[352]
    DIRECTION OUTPUT ;
    USE SIGNAL ;
    PORT
      LAYER M4 ;
        RECT  21.516 54.48 21.6 54.504 ;
    END
  END o[352]
  PIN o[353]
    DIRECTION OUTPUT ;
    USE SIGNAL ;
    PORT
      LAYER M4 ;
        RECT  21.516 54.576 21.6 54.6 ;
    END
  END o[353]
  PIN o[354]
    DIRECTION OUTPUT ;
    USE SIGNAL ;
    PORT
      LAYER M4 ;
        RECT  21.516 54.672 21.6 54.696 ;
    END
  END o[354]
  PIN o[355]
    DIRECTION OUTPUT ;
    USE SIGNAL ;
    PORT
      LAYER M4 ;
        RECT  21.516 54.768 21.6 54.792 ;
    END
  END o[355]
  PIN o[356]
    DIRECTION OUTPUT ;
    USE SIGNAL ;
    PORT
      LAYER M4 ;
        RECT  21.516 54.864 21.6 54.888 ;
    END
  END o[356]
  PIN o[357]
    DIRECTION OUTPUT ;
    USE SIGNAL ;
    PORT
      LAYER M4 ;
        RECT  21.516 54.96 21.6 54.984 ;
    END
  END o[357]
  PIN o[358]
    DIRECTION OUTPUT ;
    USE SIGNAL ;
    PORT
      LAYER M4 ;
        RECT  21.516 55.056 21.6 55.08 ;
    END
  END o[358]
  PIN o[359]
    DIRECTION OUTPUT ;
    USE SIGNAL ;
    PORT
      LAYER M4 ;
        RECT  21.516 55.152 21.6 55.176 ;
    END
  END o[359]
  PIN o[35]
    DIRECTION OUTPUT ;
    USE SIGNAL ;
    PORT
      LAYER M4 ;
        RECT  21.516 23.28 21.6 23.304 ;
    END
  END o[35]
  PIN o[360]
    DIRECTION OUTPUT ;
    USE SIGNAL ;
    PORT
      LAYER M4 ;
        RECT  21.516 55.248 21.6 55.272 ;
    END
  END o[360]
  PIN o[361]
    DIRECTION OUTPUT ;
    USE SIGNAL ;
    PORT
      LAYER M4 ;
        RECT  21.516 55.344 21.6 55.368 ;
    END
  END o[361]
  PIN o[362]
    DIRECTION OUTPUT ;
    USE SIGNAL ;
    PORT
      LAYER M4 ;
        RECT  21.516 55.44 21.6 55.464 ;
    END
  END o[362]
  PIN o[363]
    DIRECTION OUTPUT ;
    USE SIGNAL ;
    PORT
      LAYER M4 ;
        RECT  21.516 55.536 21.6 55.56 ;
    END
  END o[363]
  PIN o[364]
    DIRECTION OUTPUT ;
    USE SIGNAL ;
    PORT
      LAYER M4 ;
        RECT  21.516 55.632 21.6 55.656 ;
    END
  END o[364]
  PIN o[365]
    DIRECTION OUTPUT ;
    USE SIGNAL ;
    PORT
      LAYER M4 ;
        RECT  21.516 55.728 21.6 55.752 ;
    END
  END o[365]
  PIN o[366]
    DIRECTION OUTPUT ;
    USE SIGNAL ;
    PORT
      LAYER M4 ;
        RECT  21.516 55.824 21.6 55.848 ;
    END
  END o[366]
  PIN o[367]
    DIRECTION OUTPUT ;
    USE SIGNAL ;
    PORT
      LAYER M4 ;
        RECT  21.516 55.92 21.6 55.944 ;
    END
  END o[367]
  PIN o[368]
    DIRECTION OUTPUT ;
    USE SIGNAL ;
    PORT
      LAYER M4 ;
        RECT  21.516 56.016 21.6 56.04 ;
    END
  END o[368]
  PIN o[369]
    DIRECTION OUTPUT ;
    USE SIGNAL ;
    PORT
      LAYER M4 ;
        RECT  21.516 56.112 21.6 56.136 ;
    END
  END o[369]
  PIN o[36]
    DIRECTION OUTPUT ;
    USE SIGNAL ;
    PORT
      LAYER M4 ;
        RECT  21.516 23.376 21.6 23.4 ;
    END
  END o[36]
  PIN o[370]
    DIRECTION OUTPUT ;
    USE SIGNAL ;
    PORT
      LAYER M4 ;
        RECT  21.516 56.208 21.6 56.232 ;
    END
  END o[370]
  PIN o[371]
    DIRECTION OUTPUT ;
    USE SIGNAL ;
    PORT
      LAYER M4 ;
        RECT  21.516 56.304 21.6 56.328 ;
    END
  END o[371]
  PIN o[372]
    DIRECTION OUTPUT ;
    USE SIGNAL ;
    PORT
      LAYER M4 ;
        RECT  21.516 56.4 21.6 56.424 ;
    END
  END o[372]
  PIN o[373]
    DIRECTION OUTPUT ;
    USE SIGNAL ;
    PORT
      LAYER M4 ;
        RECT  21.516 56.496 21.6 56.52 ;
    END
  END o[373]
  PIN o[374]
    DIRECTION OUTPUT ;
    USE SIGNAL ;
    PORT
      LAYER M4 ;
        RECT  21.516 56.592 21.6 56.616 ;
    END
  END o[374]
  PIN o[375]
    DIRECTION OUTPUT ;
    USE SIGNAL ;
    PORT
      LAYER M4 ;
        RECT  21.516 56.688 21.6 56.712 ;
    END
  END o[375]
  PIN o[376]
    DIRECTION OUTPUT ;
    USE SIGNAL ;
    PORT
      LAYER M4 ;
        RECT  21.516 56.784 21.6 56.808 ;
    END
  END o[376]
  PIN o[377]
    DIRECTION OUTPUT ;
    USE SIGNAL ;
    PORT
      LAYER M4 ;
        RECT  21.516 56.88 21.6 56.904 ;
    END
  END o[377]
  PIN o[378]
    DIRECTION OUTPUT ;
    USE SIGNAL ;
    PORT
      LAYER M4 ;
        RECT  21.516 56.976 21.6 57 ;
    END
  END o[378]
  PIN o[379]
    DIRECTION OUTPUT ;
    USE SIGNAL ;
    PORT
      LAYER M4 ;
        RECT  21.516 57.072 21.6 57.096 ;
    END
  END o[379]
  PIN o[37]
    DIRECTION OUTPUT ;
    USE SIGNAL ;
    PORT
      LAYER M4 ;
        RECT  21.516 23.472 21.6 23.496 ;
    END
  END o[37]
  PIN o[380]
    DIRECTION OUTPUT ;
    USE SIGNAL ;
    PORT
      LAYER M4 ;
        RECT  21.516 57.168 21.6 57.192 ;
    END
  END o[380]
  PIN o[381]
    DIRECTION OUTPUT ;
    USE SIGNAL ;
    PORT
      LAYER M4 ;
        RECT  21.516 57.264 21.6 57.288 ;
    END
  END o[381]
  PIN o[382]
    DIRECTION OUTPUT ;
    USE SIGNAL ;
    PORT
      LAYER M4 ;
        RECT  21.516 57.36 21.6 57.384 ;
    END
  END o[382]
  PIN o[383]
    DIRECTION OUTPUT ;
    USE SIGNAL ;
    PORT
      LAYER M4 ;
        RECT  21.516 57.456 21.6 57.48 ;
    END
  END o[383]
  PIN o[384]
    DIRECTION OUTPUT ;
    USE SIGNAL ;
    PORT
      LAYER M4 ;
        RECT  21.516 42.192 21.6 42.216 ;
    END
  END o[384]
  PIN o[385]
    DIRECTION OUTPUT ;
    USE SIGNAL ;
    PORT
      LAYER M4 ;
        RECT  21.516 42.288 21.6 42.312 ;
    END
  END o[385]
  PIN o[386]
    DIRECTION OUTPUT ;
    USE SIGNAL ;
    PORT
      LAYER M4 ;
        RECT  21.516 42.384 21.6 42.408 ;
    END
  END o[386]
  PIN o[387]
    DIRECTION OUTPUT ;
    USE SIGNAL ;
    PORT
      LAYER M4 ;
        RECT  21.516 42.48 21.6 42.504 ;
    END
  END o[387]
  PIN o[388]
    DIRECTION OUTPUT ;
    USE SIGNAL ;
    PORT
      LAYER M4 ;
        RECT  21.516 42.576 21.6 42.6 ;
    END
  END o[388]
  PIN o[389]
    DIRECTION OUTPUT ;
    USE SIGNAL ;
    PORT
      LAYER M4 ;
        RECT  21.516 42.672 21.6 42.696 ;
    END
  END o[389]
  PIN o[38]
    DIRECTION OUTPUT ;
    USE SIGNAL ;
    PORT
      LAYER M4 ;
        RECT  21.516 23.568 21.6 23.592 ;
    END
  END o[38]
  PIN o[390]
    DIRECTION OUTPUT ;
    USE SIGNAL ;
    PORT
      LAYER M4 ;
        RECT  21.516 42.768 21.6 42.792 ;
    END
  END o[390]
  PIN o[391]
    DIRECTION OUTPUT ;
    USE SIGNAL ;
    PORT
      LAYER M4 ;
        RECT  21.516 42.864 21.6 42.888 ;
    END
  END o[391]
  PIN o[392]
    DIRECTION OUTPUT ;
    USE SIGNAL ;
    PORT
      LAYER M4 ;
        RECT  21.516 42.96 21.6 42.984 ;
    END
  END o[392]
  PIN o[393]
    DIRECTION OUTPUT ;
    USE SIGNAL ;
    PORT
      LAYER M4 ;
        RECT  21.516 43.056 21.6 43.08 ;
    END
  END o[393]
  PIN o[394]
    DIRECTION OUTPUT ;
    USE SIGNAL ;
    PORT
      LAYER M4 ;
        RECT  21.516 43.152 21.6 43.176 ;
    END
  END o[394]
  PIN o[395]
    DIRECTION OUTPUT ;
    USE SIGNAL ;
    PORT
      LAYER M4 ;
        RECT  21.516 43.248 21.6 43.272 ;
    END
  END o[395]
  PIN o[396]
    DIRECTION OUTPUT ;
    USE SIGNAL ;
    PORT
      LAYER M4 ;
        RECT  21.516 43.344 21.6 43.368 ;
    END
  END o[396]
  PIN o[397]
    DIRECTION OUTPUT ;
    USE SIGNAL ;
    PORT
      LAYER M4 ;
        RECT  21.516 43.44 21.6 43.464 ;
    END
  END o[397]
  PIN o[398]
    DIRECTION OUTPUT ;
    USE SIGNAL ;
    PORT
      LAYER M4 ;
        RECT  21.516 43.536 21.6 43.56 ;
    END
  END o[398]
  PIN o[399]
    DIRECTION OUTPUT ;
    USE SIGNAL ;
    PORT
      LAYER M4 ;
        RECT  21.516 43.632 21.6 43.656 ;
    END
  END o[399]
  PIN o[39]
    DIRECTION OUTPUT ;
    USE SIGNAL ;
    PORT
      LAYER M4 ;
        RECT  21.516 23.664 21.6 23.688 ;
    END
  END o[39]
  PIN o[3]
    DIRECTION OUTPUT ;
    USE SIGNAL ;
    PORT
      LAYER M4 ;
        RECT  21.516 20.208 21.6 20.232 ;
    END
  END o[3]
  PIN o[400]
    DIRECTION OUTPUT ;
    USE SIGNAL ;
    PORT
      LAYER M4 ;
        RECT  21.516 43.728 21.6 43.752 ;
    END
  END o[400]
  PIN o[401]
    DIRECTION OUTPUT ;
    USE SIGNAL ;
    PORT
      LAYER M4 ;
        RECT  21.516 43.824 21.6 43.848 ;
    END
  END o[401]
  PIN o[402]
    DIRECTION OUTPUT ;
    USE SIGNAL ;
    PORT
      LAYER M4 ;
        RECT  21.516 43.92 21.6 43.944 ;
    END
  END o[402]
  PIN o[403]
    DIRECTION OUTPUT ;
    USE SIGNAL ;
    PORT
      LAYER M4 ;
        RECT  21.516 44.016 21.6 44.04 ;
    END
  END o[403]
  PIN o[404]
    DIRECTION OUTPUT ;
    USE SIGNAL ;
    PORT
      LAYER M4 ;
        RECT  21.516 44.112 21.6 44.136 ;
    END
  END o[404]
  PIN o[405]
    DIRECTION OUTPUT ;
    USE SIGNAL ;
    PORT
      LAYER M4 ;
        RECT  21.516 44.208 21.6 44.232 ;
    END
  END o[405]
  PIN o[406]
    DIRECTION OUTPUT ;
    USE SIGNAL ;
    PORT
      LAYER M4 ;
        RECT  21.516 44.304 21.6 44.328 ;
    END
  END o[406]
  PIN o[407]
    DIRECTION OUTPUT ;
    USE SIGNAL ;
    PORT
      LAYER M4 ;
        RECT  21.516 44.4 21.6 44.424 ;
    END
  END o[407]
  PIN o[408]
    DIRECTION OUTPUT ;
    USE SIGNAL ;
    PORT
      LAYER M4 ;
        RECT  21.516 44.496 21.6 44.52 ;
    END
  END o[408]
  PIN o[409]
    DIRECTION OUTPUT ;
    USE SIGNAL ;
    PORT
      LAYER M4 ;
        RECT  21.516 44.592 21.6 44.616 ;
    END
  END o[409]
  PIN o[40]
    DIRECTION OUTPUT ;
    USE SIGNAL ;
    PORT
      LAYER M4 ;
        RECT  21.516 23.76 21.6 23.784 ;
    END
  END o[40]
  PIN o[410]
    DIRECTION OUTPUT ;
    USE SIGNAL ;
    PORT
      LAYER M4 ;
        RECT  21.516 44.688 21.6 44.712 ;
    END
  END o[410]
  PIN o[411]
    DIRECTION OUTPUT ;
    USE SIGNAL ;
    PORT
      LAYER M4 ;
        RECT  21.516 44.784 21.6 44.808 ;
    END
  END o[411]
  PIN o[412]
    DIRECTION OUTPUT ;
    USE SIGNAL ;
    PORT
      LAYER M4 ;
        RECT  21.516 44.88 21.6 44.904 ;
    END
  END o[412]
  PIN o[413]
    DIRECTION OUTPUT ;
    USE SIGNAL ;
    PORT
      LAYER M4 ;
        RECT  21.516 44.976 21.6 45 ;
    END
  END o[413]
  PIN o[414]
    DIRECTION OUTPUT ;
    USE SIGNAL ;
    PORT
      LAYER M4 ;
        RECT  21.516 45.072 21.6 45.096 ;
    END
  END o[414]
  PIN o[415]
    DIRECTION OUTPUT ;
    USE SIGNAL ;
    PORT
      LAYER M4 ;
        RECT  21.516 45.168 21.6 45.192 ;
    END
  END o[415]
  PIN o[416]
    DIRECTION OUTPUT ;
    USE SIGNAL ;
    PORT
      LAYER M4 ;
        RECT  21.516 51.408 21.6 51.432 ;
    END
  END o[416]
  PIN o[417]
    DIRECTION OUTPUT ;
    USE SIGNAL ;
    PORT
      LAYER M4 ;
        RECT  21.516 51.504 21.6 51.528 ;
    END
  END o[417]
  PIN o[418]
    DIRECTION OUTPUT ;
    USE SIGNAL ;
    PORT
      LAYER M4 ;
        RECT  21.516 51.6 21.6 51.624 ;
    END
  END o[418]
  PIN o[419]
    DIRECTION OUTPUT ;
    USE SIGNAL ;
    PORT
      LAYER M4 ;
        RECT  21.516 51.696 21.6 51.72 ;
    END
  END o[419]
  PIN o[41]
    DIRECTION OUTPUT ;
    USE SIGNAL ;
    PORT
      LAYER M4 ;
        RECT  21.516 23.856 21.6 23.88 ;
    END
  END o[41]
  PIN o[420]
    DIRECTION OUTPUT ;
    USE SIGNAL ;
    PORT
      LAYER M4 ;
        RECT  21.516 51.792 21.6 51.816 ;
    END
  END o[420]
  PIN o[421]
    DIRECTION OUTPUT ;
    USE SIGNAL ;
    PORT
      LAYER M4 ;
        RECT  21.516 51.888 21.6 51.912 ;
    END
  END o[421]
  PIN o[422]
    DIRECTION OUTPUT ;
    USE SIGNAL ;
    PORT
      LAYER M4 ;
        RECT  21.516 51.984 21.6 52.008 ;
    END
  END o[422]
  PIN o[423]
    DIRECTION OUTPUT ;
    USE SIGNAL ;
    PORT
      LAYER M4 ;
        RECT  21.516 52.08 21.6 52.104 ;
    END
  END o[423]
  PIN o[424]
    DIRECTION OUTPUT ;
    USE SIGNAL ;
    PORT
      LAYER M4 ;
        RECT  21.516 52.176 21.6 52.2 ;
    END
  END o[424]
  PIN o[425]
    DIRECTION OUTPUT ;
    USE SIGNAL ;
    PORT
      LAYER M4 ;
        RECT  21.516 52.272 21.6 52.296 ;
    END
  END o[425]
  PIN o[426]
    DIRECTION OUTPUT ;
    USE SIGNAL ;
    PORT
      LAYER M4 ;
        RECT  21.516 52.368 21.6 52.392 ;
    END
  END o[426]
  PIN o[427]
    DIRECTION OUTPUT ;
    USE SIGNAL ;
    PORT
      LAYER M4 ;
        RECT  21.516 52.464 21.6 52.488 ;
    END
  END o[427]
  PIN o[428]
    DIRECTION OUTPUT ;
    USE SIGNAL ;
    PORT
      LAYER M4 ;
        RECT  21.516 52.56 21.6 52.584 ;
    END
  END o[428]
  PIN o[429]
    DIRECTION OUTPUT ;
    USE SIGNAL ;
    PORT
      LAYER M4 ;
        RECT  21.516 52.656 21.6 52.68 ;
    END
  END o[429]
  PIN o[42]
    DIRECTION OUTPUT ;
    USE SIGNAL ;
    PORT
      LAYER M4 ;
        RECT  21.516 23.952 21.6 23.976 ;
    END
  END o[42]
  PIN o[430]
    DIRECTION OUTPUT ;
    USE SIGNAL ;
    PORT
      LAYER M4 ;
        RECT  21.516 52.752 21.6 52.776 ;
    END
  END o[430]
  PIN o[431]
    DIRECTION OUTPUT ;
    USE SIGNAL ;
    PORT
      LAYER M4 ;
        RECT  21.516 52.848 21.6 52.872 ;
    END
  END o[431]
  PIN o[432]
    DIRECTION OUTPUT ;
    USE SIGNAL ;
    PORT
      LAYER M4 ;
        RECT  21.516 52.944 21.6 52.968 ;
    END
  END o[432]
  PIN o[433]
    DIRECTION OUTPUT ;
    USE SIGNAL ;
    PORT
      LAYER M4 ;
        RECT  21.516 53.04 21.6 53.064 ;
    END
  END o[433]
  PIN o[434]
    DIRECTION OUTPUT ;
    USE SIGNAL ;
    PORT
      LAYER M4 ;
        RECT  21.516 53.136 21.6 53.16 ;
    END
  END o[434]
  PIN o[435]
    DIRECTION OUTPUT ;
    USE SIGNAL ;
    PORT
      LAYER M4 ;
        RECT  21.516 53.232 21.6 53.256 ;
    END
  END o[435]
  PIN o[436]
    DIRECTION OUTPUT ;
    USE SIGNAL ;
    PORT
      LAYER M4 ;
        RECT  21.516 53.328 21.6 53.352 ;
    END
  END o[436]
  PIN o[437]
    DIRECTION OUTPUT ;
    USE SIGNAL ;
    PORT
      LAYER M4 ;
        RECT  21.516 53.424 21.6 53.448 ;
    END
  END o[437]
  PIN o[438]
    DIRECTION OUTPUT ;
    USE SIGNAL ;
    PORT
      LAYER M4 ;
        RECT  21.516 53.52 21.6 53.544 ;
    END
  END o[438]
  PIN o[439]
    DIRECTION OUTPUT ;
    USE SIGNAL ;
    PORT
      LAYER M4 ;
        RECT  21.516 53.616 21.6 53.64 ;
    END
  END o[439]
  PIN o[43]
    DIRECTION OUTPUT ;
    USE SIGNAL ;
    PORT
      LAYER M4 ;
        RECT  21.516 24.048 21.6 24.072 ;
    END
  END o[43]
  PIN o[440]
    DIRECTION OUTPUT ;
    USE SIGNAL ;
    PORT
      LAYER M4 ;
        RECT  21.516 53.712 21.6 53.736 ;
    END
  END o[440]
  PIN o[441]
    DIRECTION OUTPUT ;
    USE SIGNAL ;
    PORT
      LAYER M4 ;
        RECT  21.516 53.808 21.6 53.832 ;
    END
  END o[441]
  PIN o[442]
    DIRECTION OUTPUT ;
    USE SIGNAL ;
    PORT
      LAYER M4 ;
        RECT  21.516 53.904 21.6 53.928 ;
    END
  END o[442]
  PIN o[443]
    DIRECTION OUTPUT ;
    USE SIGNAL ;
    PORT
      LAYER M4 ;
        RECT  21.516 54 21.6 54.024 ;
    END
  END o[443]
  PIN o[444]
    DIRECTION OUTPUT ;
    USE SIGNAL ;
    PORT
      LAYER M4 ;
        RECT  21.516 54.096 21.6 54.12 ;
    END
  END o[444]
  PIN o[445]
    DIRECTION OUTPUT ;
    USE SIGNAL ;
    PORT
      LAYER M4 ;
        RECT  21.516 54.192 21.6 54.216 ;
    END
  END o[445]
  PIN o[446]
    DIRECTION OUTPUT ;
    USE SIGNAL ;
    PORT
      LAYER M4 ;
        RECT  21.516 54.288 21.6 54.312 ;
    END
  END o[446]
  PIN o[447]
    DIRECTION OUTPUT ;
    USE SIGNAL ;
    PORT
      LAYER M4 ;
        RECT  21.516 54.384 21.6 54.408 ;
    END
  END o[447]
  PIN o[448]
    DIRECTION OUTPUT ;
    USE SIGNAL ;
    PORT
      LAYER M4 ;
        RECT  21.516 58.32 21.6 58.344 ;
    END
  END o[448]
  PIN o[449]
    DIRECTION OUTPUT ;
    USE SIGNAL ;
    PORT
      LAYER M4 ;
        RECT  21.516 58.416 21.6 58.44 ;
    END
  END o[449]
  PIN o[44]
    DIRECTION OUTPUT ;
    USE SIGNAL ;
    PORT
      LAYER M4 ;
        RECT  21.516 24.144 21.6 24.168 ;
    END
  END o[44]
  PIN o[450]
    DIRECTION OUTPUT ;
    USE SIGNAL ;
    PORT
      LAYER M4 ;
        RECT  21.516 58.512 21.6 58.536 ;
    END
  END o[450]
  PIN o[451]
    DIRECTION OUTPUT ;
    USE SIGNAL ;
    PORT
      LAYER M4 ;
        RECT  21.516 58.608 21.6 58.632 ;
    END
  END o[451]
  PIN o[452]
    DIRECTION OUTPUT ;
    USE SIGNAL ;
    PORT
      LAYER M4 ;
        RECT  21.516 58.704 21.6 58.728 ;
    END
  END o[452]
  PIN o[453]
    DIRECTION OUTPUT ;
    USE SIGNAL ;
    PORT
      LAYER M4 ;
        RECT  21.516 58.8 21.6 58.824 ;
    END
  END o[453]
  PIN o[454]
    DIRECTION OUTPUT ;
    USE SIGNAL ;
    PORT
      LAYER M4 ;
        RECT  21.516 58.896 21.6 58.92 ;
    END
  END o[454]
  PIN o[455]
    DIRECTION OUTPUT ;
    USE SIGNAL ;
    PORT
      LAYER M4 ;
        RECT  21.516 58.992 21.6 59.016 ;
    END
  END o[455]
  PIN o[456]
    DIRECTION OUTPUT ;
    USE SIGNAL ;
    PORT
      LAYER M4 ;
        RECT  21.516 59.088 21.6 59.112 ;
    END
  END o[456]
  PIN o[457]
    DIRECTION OUTPUT ;
    USE SIGNAL ;
    PORT
      LAYER M4 ;
        RECT  21.516 59.184 21.6 59.208 ;
    END
  END o[457]
  PIN o[458]
    DIRECTION OUTPUT ;
    USE SIGNAL ;
    PORT
      LAYER M4 ;
        RECT  21.516 59.28 21.6 59.304 ;
    END
  END o[458]
  PIN o[459]
    DIRECTION OUTPUT ;
    USE SIGNAL ;
    PORT
      LAYER M4 ;
        RECT  21.516 59.376 21.6 59.4 ;
    END
  END o[459]
  PIN o[45]
    DIRECTION OUTPUT ;
    USE SIGNAL ;
    PORT
      LAYER M4 ;
        RECT  21.516 24.24 21.6 24.264 ;
    END
  END o[45]
  PIN o[460]
    DIRECTION OUTPUT ;
    USE SIGNAL ;
    PORT
      LAYER M4 ;
        RECT  21.516 59.472 21.6 59.496 ;
    END
  END o[460]
  PIN o[461]
    DIRECTION OUTPUT ;
    USE SIGNAL ;
    PORT
      LAYER M4 ;
        RECT  21.516 59.568 21.6 59.592 ;
    END
  END o[461]
  PIN o[462]
    DIRECTION OUTPUT ;
    USE SIGNAL ;
    PORT
      LAYER M4 ;
        RECT  21.516 59.664 21.6 59.688 ;
    END
  END o[462]
  PIN o[463]
    DIRECTION OUTPUT ;
    USE SIGNAL ;
    PORT
      LAYER M4 ;
        RECT  21.516 59.76 21.6 59.784 ;
    END
  END o[463]
  PIN o[464]
    DIRECTION OUTPUT ;
    USE SIGNAL ;
    PORT
      LAYER M4 ;
        RECT  21.516 59.856 21.6 59.88 ;
    END
  END o[464]
  PIN o[465]
    DIRECTION OUTPUT ;
    USE SIGNAL ;
    PORT
      LAYER M4 ;
        RECT  21.516 59.952 21.6 59.976 ;
    END
  END o[465]
  PIN o[466]
    DIRECTION OUTPUT ;
    USE SIGNAL ;
    PORT
      LAYER M4 ;
        RECT  21.516 60.048 21.6 60.072 ;
    END
  END o[466]
  PIN o[467]
    DIRECTION OUTPUT ;
    USE SIGNAL ;
    PORT
      LAYER M4 ;
        RECT  21.516 60.144 21.6 60.168 ;
    END
  END o[467]
  PIN o[468]
    DIRECTION OUTPUT ;
    USE SIGNAL ;
    PORT
      LAYER M4 ;
        RECT  21.516 60.24 21.6 60.264 ;
    END
  END o[468]
  PIN o[469]
    DIRECTION OUTPUT ;
    USE SIGNAL ;
    PORT
      LAYER M4 ;
        RECT  21.516 60.336 21.6 60.36 ;
    END
  END o[469]
  PIN o[46]
    DIRECTION OUTPUT ;
    USE SIGNAL ;
    PORT
      LAYER M4 ;
        RECT  21.516 24.336 21.6 24.36 ;
    END
  END o[46]
  PIN o[470]
    DIRECTION OUTPUT ;
    USE SIGNAL ;
    PORT
      LAYER M4 ;
        RECT  21.516 60.432 21.6 60.456 ;
    END
  END o[470]
  PIN o[471]
    DIRECTION OUTPUT ;
    USE SIGNAL ;
    PORT
      LAYER M4 ;
        RECT  21.516 60.528 21.6 60.552 ;
    END
  END o[471]
  PIN o[472]
    DIRECTION OUTPUT ;
    USE SIGNAL ;
    PORT
      LAYER M4 ;
        RECT  21.516 60.624 21.6 60.648 ;
    END
  END o[472]
  PIN o[473]
    DIRECTION OUTPUT ;
    USE SIGNAL ;
    PORT
      LAYER M4 ;
        RECT  21.516 60.72 21.6 60.744 ;
    END
  END o[473]
  PIN o[474]
    DIRECTION OUTPUT ;
    USE SIGNAL ;
    PORT
      LAYER M4 ;
        RECT  21.516 60.816 21.6 60.84 ;
    END
  END o[474]
  PIN o[475]
    DIRECTION OUTPUT ;
    USE SIGNAL ;
    PORT
      LAYER M4 ;
        RECT  21.516 60.912 21.6 60.936 ;
    END
  END o[475]
  PIN o[476]
    DIRECTION OUTPUT ;
    USE SIGNAL ;
    PORT
      LAYER M4 ;
        RECT  21.516 61.008 21.6 61.032 ;
    END
  END o[476]
  PIN o[477]
    DIRECTION OUTPUT ;
    USE SIGNAL ;
    PORT
      LAYER M4 ;
        RECT  21.516 61.104 21.6 61.128 ;
    END
  END o[477]
  PIN o[478]
    DIRECTION OUTPUT ;
    USE SIGNAL ;
    PORT
      LAYER M4 ;
        RECT  21.516 61.2 21.6 61.224 ;
    END
  END o[478]
  PIN o[479]
    DIRECTION OUTPUT ;
    USE SIGNAL ;
    PORT
      LAYER M4 ;
        RECT  21.516 61.296 21.6 61.32 ;
    END
  END o[479]
  PIN o[47]
    DIRECTION OUTPUT ;
    USE SIGNAL ;
    PORT
      LAYER M4 ;
        RECT  21.516 24.432 21.6 24.456 ;
    END
  END o[47]
  PIN o[480]
    DIRECTION OUTPUT ;
    USE SIGNAL ;
    PORT
      LAYER M4 ;
        RECT  21.516 16.08 21.6 16.104 ;
    END
  END o[480]
  PIN o[481]
    DIRECTION OUTPUT ;
    USE SIGNAL ;
    PORT
      LAYER M4 ;
        RECT  21.516 16.176 21.6 16.2 ;
    END
  END o[481]
  PIN o[482]
    DIRECTION OUTPUT ;
    USE SIGNAL ;
    PORT
      LAYER M4 ;
        RECT  21.516 16.272 21.6 16.296 ;
    END
  END o[482]
  PIN o[483]
    DIRECTION OUTPUT ;
    USE SIGNAL ;
    PORT
      LAYER M4 ;
        RECT  21.516 16.368 21.6 16.392 ;
    END
  END o[483]
  PIN o[484]
    DIRECTION OUTPUT ;
    USE SIGNAL ;
    PORT
      LAYER M4 ;
        RECT  21.516 16.464 21.6 16.488 ;
    END
  END o[484]
  PIN o[485]
    DIRECTION OUTPUT ;
    USE SIGNAL ;
    PORT
      LAYER M4 ;
        RECT  21.516 16.56 21.6 16.584 ;
    END
  END o[485]
  PIN o[486]
    DIRECTION OUTPUT ;
    USE SIGNAL ;
    PORT
      LAYER M4 ;
        RECT  21.516 16.656 21.6 16.68 ;
    END
  END o[486]
  PIN o[487]
    DIRECTION OUTPUT ;
    USE SIGNAL ;
    PORT
      LAYER M4 ;
        RECT  21.516 16.752 21.6 16.776 ;
    END
  END o[487]
  PIN o[488]
    DIRECTION OUTPUT ;
    USE SIGNAL ;
    PORT
      LAYER M4 ;
        RECT  21.516 16.848 21.6 16.872 ;
    END
  END o[488]
  PIN o[489]
    DIRECTION OUTPUT ;
    USE SIGNAL ;
    PORT
      LAYER M4 ;
        RECT  21.516 16.944 21.6 16.968 ;
    END
  END o[489]
  PIN o[48]
    DIRECTION OUTPUT ;
    USE SIGNAL ;
    PORT
      LAYER M4 ;
        RECT  21.516 24.528 21.6 24.552 ;
    END
  END o[48]
  PIN o[490]
    DIRECTION OUTPUT ;
    USE SIGNAL ;
    PORT
      LAYER M4 ;
        RECT  21.516 17.04 21.6 17.064 ;
    END
  END o[490]
  PIN o[491]
    DIRECTION OUTPUT ;
    USE SIGNAL ;
    PORT
      LAYER M4 ;
        RECT  21.516 17.136 21.6 17.16 ;
    END
  END o[491]
  PIN o[492]
    DIRECTION OUTPUT ;
    USE SIGNAL ;
    PORT
      LAYER M4 ;
        RECT  21.516 17.232 21.6 17.256 ;
    END
  END o[492]
  PIN o[493]
    DIRECTION OUTPUT ;
    USE SIGNAL ;
    PORT
      LAYER M4 ;
        RECT  21.516 17.328 21.6 17.352 ;
    END
  END o[493]
  PIN o[494]
    DIRECTION OUTPUT ;
    USE SIGNAL ;
    PORT
      LAYER M4 ;
        RECT  21.516 17.424 21.6 17.448 ;
    END
  END o[494]
  PIN o[495]
    DIRECTION OUTPUT ;
    USE SIGNAL ;
    PORT
      LAYER M4 ;
        RECT  21.516 17.52 21.6 17.544 ;
    END
  END o[495]
  PIN o[496]
    DIRECTION OUTPUT ;
    USE SIGNAL ;
    PORT
      LAYER M4 ;
        RECT  21.516 17.616 21.6 17.64 ;
    END
  END o[496]
  PIN o[497]
    DIRECTION OUTPUT ;
    USE SIGNAL ;
    PORT
      LAYER M4 ;
        RECT  21.516 17.712 21.6 17.736 ;
    END
  END o[497]
  PIN o[498]
    DIRECTION OUTPUT ;
    USE SIGNAL ;
    PORT
      LAYER M4 ;
        RECT  21.516 17.808 21.6 17.832 ;
    END
  END o[498]
  PIN o[499]
    DIRECTION OUTPUT ;
    USE SIGNAL ;
    PORT
      LAYER M4 ;
        RECT  21.516 17.904 21.6 17.928 ;
    END
  END o[499]
  PIN o[49]
    DIRECTION OUTPUT ;
    USE SIGNAL ;
    PORT
      LAYER M4 ;
        RECT  21.516 24.624 21.6 24.648 ;
    END
  END o[49]
  PIN o[4]
    DIRECTION OUTPUT ;
    USE SIGNAL ;
    PORT
      LAYER M4 ;
        RECT  21.516 20.304 21.6 20.328 ;
    END
  END o[4]
  PIN o[500]
    DIRECTION OUTPUT ;
    USE SIGNAL ;
    PORT
      LAYER M4 ;
        RECT  21.516 18 21.6 18.024 ;
    END
  END o[500]
  PIN o[501]
    DIRECTION OUTPUT ;
    USE SIGNAL ;
    PORT
      LAYER M4 ;
        RECT  21.516 18.096 21.6 18.12 ;
    END
  END o[501]
  PIN o[502]
    DIRECTION OUTPUT ;
    USE SIGNAL ;
    PORT
      LAYER M4 ;
        RECT  21.516 18.192 21.6 18.216 ;
    END
  END o[502]
  PIN o[503]
    DIRECTION OUTPUT ;
    USE SIGNAL ;
    PORT
      LAYER M4 ;
        RECT  21.516 18.288 21.6 18.312 ;
    END
  END o[503]
  PIN o[504]
    DIRECTION OUTPUT ;
    USE SIGNAL ;
    PORT
      LAYER M4 ;
        RECT  21.516 18.384 21.6 18.408 ;
    END
  END o[504]
  PIN o[505]
    DIRECTION OUTPUT ;
    USE SIGNAL ;
    PORT
      LAYER M4 ;
        RECT  21.516 18.48 21.6 18.504 ;
    END
  END o[505]
  PIN o[506]
    DIRECTION OUTPUT ;
    USE SIGNAL ;
    PORT
      LAYER M4 ;
        RECT  21.516 18.576 21.6 18.6 ;
    END
  END o[506]
  PIN o[507]
    DIRECTION OUTPUT ;
    USE SIGNAL ;
    PORT
      LAYER M4 ;
        RECT  21.516 18.672 21.6 18.696 ;
    END
  END o[507]
  PIN o[508]
    DIRECTION OUTPUT ;
    USE SIGNAL ;
    PORT
      LAYER M4 ;
        RECT  21.516 18.768 21.6 18.792 ;
    END
  END o[508]
  PIN o[509]
    DIRECTION OUTPUT ;
    USE SIGNAL ;
    PORT
      LAYER M4 ;
        RECT  21.516 18.864 21.6 18.888 ;
    END
  END o[509]
  PIN o[50]
    DIRECTION OUTPUT ;
    USE SIGNAL ;
    PORT
      LAYER M4 ;
        RECT  21.516 24.72 21.6 24.744 ;
    END
  END o[50]
  PIN o[510]
    DIRECTION OUTPUT ;
    USE SIGNAL ;
    PORT
      LAYER M4 ;
        RECT  21.516 18.96 21.6 18.984 ;
    END
  END o[510]
  PIN o[511]
    DIRECTION OUTPUT ;
    USE SIGNAL ;
    PORT
      LAYER M4 ;
        RECT  21.516 19.056 21.6 19.08 ;
    END
  END o[511]
  PIN o[512]
    DIRECTION OUTPUT ;
    USE SIGNAL ;
    PORT
      LAYER M4 ;
        RECT  21.516 9.936 21.6 9.96 ;
    END
  END o[512]
  PIN o[513]
    DIRECTION OUTPUT ;
    USE SIGNAL ;
    PORT
      LAYER M4 ;
        RECT  21.516 10.032 21.6 10.056 ;
    END
  END o[513]
  PIN o[514]
    DIRECTION OUTPUT ;
    USE SIGNAL ;
    PORT
      LAYER M4 ;
        RECT  21.516 10.128 21.6 10.152 ;
    END
  END o[514]
  PIN o[515]
    DIRECTION OUTPUT ;
    USE SIGNAL ;
    PORT
      LAYER M4 ;
        RECT  21.516 10.224 21.6 10.248 ;
    END
  END o[515]
  PIN o[516]
    DIRECTION OUTPUT ;
    USE SIGNAL ;
    PORT
      LAYER M4 ;
        RECT  21.516 10.32 21.6 10.344 ;
    END
  END o[516]
  PIN o[517]
    DIRECTION OUTPUT ;
    USE SIGNAL ;
    PORT
      LAYER M4 ;
        RECT  21.516 10.416 21.6 10.44 ;
    END
  END o[517]
  PIN o[518]
    DIRECTION OUTPUT ;
    USE SIGNAL ;
    PORT
      LAYER M4 ;
        RECT  21.516 10.512 21.6 10.536 ;
    END
  END o[518]
  PIN o[519]
    DIRECTION OUTPUT ;
    USE SIGNAL ;
    PORT
      LAYER M4 ;
        RECT  21.516 10.608 21.6 10.632 ;
    END
  END o[519]
  PIN o[51]
    DIRECTION OUTPUT ;
    USE SIGNAL ;
    PORT
      LAYER M4 ;
        RECT  21.516 24.816 21.6 24.84 ;
    END
  END o[51]
  PIN o[520]
    DIRECTION OUTPUT ;
    USE SIGNAL ;
    PORT
      LAYER M4 ;
        RECT  21.516 10.704 21.6 10.728 ;
    END
  END o[520]
  PIN o[521]
    DIRECTION OUTPUT ;
    USE SIGNAL ;
    PORT
      LAYER M4 ;
        RECT  21.516 10.8 21.6 10.824 ;
    END
  END o[521]
  PIN o[522]
    DIRECTION OUTPUT ;
    USE SIGNAL ;
    PORT
      LAYER M4 ;
        RECT  21.516 10.896 21.6 10.92 ;
    END
  END o[522]
  PIN o[523]
    DIRECTION OUTPUT ;
    USE SIGNAL ;
    PORT
      LAYER M4 ;
        RECT  21.516 10.992 21.6 11.016 ;
    END
  END o[523]
  PIN o[524]
    DIRECTION OUTPUT ;
    USE SIGNAL ;
    PORT
      LAYER M4 ;
        RECT  21.516 11.088 21.6 11.112 ;
    END
  END o[524]
  PIN o[525]
    DIRECTION OUTPUT ;
    USE SIGNAL ;
    PORT
      LAYER M4 ;
        RECT  21.516 11.184 21.6 11.208 ;
    END
  END o[525]
  PIN o[526]
    DIRECTION OUTPUT ;
    USE SIGNAL ;
    PORT
      LAYER M4 ;
        RECT  21.516 11.28 21.6 11.304 ;
    END
  END o[526]
  PIN o[527]
    DIRECTION OUTPUT ;
    USE SIGNAL ;
    PORT
      LAYER M4 ;
        RECT  21.516 11.376 21.6 11.4 ;
    END
  END o[527]
  PIN o[528]
    DIRECTION OUTPUT ;
    USE SIGNAL ;
    PORT
      LAYER M4 ;
        RECT  21.516 11.472 21.6 11.496 ;
    END
  END o[528]
  PIN o[529]
    DIRECTION OUTPUT ;
    USE SIGNAL ;
    PORT
      LAYER M4 ;
        RECT  21.516 11.568 21.6 11.592 ;
    END
  END o[529]
  PIN o[52]
    DIRECTION OUTPUT ;
    USE SIGNAL ;
    PORT
      LAYER M4 ;
        RECT  21.516 24.912 21.6 24.936 ;
    END
  END o[52]
  PIN o[530]
    DIRECTION OUTPUT ;
    USE SIGNAL ;
    PORT
      LAYER M4 ;
        RECT  21.516 11.664 21.6 11.688 ;
    END
  END o[530]
  PIN o[531]
    DIRECTION OUTPUT ;
    USE SIGNAL ;
    PORT
      LAYER M4 ;
        RECT  21.516 11.76 21.6 11.784 ;
    END
  END o[531]
  PIN o[532]
    DIRECTION OUTPUT ;
    USE SIGNAL ;
    PORT
      LAYER M4 ;
        RECT  21.516 11.856 21.6 11.88 ;
    END
  END o[532]
  PIN o[533]
    DIRECTION OUTPUT ;
    USE SIGNAL ;
    PORT
      LAYER M4 ;
        RECT  21.516 11.952 21.6 11.976 ;
    END
  END o[533]
  PIN o[534]
    DIRECTION OUTPUT ;
    USE SIGNAL ;
    PORT
      LAYER M4 ;
        RECT  21.516 12.048 21.6 12.072 ;
    END
  END o[534]
  PIN o[535]
    DIRECTION OUTPUT ;
    USE SIGNAL ;
    PORT
      LAYER M4 ;
        RECT  21.516 12.144 21.6 12.168 ;
    END
  END o[535]
  PIN o[536]
    DIRECTION OUTPUT ;
    USE SIGNAL ;
    PORT
      LAYER M4 ;
        RECT  21.516 12.24 21.6 12.264 ;
    END
  END o[536]
  PIN o[537]
    DIRECTION OUTPUT ;
    USE SIGNAL ;
    PORT
      LAYER M4 ;
        RECT  21.516 12.336 21.6 12.36 ;
    END
  END o[537]
  PIN o[538]
    DIRECTION OUTPUT ;
    USE SIGNAL ;
    PORT
      LAYER M4 ;
        RECT  21.516 12.432 21.6 12.456 ;
    END
  END o[538]
  PIN o[539]
    DIRECTION OUTPUT ;
    USE SIGNAL ;
    PORT
      LAYER M4 ;
        RECT  21.516 12.528 21.6 12.552 ;
    END
  END o[539]
  PIN o[53]
    DIRECTION OUTPUT ;
    USE SIGNAL ;
    PORT
      LAYER M4 ;
        RECT  21.516 25.008 21.6 25.032 ;
    END
  END o[53]
  PIN o[540]
    DIRECTION OUTPUT ;
    USE SIGNAL ;
    PORT
      LAYER M4 ;
        RECT  21.516 12.624 21.6 12.648 ;
    END
  END o[540]
  PIN o[541]
    DIRECTION OUTPUT ;
    USE SIGNAL ;
    PORT
      LAYER M4 ;
        RECT  21.516 12.72 21.6 12.744 ;
    END
  END o[541]
  PIN o[542]
    DIRECTION OUTPUT ;
    USE SIGNAL ;
    PORT
      LAYER M4 ;
        RECT  21.516 12.816 21.6 12.84 ;
    END
  END o[542]
  PIN o[543]
    DIRECTION OUTPUT ;
    USE SIGNAL ;
    PORT
      LAYER M4 ;
        RECT  21.516 12.912 21.6 12.936 ;
    END
  END o[543]
  PIN o[544]
    DIRECTION OUTPUT ;
    USE SIGNAL ;
    PORT
      LAYER M4 ;
        RECT  21.516 13.008 21.6 13.032 ;
    END
  END o[544]
  PIN o[545]
    DIRECTION OUTPUT ;
    USE SIGNAL ;
    PORT
      LAYER M4 ;
        RECT  21.516 13.104 21.6 13.128 ;
    END
  END o[545]
  PIN o[546]
    DIRECTION OUTPUT ;
    USE SIGNAL ;
    PORT
      LAYER M4 ;
        RECT  21.516 13.2 21.6 13.224 ;
    END
  END o[546]
  PIN o[547]
    DIRECTION OUTPUT ;
    USE SIGNAL ;
    PORT
      LAYER M4 ;
        RECT  21.516 13.296 21.6 13.32 ;
    END
  END o[547]
  PIN o[548]
    DIRECTION OUTPUT ;
    USE SIGNAL ;
    PORT
      LAYER M4 ;
        RECT  21.516 13.392 21.6 13.416 ;
    END
  END o[548]
  PIN o[549]
    DIRECTION OUTPUT ;
    USE SIGNAL ;
    PORT
      LAYER M4 ;
        RECT  21.516 13.488 21.6 13.512 ;
    END
  END o[549]
  PIN o[54]
    DIRECTION OUTPUT ;
    USE SIGNAL ;
    PORT
      LAYER M4 ;
        RECT  21.516 25.104 21.6 25.128 ;
    END
  END o[54]
  PIN o[550]
    DIRECTION OUTPUT ;
    USE SIGNAL ;
    PORT
      LAYER M4 ;
        RECT  21.516 13.584 21.6 13.608 ;
    END
  END o[550]
  PIN o[551]
    DIRECTION OUTPUT ;
    USE SIGNAL ;
    PORT
      LAYER M4 ;
        RECT  21.516 13.68 21.6 13.704 ;
    END
  END o[551]
  PIN o[552]
    DIRECTION OUTPUT ;
    USE SIGNAL ;
    PORT
      LAYER M4 ;
        RECT  21.516 13.776 21.6 13.8 ;
    END
  END o[552]
  PIN o[553]
    DIRECTION OUTPUT ;
    USE SIGNAL ;
    PORT
      LAYER M4 ;
        RECT  21.516 13.872 21.6 13.896 ;
    END
  END o[553]
  PIN o[554]
    DIRECTION OUTPUT ;
    USE SIGNAL ;
    PORT
      LAYER M4 ;
        RECT  21.516 13.968 21.6 13.992 ;
    END
  END o[554]
  PIN o[555]
    DIRECTION OUTPUT ;
    USE SIGNAL ;
    PORT
      LAYER M4 ;
        RECT  21.516 14.064 21.6 14.088 ;
    END
  END o[555]
  PIN o[556]
    DIRECTION OUTPUT ;
    USE SIGNAL ;
    PORT
      LAYER M4 ;
        RECT  21.516 14.16 21.6 14.184 ;
    END
  END o[556]
  PIN o[557]
    DIRECTION OUTPUT ;
    USE SIGNAL ;
    PORT
      LAYER M4 ;
        RECT  21.516 14.256 21.6 14.28 ;
    END
  END o[557]
  PIN o[558]
    DIRECTION OUTPUT ;
    USE SIGNAL ;
    PORT
      LAYER M4 ;
        RECT  21.516 14.352 21.6 14.376 ;
    END
  END o[558]
  PIN o[559]
    DIRECTION OUTPUT ;
    USE SIGNAL ;
    PORT
      LAYER M4 ;
        RECT  21.516 14.448 21.6 14.472 ;
    END
  END o[559]
  PIN o[55]
    DIRECTION OUTPUT ;
    USE SIGNAL ;
    PORT
      LAYER M4 ;
        RECT  21.516 25.2 21.6 25.224 ;
    END
  END o[55]
  PIN o[560]
    DIRECTION OUTPUT ;
    USE SIGNAL ;
    PORT
      LAYER M4 ;
        RECT  21.516 14.544 21.6 14.568 ;
    END
  END o[560]
  PIN o[561]
    DIRECTION OUTPUT ;
    USE SIGNAL ;
    PORT
      LAYER M4 ;
        RECT  21.516 14.64 21.6 14.664 ;
    END
  END o[561]
  PIN o[562]
    DIRECTION OUTPUT ;
    USE SIGNAL ;
    PORT
      LAYER M4 ;
        RECT  21.516 14.736 21.6 14.76 ;
    END
  END o[562]
  PIN o[563]
    DIRECTION OUTPUT ;
    USE SIGNAL ;
    PORT
      LAYER M4 ;
        RECT  21.516 14.832 21.6 14.856 ;
    END
  END o[563]
  PIN o[564]
    DIRECTION OUTPUT ;
    USE SIGNAL ;
    PORT
      LAYER M4 ;
        RECT  21.516 14.928 21.6 14.952 ;
    END
  END o[564]
  PIN o[565]
    DIRECTION OUTPUT ;
    USE SIGNAL ;
    PORT
      LAYER M4 ;
        RECT  21.516 15.024 21.6 15.048 ;
    END
  END o[565]
  PIN o[566]
    DIRECTION OUTPUT ;
    USE SIGNAL ;
    PORT
      LAYER M4 ;
        RECT  21.516 15.12 21.6 15.144 ;
    END
  END o[566]
  PIN o[567]
    DIRECTION OUTPUT ;
    USE SIGNAL ;
    PORT
      LAYER M4 ;
        RECT  21.516 15.216 21.6 15.24 ;
    END
  END o[567]
  PIN o[568]
    DIRECTION OUTPUT ;
    USE SIGNAL ;
    PORT
      LAYER M4 ;
        RECT  21.516 15.312 21.6 15.336 ;
    END
  END o[568]
  PIN o[569]
    DIRECTION OUTPUT ;
    USE SIGNAL ;
    PORT
      LAYER M4 ;
        RECT  21.516 15.408 21.6 15.432 ;
    END
  END o[569]
  PIN o[56]
    DIRECTION OUTPUT ;
    USE SIGNAL ;
    PORT
      LAYER M4 ;
        RECT  21.516 25.296 21.6 25.32 ;
    END
  END o[56]
  PIN o[570]
    DIRECTION OUTPUT ;
    USE SIGNAL ;
    PORT
      LAYER M4 ;
        RECT  21.516 15.504 21.6 15.528 ;
    END
  END o[570]
  PIN o[571]
    DIRECTION OUTPUT ;
    USE SIGNAL ;
    PORT
      LAYER M4 ;
        RECT  21.516 15.6 21.6 15.624 ;
    END
  END o[571]
  PIN o[572]
    DIRECTION OUTPUT ;
    USE SIGNAL ;
    PORT
      LAYER M4 ;
        RECT  21.516 15.696 21.6 15.72 ;
    END
  END o[572]
  PIN o[573]
    DIRECTION OUTPUT ;
    USE SIGNAL ;
    PORT
      LAYER M4 ;
        RECT  21.516 15.792 21.6 15.816 ;
    END
  END o[573]
  PIN o[574]
    DIRECTION OUTPUT ;
    USE SIGNAL ;
    PORT
      LAYER M4 ;
        RECT  21.516 15.888 21.6 15.912 ;
    END
  END o[574]
  PIN o[575]
    DIRECTION OUTPUT ;
    USE SIGNAL ;
    PORT
      LAYER M4 ;
        RECT  21.516 15.984 21.6 16.008 ;
    END
  END o[575]
  PIN o[576]
    DIRECTION OUTPUT ;
    USE SIGNAL ;
    PORT
      LAYER M4 ;
        RECT  21.516 0.72 21.6 0.744 ;
    END
  END o[576]
  PIN o[577]
    DIRECTION OUTPUT ;
    USE SIGNAL ;
    PORT
      LAYER M4 ;
        RECT  21.516 0.816 21.6 0.84 ;
    END
  END o[577]
  PIN o[578]
    DIRECTION OUTPUT ;
    USE SIGNAL ;
    PORT
      LAYER M4 ;
        RECT  21.516 0.912 21.6 0.936 ;
    END
  END o[578]
  PIN o[579]
    DIRECTION OUTPUT ;
    USE SIGNAL ;
    PORT
      LAYER M4 ;
        RECT  21.516 1.008 21.6 1.032 ;
    END
  END o[579]
  PIN o[57]
    DIRECTION OUTPUT ;
    USE SIGNAL ;
    PORT
      LAYER M4 ;
        RECT  21.516 25.392 21.6 25.416 ;
    END
  END o[57]
  PIN o[580]
    DIRECTION OUTPUT ;
    USE SIGNAL ;
    PORT
      LAYER M4 ;
        RECT  21.516 1.104 21.6 1.128 ;
    END
  END o[580]
  PIN o[581]
    DIRECTION OUTPUT ;
    USE SIGNAL ;
    PORT
      LAYER M4 ;
        RECT  21.516 1.2 21.6 1.224 ;
    END
  END o[581]
  PIN o[582]
    DIRECTION OUTPUT ;
    USE SIGNAL ;
    PORT
      LAYER M4 ;
        RECT  21.516 1.296 21.6 1.32 ;
    END
  END o[582]
  PIN o[583]
    DIRECTION OUTPUT ;
    USE SIGNAL ;
    PORT
      LAYER M4 ;
        RECT  21.516 1.392 21.6 1.416 ;
    END
  END o[583]
  PIN o[584]
    DIRECTION OUTPUT ;
    USE SIGNAL ;
    PORT
      LAYER M4 ;
        RECT  21.516 1.488 21.6 1.512 ;
    END
  END o[584]
  PIN o[585]
    DIRECTION OUTPUT ;
    USE SIGNAL ;
    PORT
      LAYER M4 ;
        RECT  21.516 1.584 21.6 1.608 ;
    END
  END o[585]
  PIN o[586]
    DIRECTION OUTPUT ;
    USE SIGNAL ;
    PORT
      LAYER M4 ;
        RECT  21.516 1.68 21.6 1.704 ;
    END
  END o[586]
  PIN o[587]
    DIRECTION OUTPUT ;
    USE SIGNAL ;
    PORT
      LAYER M4 ;
        RECT  21.516 1.776 21.6 1.8 ;
    END
  END o[587]
  PIN o[588]
    DIRECTION OUTPUT ;
    USE SIGNAL ;
    PORT
      LAYER M4 ;
        RECT  21.516 1.872 21.6 1.896 ;
    END
  END o[588]
  PIN o[589]
    DIRECTION OUTPUT ;
    USE SIGNAL ;
    PORT
      LAYER M4 ;
        RECT  21.516 1.968 21.6 1.992 ;
    END
  END o[589]
  PIN o[58]
    DIRECTION OUTPUT ;
    USE SIGNAL ;
    PORT
      LAYER M4 ;
        RECT  21.516 25.488 21.6 25.512 ;
    END
  END o[58]
  PIN o[590]
    DIRECTION OUTPUT ;
    USE SIGNAL ;
    PORT
      LAYER M4 ;
        RECT  21.516 2.064 21.6 2.088 ;
    END
  END o[590]
  PIN o[591]
    DIRECTION OUTPUT ;
    USE SIGNAL ;
    PORT
      LAYER M4 ;
        RECT  21.516 2.16 21.6 2.184 ;
    END
  END o[591]
  PIN o[592]
    DIRECTION OUTPUT ;
    USE SIGNAL ;
    PORT
      LAYER M4 ;
        RECT  21.516 2.256 21.6 2.28 ;
    END
  END o[592]
  PIN o[593]
    DIRECTION OUTPUT ;
    USE SIGNAL ;
    PORT
      LAYER M4 ;
        RECT  21.516 2.352 21.6 2.376 ;
    END
  END o[593]
  PIN o[594]
    DIRECTION OUTPUT ;
    USE SIGNAL ;
    PORT
      LAYER M4 ;
        RECT  21.516 2.448 21.6 2.472 ;
    END
  END o[594]
  PIN o[595]
    DIRECTION OUTPUT ;
    USE SIGNAL ;
    PORT
      LAYER M4 ;
        RECT  21.516 2.544 21.6 2.568 ;
    END
  END o[595]
  PIN o[596]
    DIRECTION OUTPUT ;
    USE SIGNAL ;
    PORT
      LAYER M4 ;
        RECT  21.516 2.64 21.6 2.664 ;
    END
  END o[596]
  PIN o[597]
    DIRECTION OUTPUT ;
    USE SIGNAL ;
    PORT
      LAYER M4 ;
        RECT  21.516 2.736 21.6 2.76 ;
    END
  END o[597]
  PIN o[598]
    DIRECTION OUTPUT ;
    USE SIGNAL ;
    PORT
      LAYER M4 ;
        RECT  21.516 2.832 21.6 2.856 ;
    END
  END o[598]
  PIN o[599]
    DIRECTION OUTPUT ;
    USE SIGNAL ;
    PORT
      LAYER M4 ;
        RECT  21.516 2.928 21.6 2.952 ;
    END
  END o[599]
  PIN o[59]
    DIRECTION OUTPUT ;
    USE SIGNAL ;
    PORT
      LAYER M4 ;
        RECT  21.516 25.584 21.6 25.608 ;
    END
  END o[59]
  PIN o[5]
    DIRECTION OUTPUT ;
    USE SIGNAL ;
    PORT
      LAYER M4 ;
        RECT  21.516 20.4 21.6 20.424 ;
    END
  END o[5]
  PIN o[600]
    DIRECTION OUTPUT ;
    USE SIGNAL ;
    PORT
      LAYER M4 ;
        RECT  21.516 3.024 21.6 3.048 ;
    END
  END o[600]
  PIN o[601]
    DIRECTION OUTPUT ;
    USE SIGNAL ;
    PORT
      LAYER M4 ;
        RECT  21.516 3.12 21.6 3.144 ;
    END
  END o[601]
  PIN o[602]
    DIRECTION OUTPUT ;
    USE SIGNAL ;
    PORT
      LAYER M4 ;
        RECT  21.516 3.216 21.6 3.24 ;
    END
  END o[602]
  PIN o[603]
    DIRECTION OUTPUT ;
    USE SIGNAL ;
    PORT
      LAYER M4 ;
        RECT  21.516 3.312 21.6 3.336 ;
    END
  END o[603]
  PIN o[604]
    DIRECTION OUTPUT ;
    USE SIGNAL ;
    PORT
      LAYER M4 ;
        RECT  21.516 3.408 21.6 3.432 ;
    END
  END o[604]
  PIN o[605]
    DIRECTION OUTPUT ;
    USE SIGNAL ;
    PORT
      LAYER M4 ;
        RECT  21.516 3.504 21.6 3.528 ;
    END
  END o[605]
  PIN o[606]
    DIRECTION OUTPUT ;
    USE SIGNAL ;
    PORT
      LAYER M4 ;
        RECT  21.516 3.6 21.6 3.624 ;
    END
  END o[606]
  PIN o[607]
    DIRECTION OUTPUT ;
    USE SIGNAL ;
    PORT
      LAYER M4 ;
        RECT  21.516 3.696 21.6 3.72 ;
    END
  END o[607]
  PIN o[608]
    DIRECTION OUTPUT ;
    USE SIGNAL ;
    PORT
      LAYER M4 ;
        RECT  21.516 61.392 21.6 61.416 ;
    END
  END o[608]
  PIN o[609]
    DIRECTION OUTPUT ;
    USE SIGNAL ;
    PORT
      LAYER M4 ;
        RECT  21.516 61.488 21.6 61.512 ;
    END
  END o[609]
  PIN o[60]
    DIRECTION OUTPUT ;
    USE SIGNAL ;
    PORT
      LAYER M4 ;
        RECT  21.516 25.68 21.6 25.704 ;
    END
  END o[60]
  PIN o[610]
    DIRECTION OUTPUT ;
    USE SIGNAL ;
    PORT
      LAYER M4 ;
        RECT  21.516 61.584 21.6 61.608 ;
    END
  END o[610]
  PIN o[611]
    DIRECTION OUTPUT ;
    USE SIGNAL ;
    PORT
      LAYER M4 ;
        RECT  21.516 61.68 21.6 61.704 ;
    END
  END o[611]
  PIN o[612]
    DIRECTION OUTPUT ;
    USE SIGNAL ;
    PORT
      LAYER M4 ;
        RECT  21.516 61.776 21.6 61.8 ;
    END
  END o[612]
  PIN o[613]
    DIRECTION OUTPUT ;
    USE SIGNAL ;
    PORT
      LAYER M4 ;
        RECT  21.516 61.872 21.6 61.896 ;
    END
  END o[613]
  PIN o[614]
    DIRECTION OUTPUT ;
    USE SIGNAL ;
    PORT
      LAYER M4 ;
        RECT  21.516 61.968 21.6 61.992 ;
    END
  END o[614]
  PIN o[615]
    DIRECTION OUTPUT ;
    USE SIGNAL ;
    PORT
      LAYER M4 ;
        RECT  21.516 62.064 21.6 62.088 ;
    END
  END o[615]
  PIN o[616]
    DIRECTION OUTPUT ;
    USE SIGNAL ;
    PORT
      LAYER M4 ;
        RECT  21.516 62.16 21.6 62.184 ;
    END
  END o[616]
  PIN o[617]
    DIRECTION OUTPUT ;
    USE SIGNAL ;
    PORT
      LAYER M4 ;
        RECT  21.516 62.256 21.6 62.28 ;
    END
  END o[617]
  PIN o[618]
    DIRECTION OUTPUT ;
    USE SIGNAL ;
    PORT
      LAYER M4 ;
        RECT  21.516 62.352 21.6 62.376 ;
    END
  END o[618]
  PIN o[619]
    DIRECTION OUTPUT ;
    USE SIGNAL ;
    PORT
      LAYER M4 ;
        RECT  21.516 62.448 21.6 62.472 ;
    END
  END o[619]
  PIN o[61]
    DIRECTION OUTPUT ;
    USE SIGNAL ;
    PORT
      LAYER M4 ;
        RECT  21.516 25.776 21.6 25.8 ;
    END
  END o[61]
  PIN o[620]
    DIRECTION OUTPUT ;
    USE SIGNAL ;
    PORT
      LAYER M4 ;
        RECT  21.516 62.544 21.6 62.568 ;
    END
  END o[620]
  PIN o[621]
    DIRECTION OUTPUT ;
    USE SIGNAL ;
    PORT
      LAYER M4 ;
        RECT  21.516 62.64 21.6 62.664 ;
    END
  END o[621]
  PIN o[622]
    DIRECTION OUTPUT ;
    USE SIGNAL ;
    PORT
      LAYER M4 ;
        RECT  21.516 62.736 21.6 62.76 ;
    END
  END o[622]
  PIN o[623]
    DIRECTION OUTPUT ;
    USE SIGNAL ;
    PORT
      LAYER M4 ;
        RECT  21.516 62.832 21.6 62.856 ;
    END
  END o[623]
  PIN o[62]
    DIRECTION OUTPUT ;
    USE SIGNAL ;
    PORT
      LAYER M4 ;
        RECT  21.516 25.872 21.6 25.896 ;
    END
  END o[62]
  PIN o[63]
    DIRECTION OUTPUT ;
    USE SIGNAL ;
    PORT
      LAYER M4 ;
        RECT  21.516 25.968 21.6 25.992 ;
    END
  END o[63]
  PIN o[64]
    DIRECTION OUTPUT ;
    USE SIGNAL ;
    PORT
      LAYER M4 ;
        RECT  21.516 32.208 21.6 32.232 ;
    END
  END o[64]
  PIN o[65]
    DIRECTION OUTPUT ;
    USE SIGNAL ;
    PORT
      LAYER M4 ;
        RECT  21.516 32.304 21.6 32.328 ;
    END
  END o[65]
  PIN o[66]
    DIRECTION OUTPUT ;
    USE SIGNAL ;
    PORT
      LAYER M4 ;
        RECT  21.516 32.4 21.6 32.424 ;
    END
  END o[66]
  PIN o[67]
    DIRECTION OUTPUT ;
    USE SIGNAL ;
    PORT
      LAYER M4 ;
        RECT  21.516 32.496 21.6 32.52 ;
    END
  END o[67]
  PIN o[68]
    DIRECTION OUTPUT ;
    USE SIGNAL ;
    PORT
      LAYER M4 ;
        RECT  21.516 32.592 21.6 32.616 ;
    END
  END o[68]
  PIN o[69]
    DIRECTION OUTPUT ;
    USE SIGNAL ;
    PORT
      LAYER M4 ;
        RECT  21.516 32.688 21.6 32.712 ;
    END
  END o[69]
  PIN o[6]
    DIRECTION OUTPUT ;
    USE SIGNAL ;
    PORT
      LAYER M4 ;
        RECT  21.516 20.496 21.6 20.52 ;
    END
  END o[6]
  PIN o[70]
    DIRECTION OUTPUT ;
    USE SIGNAL ;
    PORT
      LAYER M4 ;
        RECT  21.516 32.784 21.6 32.808 ;
    END
  END o[70]
  PIN o[71]
    DIRECTION OUTPUT ;
    USE SIGNAL ;
    PORT
      LAYER M4 ;
        RECT  21.516 32.88 21.6 32.904 ;
    END
  END o[71]
  PIN o[72]
    DIRECTION OUTPUT ;
    USE SIGNAL ;
    PORT
      LAYER M4 ;
        RECT  21.516 32.976 21.6 33 ;
    END
  END o[72]
  PIN o[73]
    DIRECTION OUTPUT ;
    USE SIGNAL ;
    PORT
      LAYER M4 ;
        RECT  21.516 33.072 21.6 33.096 ;
    END
  END o[73]
  PIN o[74]
    DIRECTION OUTPUT ;
    USE SIGNAL ;
    PORT
      LAYER M4 ;
        RECT  21.516 33.168 21.6 33.192 ;
    END
  END o[74]
  PIN o[75]
    DIRECTION OUTPUT ;
    USE SIGNAL ;
    PORT
      LAYER M4 ;
        RECT  21.516 33.264 21.6 33.288 ;
    END
  END o[75]
  PIN o[76]
    DIRECTION OUTPUT ;
    USE SIGNAL ;
    PORT
      LAYER M4 ;
        RECT  21.516 33.36 21.6 33.384 ;
    END
  END o[76]
  PIN o[77]
    DIRECTION OUTPUT ;
    USE SIGNAL ;
    PORT
      LAYER M4 ;
        RECT  21.516 33.456 21.6 33.48 ;
    END
  END o[77]
  PIN o[78]
    DIRECTION OUTPUT ;
    USE SIGNAL ;
    PORT
      LAYER M4 ;
        RECT  21.516 33.552 21.6 33.576 ;
    END
  END o[78]
  PIN o[79]
    DIRECTION OUTPUT ;
    USE SIGNAL ;
    PORT
      LAYER M4 ;
        RECT  21.516 33.648 21.6 33.672 ;
    END
  END o[79]
  PIN o[7]
    DIRECTION OUTPUT ;
    USE SIGNAL ;
    PORT
      LAYER M4 ;
        RECT  21.516 20.592 21.6 20.616 ;
    END
  END o[7]
  PIN o[80]
    DIRECTION OUTPUT ;
    USE SIGNAL ;
    PORT
      LAYER M4 ;
        RECT  21.516 33.744 21.6 33.768 ;
    END
  END o[80]
  PIN o[81]
    DIRECTION OUTPUT ;
    USE SIGNAL ;
    PORT
      LAYER M4 ;
        RECT  21.516 33.84 21.6 33.864 ;
    END
  END o[81]
  PIN o[82]
    DIRECTION OUTPUT ;
    USE SIGNAL ;
    PORT
      LAYER M4 ;
        RECT  21.516 33.936 21.6 33.96 ;
    END
  END o[82]
  PIN o[83]
    DIRECTION OUTPUT ;
    USE SIGNAL ;
    PORT
      LAYER M4 ;
        RECT  21.516 34.032 21.6 34.056 ;
    END
  END o[83]
  PIN o[84]
    DIRECTION OUTPUT ;
    USE SIGNAL ;
    PORT
      LAYER M4 ;
        RECT  21.516 34.128 21.6 34.152 ;
    END
  END o[84]
  PIN o[85]
    DIRECTION OUTPUT ;
    USE SIGNAL ;
    PORT
      LAYER M4 ;
        RECT  21.516 34.224 21.6 34.248 ;
    END
  END o[85]
  PIN o[86]
    DIRECTION OUTPUT ;
    USE SIGNAL ;
    PORT
      LAYER M4 ;
        RECT  21.516 34.32 21.6 34.344 ;
    END
  END o[86]
  PIN o[87]
    DIRECTION OUTPUT ;
    USE SIGNAL ;
    PORT
      LAYER M4 ;
        RECT  21.516 34.416 21.6 34.44 ;
    END
  END o[87]
  PIN o[88]
    DIRECTION OUTPUT ;
    USE SIGNAL ;
    PORT
      LAYER M4 ;
        RECT  21.516 34.512 21.6 34.536 ;
    END
  END o[88]
  PIN o[89]
    DIRECTION OUTPUT ;
    USE SIGNAL ;
    PORT
      LAYER M4 ;
        RECT  21.516 34.608 21.6 34.632 ;
    END
  END o[89]
  PIN o[8]
    DIRECTION OUTPUT ;
    USE SIGNAL ;
    PORT
      LAYER M4 ;
        RECT  21.516 20.688 21.6 20.712 ;
    END
  END o[8]
  PIN o[90]
    DIRECTION OUTPUT ;
    USE SIGNAL ;
    PORT
      LAYER M4 ;
        RECT  21.516 34.704 21.6 34.728 ;
    END
  END o[90]
  PIN o[91]
    DIRECTION OUTPUT ;
    USE SIGNAL ;
    PORT
      LAYER M4 ;
        RECT  21.516 34.8 21.6 34.824 ;
    END
  END o[91]
  PIN o[92]
    DIRECTION OUTPUT ;
    USE SIGNAL ;
    PORT
      LAYER M4 ;
        RECT  21.516 34.896 21.6 34.92 ;
    END
  END o[92]
  PIN o[93]
    DIRECTION OUTPUT ;
    USE SIGNAL ;
    PORT
      LAYER M4 ;
        RECT  21.516 34.992 21.6 35.016 ;
    END
  END o[93]
  PIN o[94]
    DIRECTION OUTPUT ;
    USE SIGNAL ;
    PORT
      LAYER M4 ;
        RECT  21.516 35.088 21.6 35.112 ;
    END
  END o[94]
  PIN o[95]
    DIRECTION OUTPUT ;
    USE SIGNAL ;
    PORT
      LAYER M4 ;
        RECT  21.516 35.184 21.6 35.208 ;
    END
  END o[95]
  PIN o[96]
    DIRECTION OUTPUT ;
    USE SIGNAL ;
    PORT
      LAYER M4 ;
        RECT  21.516 29.136 21.6 29.16 ;
    END
  END o[96]
  PIN o[97]
    DIRECTION OUTPUT ;
    USE SIGNAL ;
    PORT
      LAYER M4 ;
        RECT  21.516 29.232 21.6 29.256 ;
    END
  END o[97]
  PIN o[98]
    DIRECTION OUTPUT ;
    USE SIGNAL ;
    PORT
      LAYER M4 ;
        RECT  21.516 29.328 21.6 29.352 ;
    END
  END o[98]
  PIN o[99]
    DIRECTION OUTPUT ;
    USE SIGNAL ;
    PORT
      LAYER M4 ;
        RECT  21.516 29.424 21.6 29.448 ;
    END
  END o[99]
  PIN o[9]
    DIRECTION OUTPUT ;
    USE SIGNAL ;
    PORT
      LAYER M4 ;
        RECT  21.516 20.784 21.6 20.808 ;
    END
  END o[9]
  PIN rs
    DIRECTION INPUT ;
    USE SIGNAL ;
    PORT
      LAYER M5 ;
        RECT  10.8 0 10.824 0.084 ;
    END
  END rs
  PIN VDD
    DIRECTION INOUT ;
    USE POWER ;
    PORT
      LAYER M5 ;
        RECT  18.792 2.151 18.912 62.649 ;
        RECT  16.092 2.151 16.212 62.649 ;
        RECT  13.392 2.151 13.512 62.649 ;
        RECT  10.692 2.151 10.812 62.649 ;
        RECT  7.992 2.151 8.112 62.649 ;
        RECT  5.292 2.151 5.412 62.649 ;
        RECT  2.592 2.151 2.712 62.649 ;
    END
  END VDD
  PIN VSS
    DIRECTION INOUT ;
    USE GROUND ;
    PORT
      LAYER M5 ;
        RECT  18.6 2.137 18.72 62.663 ;
        RECT  15.9 2.137 16.02 62.663 ;
        RECT  13.2 2.137 13.32 62.663 ;
        RECT  10.5 2.137 10.62 62.663 ;
        RECT  7.8 2.137 7.92 62.663 ;
        RECT  5.1 2.137 5.22 62.663 ;
        RECT  2.4 2.137 2.52 62.663 ;
    END
  END VSS
  # OT_OBS_CLOSED layer=M5 d_um=1.536 added=145
  OBS
    LAYER RVTN ;
     RECT  2.16 2.16 19.44 2.295 ;
     RECT  2.16 2.565 19.44 2.835 ;
     RECT  2.16 3.105 19.44 3.375 ;
     RECT  2.16 3.645 19.44 3.915 ;
     RECT  2.16 4.185 19.44 4.455 ;
     RECT  2.16 4.725 19.44 4.995 ;
     RECT  2.16 5.265 19.44 5.535 ;
     RECT  2.16 5.805 19.44 6.075 ;
     RECT  2.16 6.345 19.44 6.615 ;
     RECT  2.16 6.885 19.44 7.155 ;
     RECT  2.16 7.425 19.44 7.695 ;
     RECT  2.16 7.965 19.44 8.235 ;
     RECT  2.16 8.505 19.44 8.775 ;
     RECT  2.16 9.045 19.44 9.315 ;
     RECT  2.16 9.585 19.44 9.855 ;
     RECT  2.16 10.125 19.44 10.395 ;
     RECT  2.16 10.665 19.44 10.935 ;
     RECT  2.16 11.205 19.44 11.475 ;
     RECT  2.16 11.745 19.44 12.015 ;
     RECT  2.16 12.285 19.44 12.555 ;
     RECT  2.16 12.825 19.44 13.095 ;
     RECT  2.16 13.365 19.44 13.635 ;
     RECT  2.16 13.905 19.44 14.175 ;
     RECT  2.16 14.445 19.44 14.715 ;
     RECT  2.16 14.985 19.44 15.255 ;
     RECT  2.16 15.525 19.44 15.795 ;
     RECT  2.16 16.065 19.44 16.335 ;
     RECT  2.16 16.605 19.44 16.875 ;
     RECT  2.16 17.145 19.44 17.415 ;
     RECT  2.16 17.685 19.44 17.955 ;
     RECT  2.16 18.225 19.44 18.495 ;
     RECT  2.16 18.765 19.44 19.035 ;
     RECT  2.16 19.305 19.44 19.575 ;
     RECT  2.16 19.845 19.44 20.115 ;
     RECT  2.16 20.385 19.44 20.655 ;
     RECT  2.16 20.925 19.44 21.195 ;
     RECT  2.16 21.465 19.44 21.735 ;
     RECT  2.16 22.005 19.44 22.275 ;
     RECT  2.16 22.545 19.44 22.815 ;
     RECT  2.16 23.085 19.44 23.355 ;
     RECT  2.16 23.625 19.44 23.895 ;
     RECT  2.16 24.165 19.44 24.435 ;
     RECT  2.16 24.705 19.44 24.975 ;
     RECT  2.16 25.245 19.44 25.515 ;
     RECT  2.16 25.785 19.44 26.055 ;
     RECT  2.16 26.325 19.44 26.595 ;
     RECT  2.16 26.865 19.44 27.135 ;
     RECT  2.16 27.405 19.44 27.675 ;
     RECT  2.16 27.945 19.44 28.215 ;
     RECT  2.16 28.485 19.44 28.755 ;
     RECT  2.16 29.025 19.44 29.295 ;
     RECT  2.16 29.565 19.44 29.835 ;
     RECT  2.16 30.105 19.44 30.375 ;
     RECT  2.16 30.645 19.44 30.915 ;
     RECT  2.16 31.185 19.44 31.455 ;
     RECT  2.16 31.725 19.44 31.995 ;
     RECT  2.16 32.265 19.44 32.535 ;
     RECT  2.16 32.805 19.44 33.075 ;
     RECT  2.16 33.345 19.44 33.615 ;
     RECT  2.16 33.885 19.44 34.155 ;
     RECT  2.16 34.425 19.44 34.695 ;
     RECT  2.16 34.965 19.44 35.235 ;
     RECT  2.16 35.505 19.44 35.775 ;
     RECT  2.16 36.045 19.44 36.315 ;
     RECT  2.16 36.585 19.44 36.855 ;
     RECT  2.16 37.125 19.44 37.395 ;
     RECT  2.16 37.665 19.44 37.935 ;
     RECT  2.16 38.205 19.44 38.475 ;
     RECT  2.16 38.745 19.44 39.015 ;
     RECT  2.16 39.285 19.44 39.555 ;
     RECT  2.16 39.825 19.44 40.095 ;
     RECT  2.16 40.365 19.44 40.635 ;
     RECT  2.16 40.905 19.44 41.175 ;
     RECT  2.16 41.445 19.44 41.715 ;
     RECT  2.16 41.985 19.44 42.255 ;
     RECT  2.16 42.525 19.44 42.795 ;
     RECT  2.16 43.065 19.44 43.335 ;
     RECT  2.16 43.605 19.44 43.875 ;
     RECT  2.16 44.145 19.44 44.415 ;
     RECT  2.16 44.685 19.44 44.955 ;
     RECT  2.16 45.225 19.44 45.495 ;
     RECT  2.16 45.765 19.44 46.035 ;
     RECT  2.16 46.305 19.44 46.575 ;
     RECT  2.16 46.845 19.44 47.115 ;
     RECT  2.16 47.385 19.44 47.655 ;
     RECT  2.16 47.925 19.44 48.195 ;
     RECT  2.16 48.465 19.44 48.735 ;
     RECT  2.16 49.005 19.44 49.275 ;
     RECT  2.16 49.545 19.44 49.815 ;
     RECT  2.16 50.085 19.44 50.355 ;
     RECT  2.16 50.625 19.44 50.895 ;
     RECT  2.16 51.165 19.44 51.435 ;
     RECT  2.16 51.705 19.44 51.975 ;
     RECT  2.16 52.245 19.44 52.515 ;
     RECT  2.16 52.785 19.44 53.055 ;
     RECT  2.16 53.325 19.44 53.595 ;
     RECT  2.16 53.865 19.44 54.135 ;
     RECT  2.16 54.405 19.44 54.675 ;
     RECT  2.16 54.945 19.44 55.215 ;
     RECT  2.16 55.485 19.44 55.755 ;
     RECT  2.16 56.025 19.44 56.295 ;
     RECT  2.16 56.565 19.44 56.835 ;
     RECT  2.16 57.105 19.44 57.375 ;
     RECT  2.16 57.645 19.44 57.915 ;
     RECT  2.16 58.185 19.44 58.455 ;
     RECT  2.16 58.725 19.44 58.995 ;
     RECT  2.16 59.265 19.44 59.535 ;
     RECT  2.16 59.805 19.44 60.075 ;
     RECT  2.16 60.345 19.44 60.615 ;
     RECT  2.16 60.885 19.44 61.155 ;
     RECT  2.16 61.425 19.44 61.695 ;
     RECT  2.16 61.965 19.44 62.235 ;
     RECT  2.16 62.505 19.44 62.64 ;
    LAYER RVTP ;
     RECT  2.16 2.295 19.44 2.565 ;
     RECT  2.16 2.835 19.44 3.105 ;
     RECT  2.16 3.375 19.44 3.645 ;
     RECT  2.16 3.915 19.44 4.185 ;
     RECT  2.16 4.455 19.44 4.725 ;
     RECT  2.16 4.995 19.44 5.265 ;
     RECT  2.16 5.535 19.44 5.805 ;
     RECT  2.16 6.075 19.44 6.345 ;
     RECT  2.16 6.615 19.44 6.885 ;
     RECT  2.16 7.155 19.44 7.425 ;
     RECT  2.16 7.695 19.44 7.965 ;
     RECT  2.16 8.235 19.44 8.505 ;
     RECT  2.16 8.775 19.44 9.045 ;
     RECT  2.16 9.315 19.44 9.585 ;
     RECT  2.16 9.855 19.44 10.125 ;
     RECT  2.16 10.395 19.44 10.665 ;
     RECT  2.16 10.935 19.44 11.205 ;
     RECT  2.16 11.475 19.44 11.745 ;
     RECT  2.16 12.015 19.44 12.285 ;
     RECT  2.16 12.555 19.44 12.825 ;
     RECT  2.16 13.095 19.44 13.365 ;
     RECT  2.16 13.635 19.44 13.905 ;
     RECT  2.16 14.175 19.44 14.445 ;
     RECT  2.16 14.715 19.44 14.985 ;
     RECT  2.16 15.255 19.44 15.525 ;
     RECT  2.16 15.795 19.44 16.065 ;
     RECT  2.16 16.335 19.44 16.605 ;
     RECT  2.16 16.875 19.44 17.145 ;
     RECT  2.16 17.415 19.44 17.685 ;
     RECT  2.16 17.955 19.44 18.225 ;
     RECT  2.16 18.495 19.44 18.765 ;
     RECT  2.16 19.035 19.44 19.305 ;
     RECT  2.16 19.575 19.44 19.845 ;
     RECT  2.16 20.115 19.44 20.385 ;
     RECT  2.16 20.655 19.44 20.925 ;
     RECT  2.16 21.195 19.44 21.465 ;
     RECT  2.16 21.735 19.44 22.005 ;
     RECT  2.16 22.275 19.44 22.545 ;
     RECT  2.16 22.815 19.44 23.085 ;
     RECT  2.16 23.355 19.44 23.625 ;
     RECT  2.16 23.895 19.44 24.165 ;
     RECT  2.16 24.435 19.44 24.705 ;
     RECT  2.16 24.975 19.44 25.245 ;
     RECT  2.16 25.515 19.44 25.785 ;
     RECT  2.16 26.055 19.44 26.325 ;
     RECT  2.16 26.595 19.44 26.865 ;
     RECT  2.16 27.135 19.44 27.405 ;
     RECT  2.16 27.675 19.44 27.945 ;
     RECT  2.16 28.215 19.44 28.485 ;
     RECT  2.16 28.755 19.44 29.025 ;
     RECT  2.16 29.295 19.44 29.565 ;
     RECT  2.16 29.835 19.44 30.105 ;
     RECT  2.16 30.375 19.44 30.645 ;
     RECT  2.16 30.915 19.44 31.185 ;
     RECT  2.16 31.455 19.44 31.725 ;
     RECT  2.16 31.995 19.44 32.265 ;
     RECT  2.16 32.535 19.44 32.805 ;
     RECT  2.16 33.075 19.44 33.345 ;
     RECT  2.16 33.615 19.44 33.885 ;
     RECT  2.16 34.155 19.44 34.425 ;
     RECT  2.16 34.695 19.44 34.965 ;
     RECT  2.16 35.235 19.44 35.505 ;
     RECT  2.16 35.775 19.44 36.045 ;
     RECT  2.16 36.315 19.44 36.585 ;
     RECT  2.16 36.855 19.44 37.125 ;
     RECT  2.16 37.395 19.44 37.665 ;
     RECT  2.16 37.935 19.44 38.205 ;
     RECT  2.16 38.475 19.44 38.745 ;
     RECT  2.16 39.015 19.44 39.285 ;
     RECT  2.16 39.555 19.44 39.825 ;
     RECT  2.16 40.095 19.44 40.365 ;
     RECT  2.16 40.635 19.44 40.905 ;
     RECT  2.16 41.175 19.44 41.445 ;
     RECT  2.16 41.715 19.44 41.985 ;
     RECT  2.16 42.255 19.44 42.525 ;
     RECT  2.16 42.795 19.44 43.065 ;
     RECT  2.16 43.335 19.44 43.605 ;
     RECT  2.16 43.875 19.44 44.145 ;
     RECT  2.16 44.415 19.44 44.685 ;
     RECT  2.16 44.955 19.44 45.225 ;
     RECT  2.16 45.495 19.44 45.765 ;
     RECT  2.16 46.035 19.44 46.305 ;
     RECT  2.16 46.575 19.44 46.845 ;
     RECT  2.16 47.115 19.44 47.385 ;
     RECT  2.16 47.655 19.44 47.925 ;
     RECT  2.16 48.195 19.44 48.465 ;
     RECT  2.16 48.735 19.44 49.005 ;
     RECT  2.16 49.275 19.44 49.545 ;
     RECT  2.16 49.815 19.44 50.085 ;
     RECT  2.16 50.355 19.44 50.625 ;
     RECT  2.16 50.895 19.44 51.165 ;
     RECT  2.16 51.435 19.44 51.705 ;
     RECT  2.16 51.975 19.44 52.245 ;
     RECT  2.16 52.515 19.44 52.785 ;
     RECT  2.16 53.055 19.44 53.325 ;
     RECT  2.16 53.595 19.44 53.865 ;
     RECT  2.16 54.135 19.44 54.405 ;
     RECT  2.16 54.675 19.44 54.945 ;
     RECT  2.16 55.215 19.44 55.485 ;
     RECT  2.16 55.755 19.44 56.025 ;
     RECT  2.16 56.295 19.44 56.565 ;
     RECT  2.16 56.835 19.44 57.105 ;
     RECT  2.16 57.375 19.44 57.645 ;
     RECT  2.16 57.915 19.44 58.185 ;
     RECT  2.16 58.455 19.44 58.725 ;
     RECT  2.16 58.995 19.44 59.265 ;
     RECT  2.16 59.535 19.44 59.805 ;
     RECT  2.16 60.075 19.44 60.345 ;
     RECT  2.16 60.615 19.44 60.885 ;
     RECT  2.16 61.155 19.44 61.425 ;
     RECT  2.16 61.695 19.44 61.965 ;
     RECT  2.16 62.235 19.44 62.505 ;
    LAYER M1 ;
     RECT  2.16 2.151 19.44 62.649 ;
    LAYER M2 ;
     RECT  0.031 30.816 0.067 30.834 ;
     RECT  0.031 39.6 0.067 39.618 ;
     RECT  0.031 54.846 0.067 54.864 ;
     RECT  0.031 29.34 0.103 29.358 ;
     RECT  0.067 30.114 0.103 30.834 ;
     RECT  0.031 34.74 0.103 34.758 ;
     RECT  0.067 39.6 0.103 39.852 ;
     RECT  0.031 48.546 0.103 48.564 ;
     RECT  0.067 50.751 0.103 50.769 ;
     RECT  0.067 54.414 0.103 54.864 ;
     RECT  0.067 58.5 0.103 58.518 ;
     RECT  0.067 61.362 0.103 61.38 ;
     RECT  0.103 29.34 0.131 30.834 ;
     RECT  0.103 2.61 0.139 2.628 ;
     RECT  0.103 3.96 0.139 4.482 ;
     RECT  0.103 6.822 0.139 6.84 ;
     RECT  0.103 7.74 0.139 8.532 ;
     RECT  0.103 10.71 0.139 10.728 ;
     RECT  0.103 13.644 0.139 13.662 ;
     RECT  0.103 14.76 0.139 14.94 ;
     RECT  0.103 15.804 0.139 15.822 ;
     RECT  0.103 22.212 0.139 22.23 ;
     RECT  0.103 22.986 0.139 23.922 ;
     RECT  0.103 26.1 0.139 26.118 ;
     RECT  0.103 34.74 0.139 35.298 ;
     RECT  0.103 36.09 0.139 36.108 ;
     RECT  0.103 39.6 0.139 40.428 ;
     RECT  0.103 41.49 0.139 41.94 ;
     RECT  0.103 42.732 0.139 43.29 ;
     RECT  0.103 48.438 0.139 48.564 ;
     RECT  0.103 50.67 0.139 50.769 ;
     RECT  0.103 54.342 0.139 55.548 ;
     RECT  0.103 56.304 0.139 56.322 ;
     RECT  0.067 57.618 0.139 57.636 ;
     RECT  0.103 58.5 0.139 61.38 ;
     RECT  0.067 33.822 0.167 33.84 ;
     RECT  0.067 44.496 0.167 44.514 ;
     RECT  0.139 57.618 0.167 61.38 ;
     RECT  0.139 10.44 0.175 10.728 ;
     RECT  0.139 15.804 0.175 15.858 ;
     RECT  0.139 25.83 0.175 26.118 ;
     RECT  0.139 39.6 0.175 40.626 ;
     RECT  0.139 50.4 0.175 50.769 ;
     RECT  0.139 6.822 0.203 8.532 ;
     RECT  0.175 49.896 0.203 50.769 ;
     RECT  0.175 45.54 0.211 45.558 ;
     RECT  0.031 46.35 0.211 46.764 ;
     RECT  0.139 47.7 0.211 48.564 ;
     RECT  0.203 49.896 0.211 50.688 ;
     RECT  0.175 52.182 0.211 52.2 ;
     RECT  0.139 14.526 0.239 14.94 ;
     RECT  0.211 52.182 0.247 52.74 ;
     RECT  0.103 53.568 0.247 53.586 ;
     RECT  0.175 20.7 0.347 20.718 ;
     RECT  0.139 22.212 0.347 24.498 ;
     RECT  0.247 33.084 0.347 33.444 ;
     RECT  0.427 32.274 0.463 32.292 ;
     RECT  0.175 38.682 0.463 40.626 ;
     RECT  0.139 41.49 0.463 43.29 ;
     RECT  0.463 32.274 0.499 32.364 ;
     RECT  0.211 45.54 0.499 46.764 ;
     RECT  0.211 47.7 0.499 50.688 ;
     RECT  0.175 10.44 0.535 10.89 ;
     RECT  0.175 15.768 0.535 15.858 ;
     RECT  0.103 16.65 0.535 16.668 ;
     RECT  0.347 23.328 0.535 24.498 ;
     RECT  0.499 37.44 0.535 37.458 ;
     RECT  0.347 33.426 1.111 33.444 ;
     RECT  0.131 29.34 1.147 30.708 ;
     RECT  0.463 38.682 1.147 43.902 ;
     RECT  0.535 10.44 1.183 11.232 ;
     RECT  0.247 52.182 1.471 53.586 ;
     RECT  0.139 54.342 1.471 56.322 ;
     RECT  0.167 57.924 1.651 61.38 ;
     RECT  0.103 62.208 1.651 62.226 ;
     RECT  1.183 10.44 1.723 11.574 ;
     RECT  1.219 12.492 1.795 12.51 ;
     RECT  0.139 13.572 1.795 13.662 ;
     RECT  0.139 2.61 2.16 4.482 ;
     RECT  0.103 5.58 2.16 5.598 ;
     RECT  0.203 6.822 2.16 7.758 ;
     RECT  0.203 8.514 2.16 8.532 ;
     RECT  1.723 10.44 2.16 11.7 ;
     RECT  1.795 12.492 2.16 13.662 ;
     RECT  0.239 14.76 2.16 14.778 ;
     RECT  0.535 15.768 2.16 16.668 ;
     RECT  0.211 17.928 2.16 17.946 ;
     RECT  0.103 18.774 2.16 18.792 ;
     RECT  1.723 21.132 2.16 21.15 ;
     RECT  0.347 22.212 2.16 22.23 ;
     RECT  0.535 23.328 2.16 24.768 ;
     RECT  0.175 25.83 2.16 26.586 ;
     RECT  0.535 27.684 2.16 27.702 ;
     RECT  0.103 28.458 2.16 28.476 ;
     RECT  1.147 29.34 2.16 31.248 ;
     RECT  0.499 32.076 2.16 32.364 ;
     RECT  1.111 33.39 2.16 33.444 ;
     RECT  0.139 34.74 2.16 36.108 ;
     RECT  0.535 37.44 2.16 37.494 ;
     RECT  1.147 38.682 2.16 44.136 ;
     RECT  0.499 45.54 2.16 50.688 ;
     RECT  1.471 52.182 2.16 56.322 ;
     RECT  1.651 57.924 2.16 62.226 ;
     RECT  2.16 2.151 3.127 62.649 ;
     RECT  3.127 2.151 3.343 62.694 ;
     RECT  3.343 2.07 3.847 62.694 ;
     RECT  3.847 2.034 5.675 62.694 ;
     RECT  5.675 2.034 11.255 62.649 ;
     RECT  11.255 2.07 12.127 62.649 ;
     RECT  12.127 1.962 13.999 62.649 ;
     RECT  13.999 1.926 14.827 62.649 ;
     RECT  14.827 1.764 18.815 62.649 ;
     RECT  18.815 1.881 19.103 62.649 ;
     RECT  19.103 2.151 19.44 62.649 ;
     RECT  19.44 2.268 20.219 62.424 ;
     RECT  20.219 4.536 20.435 62.424 ;
     RECT  20.435 4.536 20.471 6.102 ;
     RECT  20.435 6.966 20.471 7.074 ;
     RECT  20.435 7.866 20.471 32.454 ;
     RECT  20.435 33.246 20.471 51.804 ;
     RECT  20.471 4.536 20.507 5.994 ;
     RECT  20.471 7.866 20.507 11.394 ;
     RECT  20.471 12.456 20.507 14.094 ;
     RECT  20.471 15.156 20.507 24.804 ;
     RECT  20.471 25.686 20.507 32.454 ;
     RECT  20.471 33.39 20.507 35.028 ;
     RECT  20.471 35.784 20.507 45.864 ;
     RECT  20.471 48.366 20.507 51.804 ;
     RECT  20.435 52.56 20.507 62.424 ;
     RECT  20.507 4.536 20.543 5.562 ;
     RECT  20.507 10.476 20.543 10.494 ;
     RECT  20.507 21.096 20.543 21.114 ;
     RECT  20.507 22.014 20.543 23.922 ;
     RECT  20.507 26.064 20.543 26.082 ;
     RECT  20.507 26.874 20.543 26.892 ;
     RECT  20.507 28.026 20.543 29.052 ;
     RECT  20.507 29.916 20.543 29.934 ;
     RECT  20.507 35.784 20.543 37.224 ;
     RECT  20.507 39.096 20.543 41.004 ;
     RECT  20.471 46.854 20.543 47.61 ;
     RECT  20.507 50.562 20.543 50.58 ;
     RECT  20.507 53.136 20.543 53.154 ;
     RECT  20.507 58.041 20.543 60.84 ;
     RECT  20.507 62.316 20.543 62.334 ;
     RECT  20.219 2.268 20.579 3.744 ;
     RECT  20.507 8.244 20.579 9.072 ;
     RECT  20.543 22.014 20.579 22.104 ;
     RECT  20.543 28.494 20.579 28.98 ;
     RECT  20.543 36.396 20.579 37.224 ;
     RECT  20.507 41.994 20.579 45.864 ;
     RECT  20.543 59.544 20.579 60.84 ;
     RECT  20.543 4.536 20.615 5.058 ;
     RECT  20.579 8.244 20.615 8.604 ;
     RECT  20.579 22.014 20.615 22.032 ;
     RECT  20.507 31.266 20.615 32.454 ;
     RECT  20.543 58.041 20.615 58.716 ;
     RECT  20.579 42.03 20.651 45.864 ;
     RECT  20.615 58.041 20.651 58.41 ;
     RECT  20.579 2.268 21.335 3.402 ;
     RECT  20.579 60.048 21.371 60.84 ;
     RECT  20.507 12.636 21.415 12.654 ;
     RECT  20.543 22.986 21.415 23.922 ;
     RECT  20.507 11.286 21.443 11.394 ;
     RECT  21.415 22.896 21.443 23.922 ;
     RECT  20.543 39.87 21.443 41.004 ;
     RECT  20.651 58.041 21.443 58.059 ;
     RECT  21.335 2.574 21.479 3.402 ;
     RECT  20.507 18.504 21.479 19.134 ;
     RECT  20.507 19.926 21.479 20.34 ;
     RECT  21.443 23.904 21.479 23.922 ;
     RECT  20.615 31.356 21.479 32.454 ;
     RECT  20.507 33.39 21.479 33.714 ;
     RECT  20.579 36.396 21.479 36.684 ;
     RECT  20.651 43.236 21.479 45.864 ;
     RECT  20.543 46.854 21.479 47.304 ;
     RECT  20.507 48.366 21.479 48.798 ;
     RECT  20.507 54.954 21.479 54.972 ;
     RECT  20.507 55.926 21.479 56.088 ;
     RECT  21.371 60.048 21.479 60.408 ;
     RECT  21.479 3.186 21.515 3.204 ;
     RECT  20.615 5.04 21.515 5.058 ;
     RECT  20.471 6.966 21.515 6.984 ;
     RECT  20.615 8.586 21.515 8.604 ;
     RECT  21.443 11.376 21.515 11.394 ;
     RECT  21.415 12.636 21.515 13.194 ;
     RECT  20.507 13.986 21.515 14.004 ;
     RECT  20.507 15.156 21.515 15.822 ;
     RECT  20.507 17.082 21.515 17.604 ;
     RECT  21.479 18.504 21.515 18.522 ;
     RECT  21.479 19.926 21.515 19.944 ;
     RECT  21.443 22.896 21.515 23.004 ;
     RECT  20.507 24.786 21.515 24.804 ;
     RECT  20.579 28.764 21.515 28.98 ;
     RECT  21.479 31.356 21.515 31.824 ;
     RECT  21.479 33.696 21.515 33.714 ;
     RECT  21.479 36.396 21.515 36.414 ;
     RECT  20.543 39.096 21.515 39.114 ;
     RECT  21.443 39.87 21.515 40.194 ;
     RECT  21.443 40.986 21.515 41.004 ;
     RECT  20.651 42.03 21.515 42.354 ;
     RECT  21.479 43.236 21.515 44.982 ;
     RECT  21.479 45.846 21.515 45.864 ;
     RECT  21.479 47.016 21.515 47.304 ;
     RECT  21.479 48.78 21.515 48.798 ;
     RECT  20.507 51.786 21.515 51.804 ;
     RECT  21.415 52.956 21.515 52.974 ;
     RECT  21.479 56.07 21.515 56.088 ;
     RECT  21.479 60.048 21.515 60.066 ;
     RECT  21.415 61.596 21.515 61.614 ;
    LAYER M3 ;
     RECT  19.368 0.715 19.386 0.811 ;
     RECT  21.492 0.907 21.51 1.003 ;
     RECT  19.368 0.811 19.71 1.099 ;
     RECT  19.368 1.099 19.782 1.195 ;
     RECT  19.368 1.195 19.926 1.291 ;
     RECT  18.108 1.579 18.126 1.675 ;
     RECT  18.108 1.675 18.522 1.759 ;
     RECT  19.368 1.291 20.214 1.759 ;
     RECT  14.832 1.759 14.85 1.831 ;
     RECT  18.108 1.759 20.214 1.831 ;
     RECT  21.456 1.003 21.51 1.867 ;
     RECT  17.28 1.387 17.298 1.876 ;
     RECT  18.036 1.831 20.214 1.876 ;
     RECT  14.004 1.921 14.022 1.957 ;
     RECT  14.832 1.831 15.354 1.957 ;
     RECT  17.28 1.876 20.214 1.957 ;
     RECT  21.42 1.867 21.51 1.963 ;
     RECT  14.832 1.957 15.426 1.993 ;
     RECT  2.304 1.867 2.322 2.011 ;
     RECT  4.356 1.963 4.374 2.029 ;
     RECT  12.132 1.957 12.15 2.029 ;
     RECT  13.644 1.957 14.022 2.029 ;
     RECT  14.832 1.993 15.858 2.029 ;
     RECT  16.992 1.957 20.214 2.029 ;
     RECT  3.852 2.029 4.374 2.059 ;
     RECT  3.636 2.059 4.374 2.065 ;
     RECT  11.232 2.029 11.25 2.065 ;
     RECT  12.132 2.029 15.858 2.065 ;
     RECT  16.92 2.029 20.214 2.065 ;
     RECT  2.304 2.011 2.358 2.143 ;
     RECT  10.44 2.011 10.458 2.143 ;
     RECT  11.232 2.065 20.214 2.143 ;
     RECT  21.384 1.963 21.51 2.155 ;
     RECT  3.348 2.065 4.374 2.191 ;
     RECT  5.115 2.143 5.205 2.191 ;
     RECT  10.44 2.143 20.214 2.191 ;
     RECT  2.304 2.143 2.505 2.251 ;
     RECT  3.348 2.191 5.205 2.251 ;
     RECT  21.348 2.155 21.51 2.263 ;
     RECT  7.815 2.143 7.905 2.293 ;
     RECT  2.304 2.251 5.205 2.299 ;
     RECT  5.94 2.101 5.958 2.299 ;
     RECT  10.296 2.191 20.214 2.299 ;
     RECT  7.596 2.293 7.905 2.335 ;
     RECT  6.912 2.335 7.905 2.371 ;
     RECT  21.312 2.263 21.51 2.381 ;
     RECT  6.912 2.371 8.838 2.497 ;
     RECT  10.296 2.299 20.538 2.497 ;
     RECT  6.912 2.497 9.342 2.533 ;
     RECT  10.188 2.497 20.538 2.533 ;
     RECT  0.324 2.155 0.342 2.605 ;
     RECT  2.304 2.299 5.958 2.641 ;
     RECT  6.912 2.533 20.538 2.641 ;
     RECT  2.304 2.641 20.538 2.765 ;
     RECT  0.108 2.605 0.342 2.861 ;
     RECT  21.348 2.381 21.51 3.403 ;
     RECT  21.312 3.403 21.51 3.629 ;
     RECT  2.304 2.765 20.214 3.691 ;
     RECT  0.108 2.861 0.234 3.919 ;
     RECT  0.108 3.919 0.558 4.109 ;
     RECT  2.304 3.691 20.61 4.153 ;
     RECT  2.268 4.153 20.61 4.559 ;
     RECT  2.268 4.559 20.538 4.657 ;
     RECT  2.196 4.657 20.538 4.973 ;
     RECT  21.492 3.629 21.51 5.063 ;
     RECT  2.268 4.973 20.538 5.567 ;
     RECT  0.108 4.109 0.126 5.933 ;
     RECT  2.268 5.567 20.502 6.413 ;
     RECT  21.492 6.667 21.51 6.989 ;
     RECT  0.108 6.817 0.126 7.357 ;
     RECT  0.108 7.357 0.162 7.393 ;
     RECT  2.304 6.413 20.502 7.531 ;
     RECT  2.304 7.531 20.538 8.041 ;
     RECT  0.108 7.393 0.198 8.107 ;
     RECT  2.268 8.041 20.538 8.107 ;
     RECT  2.268 8.107 20.574 8.195 ;
     RECT  0.108 8.107 0.342 8.237 ;
     RECT  2.304 8.195 20.574 8.239 ;
     RECT  2.304 8.239 20.61 8.429 ;
     RECT  21.492 8.203 21.51 8.609 ;
     RECT  0.108 8.237 0.126 8.621 ;
     RECT  2.304 8.429 20.574 9.077 ;
     RECT  1.152 8.491 1.17 9.163 ;
     RECT  1.152 9.163 1.206 9.355 ;
     RECT  2.304 9.077 20.502 9.355 ;
     RECT  1.152 9.355 20.502 9.689 ;
     RECT  0.144 9.691 0.162 9.739 ;
     RECT  19.656 9.689 20.502 9.835 ;
     RECT  0.144 9.739 0.342 9.869 ;
     RECT  19.656 9.835 20.538 10.229 ;
     RECT  19.908 10.229 20.538 10.499 ;
     RECT  1.152 9.689 18.897 10.561 ;
     RECT  0.144 9.869 0.162 10.705 ;
     RECT  0.108 10.705 0.162 10.867 ;
     RECT  0.108 10.867 0.198 10.925 ;
     RECT  1.152 10.561 18.99 10.975 ;
     RECT  1.152 10.975 19.062 11.129 ;
     RECT  0.144 10.925 0.198 11.209 ;
     RECT  1.152 11.129 18.954 11.209 ;
     RECT  19.908 10.499 20.502 11.237 ;
     RECT  0.144 11.209 18.954 11.309 ;
     RECT  21.42 8.683 21.438 11.309 ;
     RECT  0.18 11.309 18.954 11.501 ;
     RECT  0.54 11.501 18.954 11.597 ;
     RECT  1.224 11.597 18.954 12.091 ;
     RECT  20.052 11.237 20.502 12.331 ;
     RECT  1.224 12.091 19.098 12.515 ;
     RECT  19.908 12.331 20.502 12.595 ;
     RECT  1.8 12.515 19.098 12.811 ;
     RECT  19.872 12.595 20.502 12.811 ;
     RECT  0.144 12.619 0.162 12.907 ;
     RECT  1.8 12.811 20.502 13.055 ;
     RECT  0.144 12.907 0.234 13.085 ;
     RECT  21.492 11.371 21.51 13.147 ;
     RECT  21.42 13.147 21.51 13.199 ;
     RECT  21.492 13.199 21.51 13.229 ;
     RECT  0.144 13.085 0.162 13.639 ;
     RECT  0.108 13.639 0.162 13.709 ;
     RECT  2.304 13.055 20.502 13.945 ;
     RECT  2.268 13.945 20.502 14.243 ;
     RECT  0.144 13.709 0.162 14.347 ;
     RECT  0.144 14.347 0.342 14.477 ;
     RECT  0.144 14.477 0.234 14.755 ;
     RECT  2.304 14.243 20.502 14.827 ;
     RECT  0.108 14.755 0.234 14.945 ;
     RECT  0.144 14.945 0.234 14.957 ;
     RECT  21.492 13.981 21.51 15.019 ;
     RECT  2.304 14.827 20.538 15.629 ;
     RECT  0.144 14.957 0.162 15.763 ;
     RECT  0.144 15.763 0.198 15.799 ;
     RECT  21.456 15.019 21.51 15.827 ;
     RECT  21.456 15.827 21.474 16.013 ;
     RECT  0.108 15.799 0.198 16.033 ;
     RECT  2.304 15.629 20.502 16.367 ;
     RECT  2.304 16.367 18.99 16.537 ;
     RECT  2.232 16.537 18.99 16.637 ;
     RECT  0.108 16.033 0.558 16.781 ;
     RECT  2.268 16.637 18.99 16.835 ;
     RECT  0.108 16.781 0.198 16.973 ;
     RECT  0.108 16.973 0.126 17.165 ;
     RECT  19.908 16.367 20.502 17.323 ;
     RECT  19.872 17.323 20.502 17.419 ;
     RECT  19.872 17.419 20.538 17.515 ;
     RECT  2.304 16.835 18.99 17.581 ;
     RECT  2.304 17.581 19.098 17.803 ;
     RECT  19.836 17.515 20.538 17.803 ;
     RECT  2.304 17.803 20.538 18.023 ;
     RECT  0.216 17.923 0.234 18.283 ;
     RECT  21.492 17.077 21.51 18.475 ;
     RECT  0.144 18.283 0.234 18.509 ;
     RECT  21.456 18.475 21.51 18.527 ;
     RECT  2.304 18.023 19.098 18.571 ;
     RECT  19.836 18.023 20.538 18.599 ;
     RECT  2.232 18.571 19.098 18.689 ;
     RECT  2.304 18.689 19.098 18.769 ;
     RECT  19.836 18.599 20.502 18.769 ;
     RECT  21.456 18.527 21.474 19.139 ;
     RECT  0.108 18.769 0.126 19.277 ;
     RECT  2.304 18.769 20.502 19.499 ;
     RECT  2.304 19.499 20.466 19.679 ;
     RECT  2.304 19.679 20.214 19.723 ;
     RECT  21.492 19.921 21.51 20.317 ;
     RECT  21.456 20.317 21.51 20.333 ;
     RECT  1.728 19.723 20.214 20.621 ;
     RECT  0.288 20.587 0.306 20.683 ;
     RECT  0.18 20.683 0.306 20.695 ;
     RECT  21.456 20.333 21.474 20.717 ;
     RECT  0.18 20.695 0.342 20.723 ;
     RECT  0.216 20.723 0.342 20.779 ;
     RECT  0.216 20.779 0.378 21.005 ;
     RECT  20.448 20.731 20.502 21.091 ;
     RECT  0.216 21.005 0.342 21.101 ;
     RECT  1.728 20.621 19.35 21.155 ;
     RECT  2.304 21.155 19.35 21.389 ;
     RECT  20.448 21.091 20.538 21.433 ;
     RECT  0.324 21.101 0.342 21.485 ;
     RECT  21.42 21.115 21.438 21.485 ;
     RECT  19.944 21.433 20.538 22.009 ;
     RECT  0.216 21.835 0.234 22.013 ;
     RECT  2.304 21.389 19.134 22.207 ;
     RECT  0.108 22.207 0.126 22.795 ;
     RECT  0.108 22.795 0.162 22.819 ;
     RECT  2.232 22.207 19.134 22.891 ;
     RECT  19.944 22.009 20.61 22.891 ;
     RECT  21.42 22.843 21.438 22.891 ;
     RECT  0.108 22.819 0.342 23.021 ;
     RECT  2.232 22.891 20.61 23.021 ;
     RECT  2.268 23.021 20.61 23.261 ;
     RECT  2.304 23.261 20.61 23.405 ;
     RECT  0.108 23.021 0.234 23.453 ;
     RECT  2.304 23.405 20.538 23.789 ;
     RECT  2.304 23.789 20.502 24.205 ;
     RECT  2.268 24.205 20.502 24.269 ;
     RECT  21.42 22.891 21.51 24.269 ;
     RECT  2.304 24.269 20.502 24.395 ;
     RECT  0.108 23.453 0.162 24.461 ;
     RECT  2.376 24.395 20.502 24.467 ;
     RECT  0.144 24.461 0.162 24.745 ;
     RECT  21.492 24.269 21.51 24.809 ;
     RECT  20.232 24.467 20.502 25.079 ;
     RECT  0.144 24.745 0.558 25.133 ;
     RECT  2.376 24.467 19.386 25.285 ;
     RECT  2.34 25.285 19.386 25.339 ;
     RECT  2.304 25.339 19.386 25.387 ;
     RECT  2.232 25.387 19.386 25.475 ;
     RECT  20.412 25.079 20.502 25.579 ;
     RECT  2.304 25.475 19.386 25.867 ;
     RECT  20.412 25.579 20.538 25.867 ;
     RECT  2.304 25.867 20.538 26.087 ;
     RECT  0.144 25.133 0.162 26.095 ;
     RECT  2.304 26.087 20.502 26.189 ;
     RECT  0.108 26.095 0.162 26.563 ;
     RECT  0.108 26.563 0.198 26.573 ;
     RECT  21.42 26.443 21.438 26.621 ;
     RECT  19.908 26.189 20.502 26.869 ;
     RECT  0.144 26.573 0.198 27.101 ;
     RECT  2.304 26.189 19.17 27.175 ;
     RECT  19.908 26.869 20.538 27.175 ;
     RECT  0.18 27.101 0.198 27.245 ;
     RECT  2.304 27.175 20.538 27.245 ;
     RECT  2.304 27.245 20.502 27.835 ;
     RECT  2.232 27.835 20.502 27.905 ;
     RECT  2.304 27.905 20.502 28.021 ;
     RECT  0.54 27.679 0.558 28.205 ;
     RECT  2.304 28.021 20.538 28.489 ;
     RECT  2.304 28.489 20.574 28.651 ;
     RECT  2.268 28.651 20.574 28.715 ;
     RECT  2.304 28.715 20.574 28.859 ;
     RECT  19.872 28.859 20.574 29.069 ;
     RECT  21.492 28.267 21.51 29.261 ;
     RECT  0.108 28.453 0.126 29.335 ;
     RECT  2.304 28.859 19.026 29.707 ;
     RECT  2.268 29.707 19.026 29.803 ;
     RECT  19.908 29.069 20.538 29.803 ;
     RECT  0.036 29.335 0.126 29.899 ;
     RECT  2.268 29.803 20.538 29.939 ;
     RECT  21.42 29.899 21.438 30.077 ;
     RECT  0.036 29.899 0.162 30.145 ;
     RECT  2.268 29.939 20.502 30.181 ;
     RECT  2.232 30.181 20.502 30.371 ;
     RECT  0.036 30.145 0.234 30.413 ;
     RECT  0.036 30.413 0.162 30.839 ;
     RECT  2.304 30.371 20.502 31.261 ;
     RECT  0.072 30.839 0.162 31.531 ;
     RECT  21.492 30.763 21.51 31.72 ;
     RECT  0.072 31.531 0.27 31.723 ;
     RECT  1.152 31.225 1.17 31.723 ;
     RECT  2.304 31.261 20.61 32.429 ;
     RECT  2.304 32.429 20.502 33.101 ;
     RECT  0.072 31.723 1.17 33.211 ;
     RECT  2.304 33.101 19.098 33.277 ;
     RECT  0.072 33.211 1.314 33.341 ;
     RECT  21.456 31.72 21.51 33.413 ;
     RECT  0.072 33.341 1.206 33.437 ;
     RECT  2.268 33.277 19.098 33.437 ;
     RECT  21.492 33.413 21.51 33.719 ;
     RECT  0.072 33.437 1.17 33.845 ;
     RECT  0.144 33.845 1.17 33.869 ;
     RECT  2.304 33.437 19.098 33.889 ;
     RECT  19.872 33.101 20.502 33.889 ;
     RECT  0.432 33.869 1.17 34.157 ;
     RECT  2.304 33.889 20.502 34.157 ;
     RECT  1.116 34.157 1.17 34.253 ;
     RECT  1.152 34.253 1.17 34.445 ;
     RECT  0.036 34.735 0.162 34.897 ;
     RECT  0.036 34.897 0.198 34.933 ;
     RECT  2.304 34.157 19.422 34.987 ;
     RECT  1.728 34.987 19.422 35.083 ;
     RECT  20.196 34.157 20.502 35.083 ;
     RECT  1.728 35.083 20.502 35.275 ;
     RECT  0.036 34.933 0.27 35.545 ;
     RECT  1.728 35.275 20.538 35.879 ;
     RECT  2.304 35.879 20.538 36.383 ;
     RECT  21.492 36.043 21.51 36.418 ;
     RECT  21.456 36.418 21.51 36.419 ;
     RECT  21.456 36.419 21.474 36.689 ;
     RECT  19.872 36.383 20.538 36.907 ;
     RECT  19.872 36.907 20.574 37.229 ;
     RECT  2.304 36.383 19.098 37.435 ;
     RECT  19.872 37.229 20.502 37.435 ;
     RECT  2.304 37.435 20.502 37.895 ;
     RECT  2.304 37.895 19.062 38.059 ;
     RECT  1.728 38.059 19.062 38.713 ;
     RECT  19.836 37.895 20.502 38.713 ;
     RECT  1.728 38.713 20.502 38.849 ;
     RECT  1.728 38.849 18.99 39.587 ;
     RECT  0.036 35.545 0.846 39.623 ;
     RECT  0.072 39.623 0.846 39.629 ;
     RECT  19.908 38.849 20.502 39.721 ;
     RECT  2.232 39.587 18.99 39.757 ;
     RECT  0.072 39.629 0.522 39.917 ;
     RECT  21.492 39.091 21.51 40.099 ;
     RECT  21.456 40.099 21.51 40.123 ;
     RECT  21.42 40.123 21.51 40.208 ;
     RECT  2.232 39.757 19.062 40.349 ;
     RECT  2.304 40.349 19.062 40.405 ;
     RECT  19.908 39.721 20.538 40.405 ;
     RECT  2.304 40.405 20.538 40.493 ;
     RECT  2.304 40.493 20.502 40.589 ;
     RECT  21.42 40.208 21.474 40.981 ;
     RECT  21.42 40.981 21.51 41.069 ;
     RECT  0.072 39.917 0.414 41.179 ;
     RECT  0.072 41.179 0.486 41.215 ;
     RECT  21.42 41.069 21.438 41.261 ;
     RECT  20.268 40.589 20.502 41.323 ;
     RECT  2.304 40.589 19.314 41.413 ;
     RECT  20.232 41.323 20.502 41.413 ;
     RECT  2.304 41.413 20.502 41.707 ;
     RECT  0.072 41.215 0.558 41.837 ;
     RECT  2.304 41.707 20.538 41.989 ;
     RECT  2.304 41.989 20.574 42.151 ;
     RECT  2.304 42.151 20.646 42.221 ;
     RECT  19.98 42.221 20.646 42.317 ;
     RECT  2.304 42.221 19.098 42.605 ;
     RECT  20.16 42.317 20.646 42.749 ;
     RECT  20.196 42.749 20.646 42.755 ;
     RECT  2.304 42.605 19.062 43.069 ;
     RECT  0.072 41.837 0.486 43.141 ;
     RECT  20.196 42.755 20.61 43.169 ;
     RECT  1.692 43.069 19.062 43.435 ;
     RECT  20.196 43.169 20.538 43.565 ;
     RECT  1.692 43.435 19.386 43.771 ;
     RECT  20.196 43.565 20.502 43.771 ;
     RECT  1.692 43.771 20.502 43.951 ;
     RECT  0.072 43.141 0.558 44.113 ;
     RECT  1.44 43.951 20.502 44.113 ;
     RECT  0.072 44.113 20.502 44.237 ;
     RECT  0.072 44.237 19.098 44.519 ;
     RECT  0.144 44.519 19.098 44.528 ;
     RECT  0.468 44.528 19.098 44.813 ;
     RECT  1.152 44.813 19.098 45.067 ;
     RECT  19.908 44.237 20.502 45.067 ;
     RECT  21.492 41.803 21.51 45.427 ;
     RECT  1.152 45.067 20.502 45.485 ;
     RECT  19.908 45.485 20.502 45.527 ;
     RECT  0.18 45.535 0.198 45.547 ;
     RECT  1.152 45.485 19.098 45.773 ;
     RECT  19.944 45.527 20.502 45.805 ;
     RECT  21.456 45.427 21.51 45.869 ;
     RECT  0.108 45.547 0.198 45.931 ;
     RECT  0.108 45.931 0.342 46.061 ;
     RECT  19.944 45.805 20.538 46.157 ;
     RECT  20.016 46.157 20.538 46.253 ;
     RECT  0.108 46.061 0.234 46.345 ;
     RECT  2.232 45.773 19.098 46.381 ;
     RECT  20.052 46.253 20.538 46.445 ;
     RECT  2.232 46.381 19.17 46.499 ;
     RECT  2.232 46.499 19.098 46.535 ;
     RECT  1.152 45.773 1.458 46.615 ;
     RECT  2.232 46.535 19.026 46.615 ;
     RECT  0.036 46.345 0.234 46.769 ;
     RECT  0.108 46.769 0.234 46.813 ;
     RECT  1.152 46.615 19.026 46.813 ;
     RECT  0.108 46.813 19.026 46.829 ;
     RECT  21.456 46.849 21.474 46.891 ;
     RECT  20.052 46.445 20.502 46.987 ;
     RECT  19.908 46.987 20.502 47.083 ;
     RECT  1.44 46.829 19.026 47.309 ;
     RECT  21.456 46.891 21.51 47.309 ;
     RECT  21.492 47.309 21.51 47.405 ;
     RECT  1.62 47.309 19.026 47.551 ;
     RECT  19.872 47.083 20.502 47.587 ;
     RECT  19.872 47.587 20.538 47.981 ;
     RECT  19.872 47.981 20.502 48.043 ;
     RECT  0.108 46.829 0.558 48.077 ;
     RECT  1.62 47.551 19.062 48.155 ;
     RECT  1.62 48.155 19.026 48.235 ;
     RECT  21.456 48.361 21.474 48.523 ;
     RECT  0.108 48.077 0.522 48.541 ;
     RECT  19.836 48.043 20.502 48.739 ;
     RECT  21.456 48.523 21.51 48.749 ;
     RECT  1.404 48.235 19.026 48.803 ;
     RECT  21.492 48.749 21.51 48.803 ;
     RECT  0.036 48.541 0.522 48.973 ;
     RECT  1.404 48.803 8.097 48.973 ;
     RECT  19.836 48.739 20.538 49.325 ;
     RECT  8.856 48.803 19.026 49.387 ;
     RECT  19.836 49.325 20.502 49.387 ;
     RECT  0.036 48.973 8.097 49.867 ;
     RECT  8.856 49.387 20.502 49.867 ;
     RECT  0.036 49.867 20.502 50.557 ;
     RECT  0.036 50.557 20.538 50.861 ;
     RECT  21.492 51.781 21.51 52.075 ;
     RECT  21.42 52.075 21.51 52.979 ;
     RECT  21.42 52.979 21.438 53.021 ;
     RECT  0.036 50.861 20.502 53.131 ;
     RECT  0.036 53.131 20.538 54.029 ;
     RECT  0.036 54.029 20.502 54.509 ;
     RECT  0.036 54.509 19.062 54.869 ;
     RECT  0.072 54.869 19.062 54.893 ;
     RECT  1.404 54.893 19.062 55.175 ;
     RECT  21.456 54.949 21.474 55.339 ;
     RECT  1.404 55.175 18.897 55.469 ;
     RECT  19.944 54.509 20.502 55.531 ;
     RECT  21.456 55.339 21.51 56.093 ;
     RECT  21.456 56.093 21.474 56.141 ;
     RECT  1.476 55.469 18.897 56.299 ;
     RECT  19.908 55.531 20.502 56.299 ;
     RECT  1.476 56.299 20.502 56.399 ;
     RECT  1.476 56.399 19.098 57.101 ;
     RECT  1.548 57.101 19.098 57.485 ;
     RECT  2.268 57.485 19.098 57.541 ;
     RECT  19.836 56.399 20.502 57.541 ;
     RECT  0.072 54.893 0.558 57.641 ;
     RECT  2.268 57.541 20.502 58.217 ;
     RECT  21.42 58.036 21.438 58.219 ;
     RECT  21.42 58.219 21.51 58.349 ;
     RECT  2.304 58.217 20.502 58.351 ;
     RECT  2.304 58.351 20.574 58.387 ;
     RECT  0.144 57.641 0.558 58.495 ;
     RECT  0.072 58.495 0.558 58.507 ;
     RECT  21.42 58.349 21.438 58.541 ;
     RECT  0.072 58.507 0.63 58.637 ;
     RECT  2.304 58.387 20.646 58.925 ;
     RECT  2.304 58.925 20.61 59.213 ;
     RECT  2.304 59.213 20.574 59.729 ;
     RECT  9.072 59.729 20.574 59.789 ;
     RECT  0.072 58.637 0.558 60.115 ;
     RECT  21.492 60.043 21.51 60.151 ;
     RECT  19.944 59.789 20.574 60.365 ;
     RECT  21.42 60.151 21.51 60.461 ;
     RECT  2.304 59.729 8.19 60.511 ;
     RECT  9.072 59.789 18.954 60.511 ;
     RECT  21.42 60.461 21.474 60.557 ;
     RECT  9.072 60.511 18.99 60.655 ;
     RECT  2.304 60.511 8.298 60.691 ;
     RECT  9.072 60.655 19.098 60.691 ;
     RECT  19.944 60.365 20.538 60.749 ;
     RECT  21.42 60.557 21.438 60.817 ;
     RECT  19.944 60.749 20.502 61.037 ;
     RECT  2.304 60.691 19.098 61.159 ;
     RECT  2.304 61.159 19.422 61.349 ;
     RECT  0.072 60.115 0.594 61.385 ;
     RECT  2.304 61.349 9.306 61.387 ;
     RECT  21.348 60.817 21.438 61.579 ;
     RECT  21.348 61.579 21.51 61.619 ;
     RECT  21.348 61.619 21.438 61.661 ;
     RECT  21.348 61.661 21.366 61.709 ;
     RECT  2.268 61.387 9.306 61.763 ;
     RECT  10.224 61.349 19.422 61.763 ;
     RECT  12.312 61.763 19.422 61.765 ;
     RECT  20.196 61.037 20.502 61.765 ;
     RECT  2.268 61.763 9.234 61.771 ;
     RECT  10.224 61.763 11.538 61.889 ;
     RECT  10.515 61.889 11.538 61.925 ;
     RECT  12.312 61.765 20.502 61.925 ;
     RECT  12.312 61.925 12.33 61.961 ;
     RECT  11.52 61.925 11.538 62.069 ;
     RECT  1.656 61.771 9.234 62.159 ;
     RECT  13.215 61.925 20.502 62.189 ;
     RECT  9.216 62.159 9.234 62.195 ;
     RECT  13.215 62.189 19.386 62.303 ;
     RECT  20.484 62.189 20.502 62.311 ;
     RECT  18.216 62.303 19.386 62.381 ;
     RECT  10.515 61.925 10.797 62.387 ;
     RECT  1.656 62.159 8.154 62.429 ;
     RECT  13.215 62.303 17.442 62.429 ;
     RECT  18.216 62.381 19.062 62.429 ;
     RECT  20.484 62.311 20.538 62.429 ;
     RECT  13.215 62.429 13.878 62.465 ;
     RECT  14.616 62.429 17.442 62.465 ;
     RECT  1.656 62.429 6.894 62.501 ;
     RECT  14.76 62.465 17.442 62.501 ;
     RECT  15.66 62.501 17.442 62.525 ;
     RECT  6.876 62.501 6.894 62.537 ;
     RECT  16.92 62.525 17.442 62.537 ;
     RECT  0.108 61.385 0.594 62.539 ;
     RECT  1.656 62.501 5.67 62.573 ;
     RECT  15.66 62.525 16.005 62.573 ;
     RECT  18.288 62.429 19.062 62.573 ;
     RECT  7.632 62.429 7.905 62.609 ;
     RECT  17.424 62.537 17.442 62.609 ;
     RECT  18.288 62.573 18.774 62.609 ;
     RECT  5.115 62.573 5.67 62.657 ;
     RECT  7.815 62.609 7.905 62.657 ;
     RECT  10.515 62.387 10.605 62.657 ;
     RECT  13.215 62.465 13.305 62.657 ;
     RECT  15.915 62.573 16.005 62.657 ;
     RECT  18.615 62.609 18.774 62.657 ;
     RECT  0.108 62.539 0.666 62.669 ;
     RECT  21.42 62.491 21.438 62.669 ;
     RECT  5.652 62.657 5.67 62.699 ;
     RECT  18.756 62.657 18.774 62.765 ;
     RECT  1.656 62.573 4.158 62.861 ;
     RECT  20.52 62.429 20.538 62.861 ;
     RECT  0.108 62.669 0.594 62.957 ;
     RECT  0.288 62.957 0.594 63.149 ;
     RECT  1.656 62.861 3.402 63.245 ;
     RECT  1.656 63.245 1.71 63.341 ;
     RECT  1.656 63.341 1.674 63.437 ;
     RECT  2.664 63.245 3.402 63.533 ;
     RECT  2.664 63.533 3.006 63.629 ;
     RECT  2.664 63.629 2.934 63.725 ;
     RECT  0.288 63.149 0.306 63.821 ;
     RECT  4.14 62.861 4.158 63.917 ;
     RECT  2.916 63.725 2.934 64.013 ;
    LAYER M4 ;
     RECT  0.06 1.872 2.333 64.008 ;
     RECT  2.333 1.968 2.704 64.008 ;
     RECT  2.704 1.968 2.765 5.544 ;
     RECT  2.704 8.784 2.765 9.288 ;
     RECT  2.704 10.32 2.765 64.008 ;
     RECT  2.765 1.968 2.837 4.68 ;
     RECT  2.837 1.968 2.873 3.912 ;
     RECT  2.765 8.928 2.873 9.288 ;
     RECT  2.765 60.24 2.945 64.008 ;
     RECT  2.765 10.32 2.981 59.256 ;
     RECT  2.981 10.608 3.125 59.256 ;
     RECT  2.873 8.928 3.233 9.24 ;
     RECT  3.125 19.872 3.305 59.256 ;
     RECT  3.305 19.92 3.395 59.256 ;
     RECT  3.395 19.92 3.413 50.184 ;
     RECT  2.945 60.24 3.413 63.912 ;
     RECT  3.413 20.832 3.557 50.184 ;
     RECT  3.413 60.24 3.629 62.856 ;
     RECT  3.629 60.24 3.635 62.76 ;
     RECT  3.395 51.216 3.731 59.256 ;
     RECT  3.731 56.832 3.737 59.256 ;
     RECT  2.704 6.816 3.769 6.84 ;
     RECT  3.769 6.576 3.805 6.84 ;
     RECT  3.737 58.464 3.881 59.256 ;
     RECT  3.233 8.976 3.923 9.24 ;
     RECT  3.557 40.176 3.953 50.184 ;
     RECT  3.635 60.576 3.953 62.76 ;
     RECT  3.805 6.24 4.019 6.84 ;
     RECT  2.873 1.968 4.165 3.864 ;
     RECT  3.413 63.888 4.169 63.912 ;
     RECT  4.019 6.24 4.172 6.6 ;
     RECT  4.165 1.968 4.213 3.912 ;
     RECT  4.213 1.968 4.385 3.96 ;
     RECT  3.877 7.824 4.417 7.848 ;
     RECT  3.125 10.608 4.417 18.792 ;
     RECT  3.557 20.832 4.669 38.952 ;
     RECT  3.953 40.176 4.669 50.088 ;
     RECT  4.417 7.824 4.705 8.568 ;
     RECT  4.417 9.552 4.741 18.792 ;
     RECT  4.669 20.832 4.741 50.088 ;
     RECT  4.385 2.148 4.777 3.96 ;
     RECT  3.731 51.216 4.921 55.368 ;
     RECT  3.737 56.832 4.921 57.144 ;
     RECT  4.172 5.712 5.029 6.6 ;
     RECT  4.921 51.216 5.065 57.144 ;
     RECT  4.777 2.148 5.108 4.728 ;
     RECT  5.029 5.712 5.108 6.696 ;
     RECT  4.705 7.728 5.108 8.568 ;
     RECT  4.741 9.552 5.108 50.088 ;
     RECT  5.065 51.12 5.108 57.144 ;
     RECT  3.881 58.464 5.108 59.208 ;
     RECT  3.953 60.576 5.108 62.136 ;
     RECT  5.108 2.148 5.212 62.652 ;
     RECT  5.212 2.418 5.404 62.382 ;
     RECT  5.404 2.496 5.555 10.344 ;
     RECT  5.404 51.12 5.555 54.6 ;
     RECT  5.404 48.432 5.573 50.088 ;
     RECT  5.573 48.48 5.645 50.088 ;
     RECT  5.404 18.192 5.699 24.504 ;
     RECT  5.555 5.76 5.717 10.344 ;
     RECT  5.404 60 5.717 60.6 ;
     RECT  5.555 2.496 5.753 4.728 ;
     RECT  5.699 18.432 5.753 24.504 ;
     RECT  5.404 33.936 5.753 39.24 ;
     RECT  5.555 51.216 5.843 54.6 ;
     RECT  5.753 2.592 5.861 4.728 ;
     RECT  5.717 60.576 5.861 60.6 ;
     RECT  5.404 40.56 6.005 42.072 ;
     RECT  5.404 56.016 6.041 58.824 ;
     RECT  5.717 8.976 6.185 10.344 ;
     RECT  5.753 20.304 6.293 24.504 ;
     RECT  5.717 5.76 6.329 7.992 ;
     RECT  6.329 6.624 6.365 7.992 ;
     RECT  6.005 40.608 6.433 42.072 ;
     RECT  5.404 43.344 6.433 47.256 ;
     RECT  5.404 11.424 6.545 17.16 ;
     RECT  5.404 29.568 6.649 32.76 ;
     RECT  5.843 51.264 6.721 54.6 ;
     RECT  6.041 56.016 6.721 58.68 ;
     RECT  6.433 40.608 6.755 47.256 ;
     RECT  6.649 29.52 6.757 32.76 ;
     RECT  6.545 11.424 6.761 15.576 ;
     RECT  5.861 2.736 6.829 4.728 ;
     RECT  6.545 16.56 6.865 17.16 ;
     RECT  5.753 18.432 6.865 19.32 ;
     RECT  6.757 29.52 6.865 32.904 ;
     RECT  5.404 25.728 6.901 28.488 ;
     RECT  6.865 29.52 6.901 33.096 ;
     RECT  5.645 48.672 6.901 50.088 ;
     RECT  6.721 51.264 6.901 58.68 ;
     RECT  6.185 10.224 7.009 10.344 ;
     RECT  6.761 11.424 7.009 15.528 ;
     RECT  6.185 8.976 7.189 9.048 ;
     RECT  7.009 10.224 7.189 15.528 ;
     RECT  6.755 40.608 7.225 47.16 ;
     RECT  6.901 25.728 7.429 33.096 ;
     RECT  5.753 34.176 7.429 39.24 ;
     RECT  6.829 2.736 7.585 5.64 ;
     RECT  6.901 48.672 7.729 58.68 ;
     RECT  7.585 2.304 7.808 5.64 ;
     RECT  6.365 6.624 7.808 7.8 ;
     RECT  7.189 8.976 7.808 15.528 ;
     RECT  6.865 16.56 7.808 19.32 ;
     RECT  6.293 20.304 7.808 24.408 ;
     RECT  7.429 25.728 7.808 39.24 ;
     RECT  7.225 40.368 7.808 47.16 ;
     RECT  7.729 48.48 7.808 58.68 ;
     RECT  7.477 60.576 7.808 60.6 ;
     RECT  5.404 61.68 7.808 61.704 ;
     RECT  7.808 2.148 7.912 62.652 ;
     RECT  7.912 2.304 8.104 62.382 ;
     RECT  8.104 7.344 8.165 11.448 ;
     RECT  8.104 29.568 8.201 33.384 ;
     RECT  8.104 12.48 8.237 25.032 ;
     RECT  8.104 2.304 8.243 6.12 ;
     RECT  8.165 7.344 8.243 8.568 ;
     RECT  8.104 59.664 8.309 61.752 ;
     RECT  8.243 2.304 8.453 5.592 ;
     RECT  8.104 50.928 8.525 58.68 ;
     RECT  8.309 60.816 8.531 61.752 ;
     RECT  8.309 59.664 8.572 59.688 ;
     RECT  8.104 34.704 8.579 43.128 ;
     RECT  8.525 51.408 8.597 58.68 ;
     RECT  8.531 61.008 8.597 61.752 ;
     RECT  8.579 34.704 8.819 38.76 ;
     RECT  8.819 34.704 8.849 38.712 ;
     RECT  8.579 39.888 8.857 43.128 ;
     RECT  8.237 14.352 8.963 25.032 ;
     RECT  8.165 9.792 9.205 11.448 ;
     RECT  8.201 29.568 9.241 33.096 ;
     RECT  8.963 14.352 9.299 19.56 ;
     RECT  9.241 29.28 9.313 33.096 ;
     RECT  8.104 47.04 9.313 49.896 ;
     RECT  8.857 40.032 9.349 43.128 ;
     RECT  8.104 44.16 9.349 46.056 ;
     RECT  8.453 4.128 9.493 5.592 ;
     RECT  9.493 4.128 9.529 6.024 ;
     RECT  8.243 7.344 9.529 7.8 ;
     RECT  9.313 47.04 9.541 49.992 ;
     RECT  8.597 51.408 9.565 58.488 ;
     RECT  9.529 59.616 9.565 59.64 ;
     RECT  8.104 26.112 9.637 27.624 ;
     RECT  9.313 28.944 9.637 33.096 ;
     RECT  9.565 51.408 9.637 59.64 ;
     RECT  8.597 61.008 9.637 61.032 ;
     RECT  9.205 9.792 9.685 11.496 ;
     RECT  9.349 40.032 9.853 46.056 ;
     RECT  9.541 47.04 9.853 50.136 ;
     RECT  9.853 40.032 9.889 50.136 ;
     RECT  9.637 51.408 9.889 61.032 ;
     RECT  8.237 12.48 9.925 13.368 ;
     RECT  9.299 14.352 9.925 14.76 ;
     RECT  8.963 20.592 9.961 25.032 ;
     RECT  8.849 34.704 9.98 38.472 ;
     RECT  9.98 34.128 10.316 38.472 ;
     RECT  8.453 2.304 10.429 2.856 ;
     RECT  10.429 2.016 10.465 2.856 ;
     RECT  9.685 9.072 10.465 11.496 ;
     RECT  9.925 12.48 10.465 14.76 ;
     RECT  9.961 20.592 10.501 25.128 ;
     RECT  9.637 26.112 10.501 33.096 ;
     RECT  10.465 2.016 10.508 2.904 ;
     RECT  9.529 4.128 10.508 6.264 ;
     RECT  9.529 7.344 10.508 7.944 ;
     RECT  10.465 9.072 10.508 14.76 ;
     RECT  9.299 15.984 10.508 19.56 ;
     RECT  10.501 20.592 10.508 33.096 ;
     RECT  10.316 34.08 10.508 38.472 ;
     RECT  9.889 40.032 10.508 61.032 ;
     RECT  10.508 2.016 10.612 62.652 ;
     RECT  10.309 0.096 10.739 0.12 ;
     RECT  10.612 2.016 10.804 62.382 ;
     RECT  10.804 2.016 10.835 10.296 ;
     RECT  10.804 46.032 10.865 59.304 ;
     RECT  10.804 60.288 10.865 60.312 ;
     RECT  10.865 46.032 11.045 59.016 ;
     RECT  10.835 2.256 11.219 10.296 ;
     RECT  10.804 25.776 11.225 31.416 ;
     RECT  10.804 34.704 11.333 38.472 ;
     RECT  11.225 28.176 11.405 31.416 ;
     RECT  11.045 46.032 11.513 57.144 ;
     RECT  11.219 2.256 11.549 9.672 ;
     RECT  10.804 11.664 11.693 24.648 ;
     RECT  11.225 25.776 11.693 27.192 ;
     RECT  10.804 39.936 11.797 42.216 ;
     RECT  10.804 43.344 11.797 44.76 ;
     RECT  11.333 36.528 11.941 38.472 ;
     RECT  10.804 32.544 11.989 33.624 ;
     RECT  11.333 34.704 11.989 34.776 ;
     RECT  11.941 36.528 11.989 38.76 ;
     RECT  11.797 39.936 11.989 44.76 ;
     RECT  11.693 22.752 12.013 24.648 ;
     RECT  11.693 25.776 12.013 27.096 ;
     RECT  11.549 2.304 12.017 9.672 ;
     RECT  11.045 58.464 12.017 59.016 ;
     RECT  12.017 58.464 12.049 58.488 ;
     RECT  11.513 50.64 12.092 57.144 ;
     RECT  12.049 58.176 12.092 58.488 ;
     RECT  12.013 22.752 12.097 27.096 ;
     RECT  11.693 11.664 12.157 21.528 ;
     RECT  11.405 28.224 12.409 31.416 ;
     RECT  11.989 32.544 12.409 34.776 ;
     RECT  12.409 28.224 12.428 34.776 ;
     RECT  11.989 36.528 12.437 44.76 ;
     RECT  12.157 11.136 12.661 21.528 ;
     RECT  12.097 22.752 12.661 24.744 ;
     RECT  12.437 36.48 12.769 44.76 ;
     RECT  12.769 36.48 12.841 44.952 ;
     RECT  12.428 28.224 12.877 34.968 ;
     RECT  11.513 46.032 12.877 49.512 ;
     RECT  12.092 50.64 12.877 58.488 ;
     RECT  12.017 2.352 12.949 9.672 ;
     RECT  12.661 10.944 12.949 24.744 ;
     RECT  11.833 60.432 12.949 60.456 ;
     RECT  10.804 61.584 12.949 61.608 ;
     RECT  12.841 36.48 13.093 45 ;
     RECT  12.877 46.032 13.093 58.488 ;
     RECT  12.949 2.352 13.208 24.744 ;
     RECT  12.097 25.872 13.208 27.096 ;
     RECT  12.877 28.224 13.208 35.448 ;
     RECT  13.093 36.48 13.208 58.488 ;
     RECT  12.949 60.432 13.208 61.608 ;
     RECT  13.208 2.148 13.312 62.652 ;
     RECT  13.312 2.418 13.504 62.382 ;
     RECT  13.504 25.968 14.105 59.736 ;
     RECT  13.504 2.496 14.321 24.648 ;
     RECT  14.321 10.08 14.393 24.648 ;
     RECT  14.105 28.32 14.393 59.736 ;
     RECT  13.504 60.912 14.393 61.944 ;
     RECT  14.393 30.912 14.429 43.752 ;
     RECT  14.393 17.328 14.537 24.648 ;
     RECT  14.105 25.968 14.605 27.24 ;
     RECT  14.393 60.912 14.677 61.368 ;
     RECT  14.537 18.48 14.681 24.648 ;
     RECT  14.537 17.328 14.717 17.352 ;
     RECT  14.681 18.528 14.753 24.648 ;
     RECT  14.429 34.464 14.861 43.752 ;
     RECT  14.393 45.312 14.861 59.736 ;
     RECT  14.393 10.08 14.897 16.344 ;
     RECT  14.861 54.48 14.897 59.736 ;
     RECT  14.753 23.664 14.933 24.648 ;
     RECT  14.861 34.944 14.933 43.752 ;
     RECT  14.897 54.528 15.073 59.736 ;
     RECT  14.677 60.72 15.073 61.368 ;
     RECT  14.605 25.872 15.325 27.24 ;
     RECT  14.393 28.32 15.325 29.832 ;
     RECT  14.933 23.808 15.793 24.648 ;
     RECT  15.325 25.872 15.793 29.832 ;
     RECT  14.321 2.496 15.829 9 ;
     RECT  14.897 10.08 15.829 15.528 ;
     RECT  14.861 45.312 15.829 46.776 ;
     RECT  14.861 47.856 15.829 53.496 ;
     RECT  15.829 2.496 15.908 15.528 ;
     RECT  14.753 18.528 15.908 22.632 ;
     RECT  15.793 23.808 15.908 29.832 ;
     RECT  14.429 30.912 15.908 33.432 ;
     RECT  14.933 34.992 15.908 43.752 ;
     RECT  15.829 45.312 15.908 53.496 ;
     RECT  15.073 54.528 15.908 61.368 ;
     RECT  15.908 2.148 16.012 62.652 ;
     RECT  16.012 2.418 16.204 62.52 ;
     RECT  16.204 20.592 16.409 31.8 ;
     RECT  16.204 55.152 16.553 57.624 ;
     RECT  16.204 34.128 16.625 34.152 ;
     RECT  16.204 45.456 16.841 50.088 ;
     RECT  16.409 29.808 16.985 31.8 ;
     RECT  16.553 57.6 16.985 57.624 ;
     RECT  16.204 51.216 17.021 54.072 ;
     RECT  16.409 20.592 17.129 28.584 ;
     RECT  16.204 35.424 17.129 43.272 ;
     RECT  17.129 35.424 17.197 40.344 ;
     RECT  16.841 45.456 17.233 49.512 ;
     RECT  16.553 55.152 17.381 56.28 ;
     RECT  17.129 41.664 17.485 43.272 ;
     RECT  17.197 34.944 17.593 40.344 ;
     RECT  17.021 51.312 17.593 54.072 ;
     RECT  17.233 44.592 17.597 49.512 ;
     RECT  16.985 29.808 18.025 31.704 ;
     RECT  17.917 33.024 18.025 33.048 ;
     RECT  17.593 34.752 18.025 40.344 ;
     RECT  16.204 18.288 18.061 18.696 ;
     RECT  17.269 1.392 18.097 1.416 ;
     RECT  16.204 2.448 18.097 17.064 ;
     RECT  16.204 58.656 18.205 62.52 ;
     RECT  17.597 45.12 18.493 49.512 ;
     RECT  17.593 51.312 18.493 54.12 ;
     RECT  18.097 1.392 18.608 17.064 ;
     RECT  18.061 18.288 18.608 18.792 ;
     RECT  17.129 20.592 18.608 28.008 ;
     RECT  18.025 29.808 18.608 33.048 ;
     RECT  18.025 34.128 18.608 40.344 ;
     RECT  17.485 41.664 18.608 43.32 ;
     RECT  18.493 45.12 18.608 54.12 ;
     RECT  17.381 55.152 18.608 56.04 ;
     RECT  18.205 58.224 18.608 62.52 ;
     RECT  18.608 1.392 18.745 62.652 ;
     RECT  18.745 1.392 18.904 62.76 ;
     RECT  18.904 11.952 18.929 16.296 ;
     RECT  18.904 1.392 19.001 10.44 ;
     RECT  19.001 1.392 19.357 7.752 ;
     RECT  19.001 8.88 19.897 10.44 ;
     RECT  18.929 12.624 19.897 16.296 ;
     RECT  18.904 17.328 19.897 18.744 ;
     RECT  18.904 20.016 19.897 29.064 ;
     RECT  18.904 30.048 19.897 37.992 ;
     RECT  18.904 39.504 19.897 54.504 ;
     RECT  18.904 56.304 19.897 62.76 ;
     RECT  19.897 20.016 19.933 37.992 ;
     RECT  19.897 39.408 19.933 54.504 ;
     RECT  19.897 55.536 19.933 62.76 ;
     RECT  19.357 0.72 19.969 7.752 ;
     RECT  19.897 8.88 19.969 11.112 ;
     RECT  19.969 0.72 20.041 11.112 ;
     RECT  19.897 12.336 20.041 18.888 ;
     RECT  20.041 0.72 20.257 18.888 ;
     RECT  19.933 19.92 20.257 37.992 ;
     RECT  20.257 0.72 20.401 37.992 ;
     RECT  20.401 0.72 20.437 38.184 ;
     RECT  19.933 39.408 20.437 62.76 ;
     RECT  20.437 0.72 20.509 62.76 ;
     RECT  20.509 0.72 21.564 62.856 ;
    LAYER M5 ;
     RECT  10.704 0.016 10.824 0.085 ;
     RECT  10.32 0.085 10.824 2.051 ;
     RECT  2.4 2.137 2.52 2.151 ;
     RECT  5.1 2.137 5.22 2.151 ;
     RECT  7.8 2.137 7.92 2.151 ;
     RECT  13.2 2.137 13.32 2.151 ;
     RECT  15.9 2.137 16.02 2.151 ;
     RECT  18.6 2.137 18.72 2.151 ;
     RECT  0.144 2.005 0.168 2.867 ;
     RECT  7.8 2.151 8.112 2.869 ;
     RECT  5.1 2.151 5.412 3.301 ;
     RECT  6.864 2.869 8.112 3.301 ;
     RECT  5.1 3.301 8.112 3.443 ;
     RECT  21.408 3.589 21.432 3.779 ;
     RECT  5.1 3.443 6.024 3.925 ;
     RECT  13.2 2.151 13.512 5.221 ;
     RECT  13.104 5.221 13.512 5.603 ;
     RECT  4.224 3.925 6.024 5.747 ;
     RECT  7.056 3.443 8.112 6.085 ;
     RECT  7.056 6.085 8.232 6.755 ;
     RECT  5.1 5.747 6.024 6.805 ;
     RECT  10.32 2.051 10.812 7.765 ;
     RECT  3.984 6.805 4.008 7.813 ;
     RECT  3.888 7.813 4.008 7.859 ;
     RECT  13.2 5.603 13.512 7.909 ;
     RECT  7.8 6.755 8.232 8.579 ;
     RECT  5.1 6.805 6.216 9.013 ;
     RECT  9.84 7.765 10.812 9.061 ;
     RECT  3.888 7.859 3.912 9.251 ;
     RECT  5.1 9.013 6.696 9.253 ;
     RECT  7.8 8.579 8.112 9.253 ;
     RECT  9.696 9.061 10.812 9.589 ;
     RECT  0.24 9.541 0.264 10.021 ;
     RECT  5.1 9.253 8.112 10.259 ;
     RECT  9.696 9.589 11.208 10.307 ;
     RECT  0.24 10.021 0.312 10.789 ;
     RECT  13.104 7.909 13.512 10.883 ;
     RECT  2.4 2.151 2.712 11.221 ;
     RECT  2.304 11.221 2.712 11.365 ;
     RECT  3.792 10.597 3.816 11.365 ;
     RECT  13.2 10.883 13.512 11.365 ;
     RECT  5.1 10.259 6.216 11.459 ;
     RECT  0.144 10.789 0.312 11.507 ;
     RECT  2.304 11.365 3.816 11.555 ;
     RECT  5.1 11.459 6.024 11.941 ;
     RECT  0.144 11.507 0.264 12.035 ;
     RECT  9.696 10.307 10.812 12.229 ;
     RECT  0.144 12.035 0.216 12.563 ;
     RECT  9.696 12.229 11.496 12.853 ;
     RECT  13.2 11.365 13.8 12.949 ;
     RECT  13.2 12.949 13.944 13.093 ;
     RECT  9.264 12.853 11.496 13.669 ;
     RECT  2.304 11.555 3.048 13.715 ;
     RECT  7.488 10.259 8.112 13.811 ;
     RECT  2.304 13.715 2.856 13.907 ;
     RECT  0.144 12.563 0.168 14.005 ;
     RECT  0.144 14.005 0.408 14.195 ;
     RECT  13.2 13.093 13.992 14.195 ;
     RECT  2.4 13.907 2.856 14.773 ;
     RECT  4.176 11.941 6.024 14.773 ;
     RECT  7.8 13.811 8.112 14.773 ;
     RECT  9.264 13.669 11.784 14.773 ;
     RECT  0.192 14.195 0.408 14.915 ;
     RECT  7.8 14.773 11.784 14.915 ;
     RECT  0.336 14.915 0.408 14.963 ;
     RECT  13.2 14.195 13.944 14.963 ;
     RECT  2.4 14.773 6.024 15.397 ;
     RECT  7.8 14.915 10.812 15.397 ;
     RECT  2.4 15.397 10.812 15.491 ;
     RECT  0.336 14.963 0.36 15.827 ;
     RECT  4.176 15.491 10.812 16.019 ;
     RECT  4.176 16.019 8.112 16.067 ;
     RECT  13.2 14.963 13.704 16.069 ;
     RECT  12.24 16.069 13.704 16.357 ;
     RECT  2.4 15.491 2.856 16.595 ;
     RECT  0.144 16.597 0.168 16.789 ;
     RECT  5.1 16.067 8.112 17.075 ;
     RECT  0.144 16.789 0.216 17.077 ;
     RECT  4.08 16.549 4.104 17.077 ;
     RECT  12 16.357 13.704 17.125 ;
     RECT  0.144 17.077 0.264 17.557 ;
     RECT  10.32 16.019 10.812 17.605 ;
     RECT  12 17.125 14.232 17.605 ;
     RECT  0.144 17.557 0.552 17.747 ;
     RECT  3.936 17.077 4.104 18.181 ;
     RECT  5.1 17.075 6.024 18.181 ;
     RECT  0.144 17.747 0.312 18.419 ;
     RECT  3.936 18.181 6.024 18.467 ;
     RECT  10.32 17.605 14.232 18.563 ;
     RECT  12 18.563 14.232 18.659 ;
     RECT  12.24 18.659 14.232 18.709 ;
     RECT  4.032 18.467 6.024 18.803 ;
     RECT  4.752 18.803 6.024 19.139 ;
     RECT  4.992 19.139 6.024 19.285 ;
     RECT  7.68 17.075 8.112 19.285 ;
     RECT  9.264 16.019 9.288 19.285 ;
     RECT  10.32 18.563 10.812 19.285 ;
     RECT  12.24 18.709 14.376 19.381 ;
     RECT  0.144 18.419 0.264 19.427 ;
     RECT  9.264 19.285 10.812 19.571 ;
     RECT  0.192 19.427 0.264 19.619 ;
     RECT  12.24 19.381 14.808 19.619 ;
     RECT  4.992 19.285 8.112 19.621 ;
     RECT  9.264 19.571 9.288 19.621 ;
     RECT  0.24 19.619 0.264 19.861 ;
     RECT  12.24 19.619 13.512 19.861 ;
     RECT  2.4 16.595 2.712 19.909 ;
     RECT  4.992 19.621 9.288 20.003 ;
     RECT  0.24 19.861 0.36 20.101 ;
     RECT  11.952 19.861 13.512 20.147 ;
     RECT  0.24 20.101 0.408 20.629 ;
     RECT  0.144 20.629 0.408 20.773 ;
     RECT  5.1 20.003 9.288 20.869 ;
     RECT  10.32 19.571 10.812 20.869 ;
     RECT  2.4 19.909 3.24 21.013 ;
     RECT  0.144 20.773 0.552 21.059 ;
     RECT  5.1 20.869 10.812 21.349 ;
     RECT  11.952 20.147 11.976 21.349 ;
     RECT  5.1 21.349 11.976 21.395 ;
     RECT  0.144 21.059 0.36 21.731 ;
     RECT  2.4 21.013 3.336 22.019 ;
     RECT  0.192 21.731 0.36 22.117 ;
     RECT  5.1 21.395 11.688 22.165 ;
     RECT  0.192 22.117 0.408 22.307 ;
     RECT  4.224 22.165 11.688 22.307 ;
     RECT  0.192 22.307 0.36 22.981 ;
     RECT  2.4 22.019 3.24 23.269 ;
     RECT  4.224 22.307 6.024 23.269 ;
     RECT  7.8 22.307 11.688 23.317 ;
     RECT  7.8 23.317 12.072 23.411 ;
     RECT  14.64 19.619 14.664 23.411 ;
     RECT  0.144 22.981 0.36 23.413 ;
     RECT  0.144 23.413 0.408 23.555 ;
     RECT  2.4 23.269 6.024 23.557 ;
     RECT  0.24 23.555 0.408 23.653 ;
     RECT  0.24 23.653 0.456 24.131 ;
     RECT  12.048 23.411 12.072 25.139 ;
     RECT  0.24 24.131 0.408 25.283 ;
     RECT  0.24 25.283 0.264 25.285 ;
     RECT  0.192 25.285 0.264 25.763 ;
     RECT  2.4 23.557 6.792 25.859 ;
     RECT  0.24 25.763 0.264 26.291 ;
     RECT  15.9 2.151 16.212 26.389 ;
     RECT  15.312 26.389 16.212 26.531 ;
     RECT  13.2 20.147 13.512 26.917 ;
     RECT  0.288 26.629 0.312 27.445 ;
     RECT  13.2 26.917 13.656 27.733 ;
     RECT  0.144 27.445 0.312 27.829 ;
     RECT  0.144 27.829 0.552 28.115 ;
     RECT  0.144 28.115 0.408 29.123 ;
     RECT  15.9 26.531 16.212 29.605 ;
     RECT  0.192 29.123 0.408 29.989 ;
     RECT  2.4 25.859 3.96 30.179 ;
     RECT  0.192 29.989 0.552 30.419 ;
     RECT  0.192 30.419 0.408 30.613 ;
     RECT  13.2 27.733 13.8 30.851 ;
     RECT  2.4 30.179 3.624 30.947 ;
     RECT  0.144 30.613 0.408 31.621 ;
     RECT  15.168 29.605 16.212 31.621 ;
     RECT  0.144 31.621 0.456 31.717 ;
     RECT  5.1 25.859 6.792 31.955 ;
     RECT  7.8 23.411 10.812 31.955 ;
     RECT  0.144 31.717 0.504 32.149 ;
     RECT  15.024 31.621 16.212 32.195 ;
     RECT  0.144 32.149 0.6 32.197 ;
     RECT  2.4 30.947 3.192 32.437 ;
     RECT  7.8 31.955 9.384 32.869 ;
     RECT  0.144 32.197 0.696 32.915 ;
     RECT  0.144 32.915 0.552 33.347 ;
     RECT  7.44 32.869 9.384 33.395 ;
     RECT  0.144 33.347 0.456 33.779 ;
     RECT  0.144 33.779 0.312 33.923 ;
     RECT  10.5 31.955 10.812 34.069 ;
     RECT  7.68 33.395 9.384 34.117 ;
     RECT  10.368 34.069 10.812 34.117 ;
     RECT  5.1 31.955 6.024 34.165 ;
     RECT  7.68 34.117 10.812 34.211 ;
     RECT  12 33.301 12.024 34.259 ;
     RECT  2.4 32.437 3.96 34.499 ;
     RECT  13.2 30.851 13.656 34.933 ;
     RECT  2.4 34.499 3.768 34.981 ;
     RECT  2.304 34.981 3.768 35.219 ;
     RECT  5.1 34.165 6.6 35.363 ;
     RECT  0.288 33.923 0.312 35.413 ;
     RECT  0.144 35.413 0.312 36.325 ;
     RECT  12.48 34.933 13.656 36.515 ;
     RECT  0.144 36.325 0.552 36.611 ;
     RECT  2.304 35.219 3.336 37.141 ;
     RECT  5.1 35.363 6.024 37.141 ;
     RECT  2.304 37.141 3.816 37.187 ;
     RECT  7.8 34.211 10.812 37.427 ;
     RECT  5.1 37.141 6.792 37.475 ;
     RECT  0.144 36.611 0.264 37.573 ;
     RECT  13.2 36.515 13.656 37.669 ;
     RECT  18.6 2.151 18.912 37.669 ;
     RECT  0.144 37.573 0.36 37.763 ;
     RECT  13.056 37.669 13.656 37.811 ;
     RECT  18.6 37.669 19.32 37.811 ;
     RECT  15.168 32.195 16.212 38.339 ;
     RECT  2.4 37.187 3.816 38.389 ;
     RECT  5.1 37.475 6.312 38.435 ;
     RECT  13.2 37.811 13.656 38.677 ;
     RECT  0.144 37.763 0.264 38.725 ;
     RECT  2.4 38.389 3.864 38.867 ;
     RECT  2.4 38.867 3.624 38.963 ;
     RECT  0.144 38.725 0.312 39.109 ;
     RECT  0.144 39.109 0.36 39.205 ;
     RECT  13.2 38.677 13.704 39.251 ;
     RECT  2.4 38.963 3.384 39.923 ;
     RECT  0.144 39.205 0.456 40.115 ;
     RECT  10.368 37.427 10.812 40.405 ;
     RECT  12 38.677 12.024 40.405 ;
     RECT  13.2 39.251 13.656 40.549 ;
     RECT  10.368 40.405 12.024 40.643 ;
     RECT  0.144 40.115 0.264 40.787 ;
     RECT  2.4 39.923 3.288 41.509 ;
     RECT  0.144 40.787 0.168 41.699 ;
     RECT  10.368 40.643 11.64 42.227 ;
     RECT  13.2 40.549 14.616 42.467 ;
     RECT  5.1 38.435 6.024 42.469 ;
     RECT  7.8 37.427 9.384 42.469 ;
     RECT  2.4 41.509 4.104 43.285 ;
     RECT  5.1 42.469 9.384 43.285 ;
     RECT  10.368 42.227 10.812 43.333 ;
     RECT  13.2 42.467 13.656 43.715 ;
     RECT  0.144 43.573 0.168 43.859 ;
     RECT  10.368 43.333 11.4 44.051 ;
     RECT  2.4 43.285 9.384 44.627 ;
     RECT  2.4 44.627 6.024 44.629 ;
     RECT  0.24 44.389 0.504 44.869 ;
     RECT  0.192 44.869 0.504 44.965 ;
     RECT  2.304 44.629 6.024 45.731 ;
     RECT  0.144 44.965 0.504 45.973 ;
     RECT  0.144 45.973 0.552 46.693 ;
     RECT  13.2 43.715 13.512 46.933 ;
     RECT  0.144 46.693 0.6 46.981 ;
     RECT  7.296 44.627 9.384 47.075 ;
     RECT  2.304 45.731 3.96 47.125 ;
     RECT  5.1 45.731 6.024 47.125 ;
     RECT  13.2 46.933 14.376 47.171 ;
     RECT  2.304 47.125 6.024 47.221 ;
     RECT  0.144 46.981 1.128 47.411 ;
     RECT  0.144 47.411 0.552 47.891 ;
     RECT  0.144 47.891 0.408 47.987 ;
     RECT  2.304 47.221 6.744 47.987 ;
     RECT  9.36 47.075 9.384 48.227 ;
     RECT  7.8 47.075 8.232 48.755 ;
     RECT  13.2 47.171 13.512 48.949 ;
     RECT  12.144 47.173 12.168 48.995 ;
     RECT  10.368 44.051 10.812 48.997 ;
     RECT  13.2 48.949 13.656 48.997 ;
     RECT  2.304 47.987 3.96 49.043 ;
     RECT  12.96 48.997 13.656 49.139 ;
     RECT  5.1 47.987 6.744 49.475 ;
     RECT  0.144 47.987 0.36 49.477 ;
     RECT  10.368 48.997 11.448 49.477 ;
     RECT  13.2 49.139 13.656 49.811 ;
     RECT  9.552 49.477 11.448 49.859 ;
     RECT  2.304 49.043 3.72 50.051 ;
     RECT  9.552 49.859 11.4 50.147 ;
     RECT  0.144 49.477 0.408 50.387 ;
     RECT  7.8 48.755 8.112 50.677 ;
     RECT  10.368 50.147 11.4 51.205 ;
     RECT  2.4 50.051 3.72 51.253 ;
     RECT  5.1 49.475 6.024 51.253 ;
     RECT  13.2 49.811 13.512 51.445 ;
     RECT  10.224 51.205 11.4 51.635 ;
     RECT  7.392 50.677 8.112 51.683 ;
     RECT  7.8 51.683 8.112 51.685 ;
     RECT  2.4 51.253 6.024 51.971 ;
     RECT  0.144 50.387 0.168 52.355 ;
     RECT  10.224 51.635 11.16 52.499 ;
     RECT  5.1 51.971 6.024 52.789 ;
     RECT  10.272 52.499 11.16 53.029 ;
     RECT  7.8 51.685 9.096 53.075 ;
     RECT  13.104 51.445 13.512 53.077 ;
     RECT  13.104 53.077 13.896 53.315 ;
     RECT  2.4 51.971 3.72 53.557 ;
     RECT  5.1 52.789 6.264 53.557 ;
     RECT  2.4 53.557 6.264 53.603 ;
     RECT  10.272 53.029 11.592 53.651 ;
     RECT  13.104 53.315 13.512 53.651 ;
     RECT  14.64 54.181 14.664 54.323 ;
     RECT  2.4 53.603 6.024 54.325 ;
     RECT  2.304 54.325 6.024 54.467 ;
     RECT  2.304 54.467 5.832 54.515 ;
     RECT  2.4 54.515 5.832 55.379 ;
     RECT  11.952 54.085 11.976 55.427 ;
     RECT  10.272 53.651 10.812 55.571 ;
     RECT  2.4 55.379 3.72 55.907 ;
     RECT  14.784 55.957 14.808 56.099 ;
     RECT  5.1 55.379 5.832 56.483 ;
     RECT  2.4 55.907 3.672 56.531 ;
     RECT  7.8 53.075 8.112 57.541 ;
     RECT  12.144 55.525 12.168 58.115 ;
     RECT  13.2 53.651 13.512 58.693 ;
     RECT  10.5 55.571 10.812 59.605 ;
     RECT  2.4 56.531 3.624 60.275 ;
     RECT  9.648 59.605 10.812 61.043 ;
     RECT  13.2 58.693 14.232 61.043 ;
     RECT  7.8 57.541 8.52 61.763 ;
     RECT  2.4 60.275 2.712 62.649 ;
     RECT  5.1 56.483 5.412 62.649 ;
     RECT  7.8 61.763 8.112 62.649 ;
     RECT  10.5 61.043 10.812 62.649 ;
     RECT  13.2 61.043 13.512 62.649 ;
     RECT  15.9 38.339 16.212 62.649 ;
     RECT  18.6 37.811 18.912 62.649 ;
     RECT  2.4 62.649 2.52 62.663 ;
     RECT  5.1 62.649 5.22 62.663 ;
     RECT  7.8 62.649 7.92 62.663 ;
     RECT  10.5 62.649 10.62 62.663 ;
     RECT  13.2 62.649 13.32 62.663 ;
     RECT  15.9 62.649 16.02 62.663 ;
     RECT  18.6 62.649 18.72 62.663 ;
     RECT  5.412 2.869 6.864 3.301 ;
     RECT  6.024 3.443 7.056 6.755 ;
     RECT  2.712 3.925 4.224 5.747 ;
     RECT  2.712 5.747 5.1 6.805 ;
     RECT  6.024 6.755 6.216 6.805 ;
     RECT  2.712 6.805 3.984 7.813 ;
     RECT  4.008 6.805 5.1 7.859 ;
     RECT  2.712 7.813 3.888 9.251 ;
     RECT  3.912 7.859 5.1 9.251 ;
     RECT  6.696 9.013 7.8 9.253 ;
     RECT  2.712 9.251 5.1 10.597 ;
     RECT  6.216 10.259 7.488 11.459 ;
     RECT  2.712 10.597 3.792 11.365 ;
     RECT  3.816 10.597 5.1 11.555 ;
     RECT  6.024 11.459 7.488 13.811 ;
     RECT  3.048 11.555 5.1 11.941 ;
     RECT  3.048 11.941 4.176 13.715 ;
     RECT  0.168 12.563 0.216 14.005 ;
     RECT  8.112 12.853 9.264 14.773 ;
     RECT  11.784 13.669 13.2 14.915 ;
     RECT  2.856 13.715 4.176 14.773 ;
     RECT  10.812 14.915 13.2 16.069 ;
     RECT  2.856 15.491 4.176 16.067 ;
     RECT  8.112 16.019 9.264 19.621 ;
     RECT  9.288 16.019 10.32 19.285 ;
     RECT  2.856 16.067 5.1 16.549 ;
     RECT  10.812 16.069 12.24 16.357 ;
     RECT  10.812 16.357 12 17.605 ;
     RECT  2.856 16.549 4.08 16.595 ;
     RECT  4.104 16.549 5.1 18.181 ;
     RECT  2.712 16.595 4.08 17.077 ;
     RECT  2.712 17.077 3.936 18.467 ;
     RECT  0.264 18.419 0.312 19.861 ;
     RECT  2.712 18.467 4.032 18.803 ;
     RECT  10.812 18.563 12 18.659 ;
     RECT  10.812 18.659 12.24 19.861 ;
     RECT  14.376 18.709 15.9 19.381 ;
     RECT  2.712 18.803 4.752 19.139 ;
     RECT  2.712 19.139 3.24 19.909 ;
     RECT  14.808 19.381 15.9 19.619 ;
     RECT  0.144 19.427 0.192 19.619 ;
     RECT  9.288 19.571 10.32 20.869 ;
     RECT  0.144 19.619 0.24 20.629 ;
     RECT  13.512 19.619 14.64 23.411 ;
     RECT  14.664 19.619 15.9 23.411 ;
     RECT  10.812 19.861 11.952 21.349 ;
     RECT  11.976 20.147 13.2 21.395 ;
     RECT  0.36 21.059 0.408 22.117 ;
     RECT  11.688 21.395 13.2 23.317 ;
     RECT  0.144 21.731 0.192 22.981 ;
     RECT  3.24 22.019 3.336 22.165 ;
     RECT  3.24 22.165 4.224 23.269 ;
     RECT  0.36 22.307 0.408 23.413 ;
     RECT  6.024 22.307 7.8 23.557 ;
     RECT  12.072 23.317 13.2 25.139 ;
     RECT  10.812 23.411 12.048 25.139 ;
     RECT  6.792 23.557 7.8 31.955 ;
     RECT  0.264 25.283 0.312 26.291 ;
     RECT  3.96 25.859 5.1 30.179 ;
     RECT  0.24 26.291 0.312 26.629 ;
     RECT  0.24 26.629 0.288 27.445 ;
     RECT  0.144 29.123 0.192 30.613 ;
     RECT  13.8 29.605 15.168 30.851 ;
     RECT  3.624 30.179 5.1 30.947 ;
     RECT  0.408 30.419 0.504 31.621 ;
     RECT  13.656 30.851 15.168 31.621 ;
     RECT  3.192 30.947 5.1 32.437 ;
     RECT  0.456 31.621 0.504 31.717 ;
     RECT  13.656 31.621 15.024 32.195 ;
     RECT  6.024 31.955 7.8 32.869 ;
     RECT  9.384 31.955 10.5 34.069 ;
     RECT  13.656 32.195 15.168 38.339 ;
     RECT  3.96 32.437 5.1 34.499 ;
     RECT  6.024 32.869 7.44 33.395 ;
     RECT  10.812 33.301 12 34.259 ;
     RECT  12.024 33.301 13.2 34.259 ;
     RECT  6.024 33.395 7.68 34.165 ;
     RECT  0.144 33.923 0.288 35.413 ;
     RECT  9.384 34.069 10.368 34.117 ;
     RECT  6.6 34.165 7.68 34.211 ;
     RECT  6.6 34.211 7.8 35.363 ;
     RECT  12.48 34.259 13.2 34.933 ;
     RECT  3.768 34.499 5.1 35.219 ;
     RECT  13.056 36.515 13.2 37.669 ;
     RECT  0.264 36.611 0.36 37.573 ;
     RECT  3.816 37.141 5.1 38.389 ;
     RECT  6.792 37.141 7.8 37.475 ;
     RECT  9.384 37.427 10.368 48.227 ;
     RECT  6.312 37.475 7.8 38.435 ;
     RECT  0.264 37.763 0.36 38.725 ;
     RECT  13.056 37.811 13.2 38.677 ;
     RECT  13.656 38.339 13.704 38.677 ;
     RECT  3.864 38.389 5.1 38.867 ;
     RECT  10.812 38.677 12 40.405 ;
     RECT  12.024 38.677 13.2 40.643 ;
     RECT  0.312 38.725 0.36 39.109 ;
     RECT  3.624 38.867 5.1 38.963 ;
     RECT  13.656 39.251 13.704 40.549 ;
     RECT  14.616 40.549 15.9 42.467 ;
     RECT  4.104 41.509 5.1 43.285 ;
     RECT  10.812 42.227 11.4 43.333 ;
     RECT  0.144 43.859 0.168 44.389 ;
     RECT  0.144 44.389 0.24 44.869 ;
     RECT  6.024 44.627 7.296 47.075 ;
     RECT  0.144 44.869 0.192 44.965 ;
     RECT  3.96 45.731 5.1 47.125 ;
     RECT  14.376 46.933 15.9 47.171 ;
     RECT  1.128 46.981 2.304 47.411 ;
     RECT  6.024 47.075 7.8 47.221 ;
     RECT  8.232 47.075 9.36 48.227 ;
     RECT  10.812 47.173 12.144 48.995 ;
     RECT  12.168 47.173 13.2 48.995 ;
     RECT  6.744 47.221 7.8 49.475 ;
     RECT  0.36 47.987 0.408 49.477 ;
     RECT  3.96 47.987 5.1 49.043 ;
     RECT  8.232 48.227 10.368 48.755 ;
     RECT  8.112 48.755 10.368 49.477 ;
     RECT  10.812 48.995 13.2 48.997 ;
     RECT  11.448 48.997 12.96 49.139 ;
     RECT  3.72 49.043 5.1 51.253 ;
     RECT  6.024 49.475 7.8 50.677 ;
     RECT  8.112 49.477 9.552 50.147 ;
     RECT  10.224 50.147 10.368 51.205 ;
     RECT  6.024 50.677 7.392 51.683 ;
     RECT  11.16 51.635 11.4 53.029 ;
     RECT  6.024 51.683 6.264 52.789 ;
     RECT  9.096 51.685 10.224 52.499 ;
     RECT  3.72 51.971 5.1 53.557 ;
     RECT  9.096 52.499 10.272 53.075 ;
     RECT  11.592 53.029 13.104 53.651 ;
     RECT  13.512 53.315 13.896 54.181 ;
     RECT  10.812 53.651 13.2 54.085 ;
     RECT  10.812 54.085 11.952 55.427 ;
     RECT  11.976 54.085 13.2 55.427 ;
     RECT  13.512 54.181 14.64 54.323 ;
     RECT  14.664 54.181 15.9 54.323 ;
     RECT  3.72 55.379 5.1 55.907 ;
     RECT  10.812 55.427 13.2 55.525 ;
     RECT  10.812 55.525 12.144 58.115 ;
     RECT  12.168 55.525 13.2 58.115 ;
     RECT  3.672 55.907 5.1 56.531 ;
     RECT  13.512 55.957 14.784 56.099 ;
     RECT  14.808 55.957 15.9 56.099 ;
     RECT  3.624 56.531 5.1 60.275 ;
     RECT  8.52 59.605 9.648 61.043 ;
  END
END hbfd_rly_624_WE
END LIBRARY
